VERSION 5.7 ;
  NOWIREEXTENSIONATPIN ON ;
  DIVIDERCHAR "/" ;
  BUSBITCHARS "[]" ;
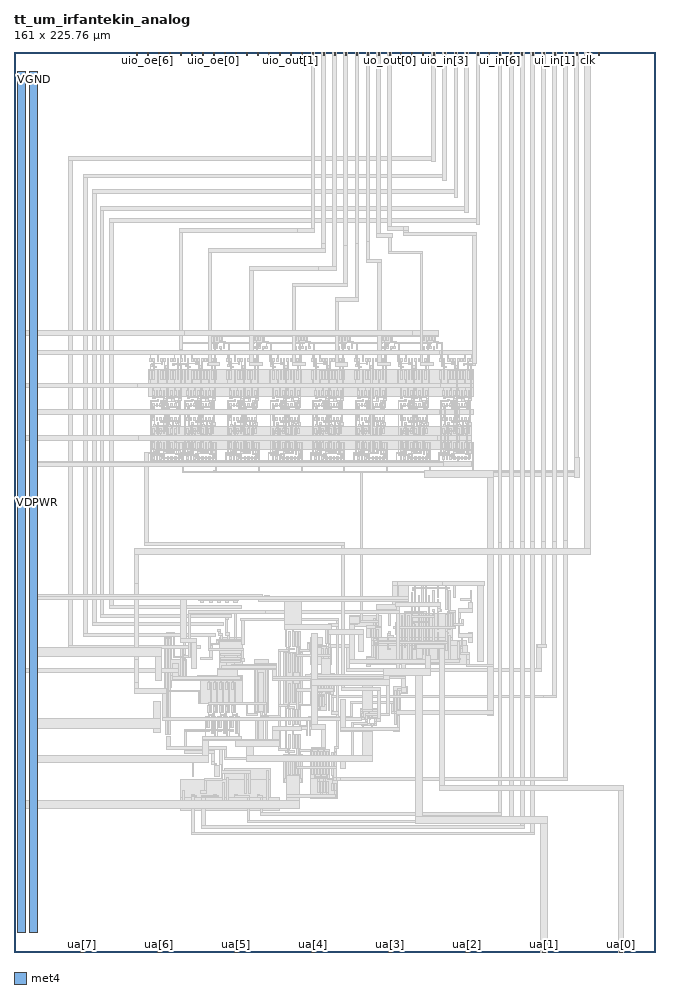
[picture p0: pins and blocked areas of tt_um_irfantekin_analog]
MACRO tt_um_irfantekin_analog
  CLASS BLOCK ;
  FOREIGN tt_um_irfantekin_analog ;
  ORIGIN 0.000 0.000 ;
  SIZE 161.000 BY 225.760 ;
  PIN clk
    DIRECTION INPUT ;
    USE SIGNAL ;
    ANTENNAGATEAREA 0.300000 ;
    ANTENNADIFFAREA 13.200000 ;
    PORT
      LAYER met4 ;
        RECT 143.830 224.760 144.130 225.760 ;
    END
  END clk
  PIN ena
    DIRECTION INPUT ;
    USE SIGNAL ;
    PORT
      LAYER met4 ;
        RECT 146.590 224.760 146.890 225.760 ;
    END
  END ena
  PIN rst_n
    DIRECTION INPUT ;
    USE SIGNAL ;
    ANTENNAGATEAREA 19.900000 ;
    PORT
      LAYER met4 ;
        RECT 141.070 224.760 141.370 225.760 ;
    END
  END rst_n
  PIN ua[0]
    DIRECTION INOUT ;
    USE SIGNAL ;
    ANTENNAGATEAREA 1.500000 ;
    PORT
      LAYER met4 ;
        RECT 151.810 0.000 152.710 1.000 ;
    END
  END ua[0]
  PIN ua[1]
    DIRECTION INOUT ;
    USE SIGNAL ;
    ANTENNAGATEAREA 1.500000 ;
    ANTENNADIFFAREA 16.500000 ;
    PORT
      LAYER met4 ;
        RECT 132.490 0.000 133.390 1.000 ;
    END
  END ua[1]
  PIN ua[2]
    DIRECTION INOUT ;
    USE SIGNAL ;
    PORT
      LAYER met4 ;
        RECT 113.170 0.000 114.070 1.000 ;
    END
  END ua[2]
  PIN ua[3]
    DIRECTION INOUT ;
    USE SIGNAL ;
    PORT
      LAYER met4 ;
        RECT 93.850 0.000 94.750 1.000 ;
    END
  END ua[3]
  PIN ua[4]
    DIRECTION INOUT ;
    USE SIGNAL ;
    PORT
      LAYER met4 ;
        RECT 74.530 0.000 75.430 1.000 ;
    END
  END ua[4]
  PIN ua[5]
    DIRECTION INOUT ;
    USE SIGNAL ;
    PORT
      LAYER met4 ;
        RECT 55.210 0.000 56.110 1.000 ;
    END
  END ua[5]
  PIN ua[6]
    DIRECTION INOUT ;
    USE SIGNAL ;
    PORT
      LAYER met4 ;
        RECT 35.890 0.000 36.790 1.000 ;
    END
  END ua[6]
  PIN ua[7]
    DIRECTION INOUT ;
    USE SIGNAL ;
    PORT
      LAYER met4 ;
        RECT 16.570 0.000 17.470 1.000 ;
    END
  END ua[7]
  PIN ui_in[0]
    DIRECTION INPUT ;
    USE SIGNAL ;
    ANTENNAGATEAREA 2.980000 ;
    PORT
      LAYER met4 ;
        RECT 138.310 224.760 138.610 225.760 ;
    END
  END ui_in[0]
  PIN ui_in[1]
    DIRECTION INPUT ;
    USE SIGNAL ;
    ANTENNAGATEAREA 2.980000 ;
    PORT
      LAYER met4 ;
        RECT 135.550 224.760 135.850 225.760 ;
    END
  END ui_in[1]
  PIN ui_in[2]
    DIRECTION INPUT ;
    USE SIGNAL ;
    ANTENNAGATEAREA 2.980000 ;
    PORT
      LAYER met4 ;
        RECT 132.790 224.760 133.090 225.760 ;
    END
  END ui_in[2]
  PIN ui_in[3]
    DIRECTION INPUT ;
    USE SIGNAL ;
    ANTENNAGATEAREA 4.000000 ;
    PORT
      LAYER met4 ;
        RECT 130.030 224.760 130.330 225.760 ;
    END
  END ui_in[3]
  PIN ui_in[4]
    DIRECTION INPUT ;
    USE SIGNAL ;
    ANTENNAGATEAREA 12.000000 ;
    PORT
      LAYER met4 ;
        RECT 127.270 224.760 127.570 225.760 ;
    END
  END ui_in[4]
  PIN ui_in[5]
    DIRECTION INPUT ;
    USE SIGNAL ;
    ANTENNAGATEAREA 17.199999 ;
    PORT
      LAYER met4 ;
        RECT 124.510 224.760 124.810 225.760 ;
    END
  END ui_in[5]
  PIN ui_in[6]
    DIRECTION INPUT ;
    USE SIGNAL ;
    ANTENNAGATEAREA 24.000000 ;
    PORT
      LAYER met4 ;
        RECT 121.750 224.760 122.050 225.760 ;
    END
  END ui_in[6]
  PIN ui_in[7]
    DIRECTION INPUT ;
    USE SIGNAL ;
    PORT
      LAYER met4 ;
        RECT 118.990 224.760 119.290 225.760 ;
    END
  END ui_in[7]
  PIN uio_in[0]
    DIRECTION INPUT ;
    USE SIGNAL ;
    ANTENNAGATEAREA 2.000000 ;
    PORT
      LAYER met4 ;
        RECT 116.230 224.760 116.530 225.760 ;
    END
  END uio_in[0]
  PIN uio_in[1]
    DIRECTION INPUT ;
    USE SIGNAL ;
    ANTENNAGATEAREA 3.500000 ;
    PORT
      LAYER met4 ;
        RECT 113.470 224.760 113.770 225.760 ;
    END
  END uio_in[1]
  PIN uio_in[2]
    DIRECTION INPUT ;
    USE SIGNAL ;
    ANTENNAGATEAREA 6.500000 ;
    PORT
      LAYER met4 ;
        RECT 110.710 224.760 111.010 225.760 ;
    END
  END uio_in[2]
  PIN uio_in[3]
    DIRECTION INPUT ;
    USE SIGNAL ;
    ANTENNAGATEAREA 10.000000 ;
    PORT
      LAYER met4 ;
        RECT 107.950 224.760 108.250 225.760 ;
    END
  END uio_in[3]
  PIN uio_in[4]
    DIRECTION INPUT ;
    USE SIGNAL ;
    ANTENNAGATEAREA 13.500000 ;
    PORT
      LAYER met4 ;
        RECT 105.190 224.760 105.490 225.760 ;
    END
  END uio_in[4]
  PIN uio_in[5]
    DIRECTION INPUT ;
    USE SIGNAL ;
    PORT
      LAYER met4 ;
        RECT 102.430 224.760 102.730 225.760 ;
    END
  END uio_in[5]
  PIN uio_in[6]
    DIRECTION INPUT ;
    USE SIGNAL ;
    PORT
      LAYER met4 ;
        RECT 99.670 224.760 99.970 225.760 ;
    END
  END uio_in[6]
  PIN uio_in[7]
    DIRECTION INPUT ;
    USE SIGNAL ;
    PORT
      LAYER met4 ;
        RECT 96.910 224.760 97.210 225.760 ;
    END
  END uio_in[7]
  PIN uio_oe[0]
    DIRECTION OUTPUT ;
    USE SIGNAL ;
    PORT
      LAYER met4 ;
        RECT 49.990 224.760 50.290 225.760 ;
    END
  END uio_oe[0]
  PIN uio_oe[1]
    DIRECTION OUTPUT ;
    USE SIGNAL ;
    PORT
      LAYER met4 ;
        RECT 47.230 224.760 47.530 225.760 ;
    END
  END uio_oe[1]
  PIN uio_oe[2]
    DIRECTION OUTPUT ;
    USE SIGNAL ;
    PORT
      LAYER met4 ;
        RECT 44.470 224.760 44.770 225.760 ;
    END
  END uio_oe[2]
  PIN uio_oe[3]
    DIRECTION OUTPUT ;
    USE SIGNAL ;
    PORT
      LAYER met4 ;
        RECT 41.710 224.760 42.010 225.760 ;
    END
  END uio_oe[3]
  PIN uio_oe[4]
    DIRECTION OUTPUT ;
    USE SIGNAL ;
    PORT
      LAYER met4 ;
        RECT 38.950 224.760 39.250 225.760 ;
    END
  END uio_oe[4]
  PIN uio_oe[5]
    DIRECTION OUTPUT ;
    USE SIGNAL ;
    PORT
      LAYER met4 ;
        RECT 36.190 224.760 36.490 225.760 ;
    END
  END uio_oe[5]
  PIN uio_oe[6]
    DIRECTION OUTPUT ;
    USE SIGNAL ;
    PORT
      LAYER met4 ;
        RECT 33.430 224.760 33.730 225.760 ;
    END
  END uio_oe[6]
  PIN uio_oe[7]
    DIRECTION OUTPUT ;
    USE SIGNAL ;
    PORT
      LAYER met4 ;
        RECT 30.670 224.760 30.970 225.760 ;
    END
  END uio_oe[7]
  PIN uio_out[0]
    DIRECTION OUTPUT ;
    USE SIGNAL ;
    PORT
      LAYER met4 ;
        RECT 72.070 224.760 72.370 225.760 ;
    END
  END uio_out[0]
  PIN uio_out[1]
    DIRECTION OUTPUT ;
    USE SIGNAL ;
    PORT
      LAYER met4 ;
        RECT 69.310 224.760 69.610 225.760 ;
    END
  END uio_out[1]
  PIN uio_out[2]
    DIRECTION OUTPUT ;
    USE SIGNAL ;
    PORT
      LAYER met4 ;
        RECT 66.550 224.760 66.850 225.760 ;
    END
  END uio_out[2]
  PIN uio_out[3]
    DIRECTION OUTPUT ;
    USE SIGNAL ;
    PORT
      LAYER met4 ;
        RECT 63.790 224.760 64.090 225.760 ;
    END
  END uio_out[3]
  PIN uio_out[4]
    DIRECTION OUTPUT ;
    USE SIGNAL ;
    PORT
      LAYER met4 ;
        RECT 61.030 224.760 61.330 225.760 ;
    END
  END uio_out[4]
  PIN uio_out[5]
    DIRECTION OUTPUT ;
    USE SIGNAL ;
    PORT
      LAYER met4 ;
        RECT 58.270 224.760 58.570 225.760 ;
    END
  END uio_out[5]
  PIN uio_out[6]
    DIRECTION OUTPUT ;
    USE SIGNAL ;
    PORT
      LAYER met4 ;
        RECT 55.510 224.760 55.810 225.760 ;
    END
  END uio_out[6]
  PIN uio_out[7]
    DIRECTION OUTPUT ;
    USE SIGNAL ;
    PORT
      LAYER met4 ;
        RECT 52.750 224.760 53.050 225.760 ;
    END
  END uio_out[7]
  PIN uo_out[0]
    DIRECTION OUTPUT ;
    USE SIGNAL ;
    ANTENNAGATEAREA 2.150000 ;
    ANTENNADIFFAREA 2.400000 ;
    PORT
      LAYER met4 ;
        RECT 94.150 224.760 94.450 225.760 ;
    END
  END uo_out[0]
  PIN uo_out[1]
    DIRECTION OUTPUT ;
    USE SIGNAL ;
    ANTENNAGATEAREA 2.530000 ;
    ANTENNADIFFAREA 2.400000 ;
    PORT
      LAYER met4 ;
        RECT 91.390 224.760 91.690 225.760 ;
    END
  END uo_out[1]
  PIN uo_out[2]
    DIRECTION OUTPUT ;
    USE SIGNAL ;
    ANTENNAGATEAREA 2.530000 ;
    ANTENNADIFFAREA 2.400000 ;
    PORT
      LAYER met4 ;
        RECT 88.630 224.760 88.930 225.760 ;
    END
  END uo_out[2]
  PIN uo_out[3]
    DIRECTION OUTPUT ;
    USE SIGNAL ;
    ANTENNAGATEAREA 2.530000 ;
    ANTENNADIFFAREA 2.400000 ;
    PORT
      LAYER met4 ;
        RECT 85.870 224.760 86.170 225.760 ;
    END
  END uo_out[3]
  PIN uo_out[4]
    DIRECTION OUTPUT ;
    USE SIGNAL ;
    ANTENNAGATEAREA 2.530000 ;
    ANTENNADIFFAREA 2.400000 ;
    PORT
      LAYER met4 ;
        RECT 83.110 224.760 83.410 225.760 ;
    END
  END uo_out[4]
  PIN uo_out[5]
    DIRECTION OUTPUT ;
    USE SIGNAL ;
    ANTENNAGATEAREA 2.530000 ;
    ANTENNADIFFAREA 2.400000 ;
    PORT
      LAYER met4 ;
        RECT 80.350 224.760 80.650 225.760 ;
    END
  END uo_out[5]
  PIN uo_out[6]
    DIRECTION OUTPUT ;
    USE SIGNAL ;
    ANTENNAGATEAREA 2.530000 ;
    ANTENNADIFFAREA 2.400000 ;
    PORT
      LAYER met4 ;
        RECT 77.590 224.760 77.890 225.760 ;
    END
  END uo_out[6]
  PIN uo_out[7]
    DIRECTION OUTPUT ;
    USE SIGNAL ;
    ANTENNAGATEAREA 3.930000 ;
    ANTENNADIFFAREA 2.400000 ;
    PORT
      LAYER met4 ;
        RECT 74.830 224.760 75.130 225.760 ;
    END
  END uo_out[7]
  PIN VDPWR
    DIRECTION INOUT ;
    USE POWER ;
    PORT
      LAYER met4 ;
        RECT 1.000 5.000 3.000 220.760 ;
    END
  END VDPWR
  PIN VGND
    DIRECTION INOUT ;
    USE GROUND ;
    PORT
      LAYER met4 ;
        RECT 4.000 5.000 6.000 220.760 ;
    END
  END VGND
  OBS
      LAYER nwell ;
        RECT 48.850 154.500 106.450 155.800 ;
        RECT 48.850 153.000 52.250 154.500 ;
        RECT 59.550 153.000 62.950 154.500 ;
        RECT 70.250 153.000 73.650 154.500 ;
        RECT 80.950 153.000 84.350 154.500 ;
        RECT 91.650 153.000 95.050 154.500 ;
        RECT 102.350 153.000 105.750 154.500 ;
        RECT 33.750 139.300 115.250 146.200 ;
        RECT 34.250 126.100 114.750 131.700 ;
        RECT 84.200 81.650 92.100 84.500 ;
        RECT 89.750 81.450 92.100 81.650 ;
        RECT 37.700 73.450 39.600 78.950 ;
        RECT 89.750 78.900 92.150 81.450 ;
        RECT 96.800 78.900 109.900 85.000 ;
        RECT 37.700 69.350 43.300 73.450 ;
        RECT 51.500 70.900 57.200 78.900 ;
        RECT 74.400 76.550 77.500 78.850 ;
        RECT 89.750 78.150 109.900 78.900 ;
        RECT 89.750 76.850 113.400 78.150 ;
        RECT 37.700 68.000 43.350 69.350 ;
        RECT 46.000 68.000 57.350 69.350 ;
        RECT 37.700 66.350 39.600 68.000 ;
        RECT 46.900 62.400 57.350 68.000 ;
        RECT 60.300 60.150 63.800 73.300 ;
        RECT 67.550 62.200 72.350 75.100 ;
        RECT 74.400 72.200 79.700 76.550 ;
        RECT 89.750 72.100 113.850 76.850 ;
        RECT 89.750 72.050 96.950 72.100 ;
        RECT 74.450 65.350 80.350 69.750 ;
        RECT 74.450 62.050 78.350 65.350 ;
        RECT 95.100 64.950 98.700 66.550 ;
        RECT 74.900 60.650 78.300 62.050 ;
        RECT 86.950 58.800 91.250 61.100 ;
        RECT 95.100 60.600 96.950 64.950 ;
        RECT 52.900 43.200 64.300 46.000 ;
        RECT 41.800 43.150 64.300 43.200 ;
        RECT 41.750 38.650 64.300 43.150 ;
        RECT 67.550 42.400 72.350 49.500 ;
        RECT 74.350 43.550 79.150 50.700 ;
        RECT 41.750 35.550 66.500 38.650 ;
        RECT 74.350 38.550 81.250 43.550 ;
      LAYER li1 ;
        RECT 45.750 155.800 48.050 155.900 ;
        RECT 54.150 155.800 56.450 155.900 ;
        RECT 65.850 155.800 68.150 155.900 ;
        RECT 75.250 155.800 77.550 155.900 ;
        RECT 87.050 155.800 89.350 155.900 ;
        RECT 97.550 155.800 99.850 155.900 ;
        RECT 45.050 154.700 106.450 155.800 ;
        RECT 49.250 154.300 49.450 154.700 ;
        RECT 50.850 154.300 51.050 154.700 ;
        RECT 59.950 154.300 60.150 154.700 ;
        RECT 61.550 154.300 61.750 154.700 ;
        RECT 70.650 154.300 70.850 154.700 ;
        RECT 72.250 154.300 72.450 154.700 ;
        RECT 81.350 154.300 81.550 154.700 ;
        RECT 82.950 154.300 83.150 154.700 ;
        RECT 92.050 154.300 92.250 154.700 ;
        RECT 93.650 154.300 93.850 154.700 ;
        RECT 102.750 154.300 102.950 154.700 ;
        RECT 104.350 154.300 104.550 154.700 ;
        RECT 49.150 153.300 49.550 154.300 ;
        RECT 49.950 153.300 50.350 154.300 ;
        RECT 50.750 153.300 51.150 154.300 ;
        RECT 51.550 153.300 51.950 154.300 ;
        RECT 59.850 153.300 60.250 154.300 ;
        RECT 60.650 153.300 61.050 154.300 ;
        RECT 61.450 153.300 61.850 154.300 ;
        RECT 62.250 153.300 62.650 154.300 ;
        RECT 70.550 153.300 70.950 154.300 ;
        RECT 71.350 153.300 71.750 154.300 ;
        RECT 72.150 153.300 72.550 154.300 ;
        RECT 72.950 153.300 73.350 154.300 ;
        RECT 81.250 153.300 81.650 154.300 ;
        RECT 82.050 153.300 82.450 154.300 ;
        RECT 82.850 153.300 83.250 154.300 ;
        RECT 83.650 153.300 84.050 154.300 ;
        RECT 91.950 153.300 92.350 154.300 ;
        RECT 92.750 153.300 93.150 154.300 ;
        RECT 93.550 153.300 93.950 154.300 ;
        RECT 94.350 153.300 94.750 154.300 ;
        RECT 102.650 153.300 103.050 154.300 ;
        RECT 103.450 153.300 103.850 154.300 ;
        RECT 104.250 153.300 104.650 154.300 ;
        RECT 105.050 153.300 105.450 154.300 ;
        RECT 49.350 152.600 49.750 153.000 ;
        RECT 50.050 152.900 50.250 153.300 ;
        RECT 51.650 153.100 51.850 153.300 ;
        RECT 50.950 152.900 51.350 153.000 ;
        RECT 51.650 152.900 53.050 153.100 ;
        RECT 50.050 152.700 51.350 152.900 ;
        RECT 50.850 152.600 51.350 152.700 ;
        RECT 52.550 152.600 53.050 152.900 ;
        RECT 60.050 152.600 60.450 153.000 ;
        RECT 60.750 152.900 60.950 153.300 ;
        RECT 62.350 153.100 62.550 153.300 ;
        RECT 61.650 152.900 62.050 153.000 ;
        RECT 62.350 152.900 63.750 153.100 ;
        RECT 60.750 152.700 62.050 152.900 ;
        RECT 61.550 152.600 62.050 152.700 ;
        RECT 63.250 152.600 63.750 152.900 ;
        RECT 70.750 152.600 71.150 153.000 ;
        RECT 71.450 152.900 71.650 153.300 ;
        RECT 73.050 153.100 73.250 153.300 ;
        RECT 72.350 152.900 72.750 153.000 ;
        RECT 73.050 152.900 74.450 153.100 ;
        RECT 71.450 152.700 72.750 152.900 ;
        RECT 72.250 152.600 72.750 152.700 ;
        RECT 73.950 152.600 74.450 152.900 ;
        RECT 81.450 152.600 81.850 153.000 ;
        RECT 82.150 152.900 82.350 153.300 ;
        RECT 83.750 153.100 83.950 153.300 ;
        RECT 83.050 152.900 83.450 153.000 ;
        RECT 83.750 152.900 85.150 153.100 ;
        RECT 82.150 152.700 83.450 152.900 ;
        RECT 82.950 152.600 83.450 152.700 ;
        RECT 84.650 152.600 85.150 152.900 ;
        RECT 92.150 152.600 92.550 153.000 ;
        RECT 92.850 152.900 93.050 153.300 ;
        RECT 94.450 153.100 94.650 153.300 ;
        RECT 93.750 152.900 94.150 153.000 ;
        RECT 94.450 152.900 95.850 153.100 ;
        RECT 92.850 152.700 94.150 152.900 ;
        RECT 93.650 152.600 94.150 152.700 ;
        RECT 95.350 152.600 95.850 152.900 ;
        RECT 102.850 152.600 103.250 153.000 ;
        RECT 103.550 152.900 103.750 153.300 ;
        RECT 105.150 153.100 105.350 153.300 ;
        RECT 104.450 152.900 104.850 153.000 ;
        RECT 105.150 152.900 106.550 153.100 ;
        RECT 103.550 152.700 104.850 152.900 ;
        RECT 104.350 152.600 104.850 152.700 ;
        RECT 106.050 152.600 106.550 152.900 ;
        RECT 50.150 152.100 50.550 152.500 ;
        RECT 50.850 151.900 51.050 152.600 ;
        RECT 52.550 151.900 52.750 152.600 ;
        RECT 60.850 152.100 61.250 152.500 ;
        RECT 61.550 151.900 61.750 152.600 ;
        RECT 63.250 151.900 63.450 152.600 ;
        RECT 71.550 152.100 71.950 152.500 ;
        RECT 72.250 151.900 72.450 152.600 ;
        RECT 73.950 151.900 74.150 152.600 ;
        RECT 82.250 152.100 82.650 152.500 ;
        RECT 82.950 151.900 83.150 152.600 ;
        RECT 84.650 151.900 84.850 152.600 ;
        RECT 92.950 152.100 93.350 152.500 ;
        RECT 93.650 151.900 93.850 152.600 ;
        RECT 95.350 151.900 95.550 152.600 ;
        RECT 103.650 152.100 104.050 152.500 ;
        RECT 104.350 151.900 104.550 152.600 ;
        RECT 106.050 151.900 106.250 152.600 ;
        RECT 49.150 151.400 49.550 151.900 ;
        RECT 49.950 151.400 50.350 151.900 ;
        RECT 50.750 151.400 51.150 151.900 ;
        RECT 51.650 151.400 52.050 151.900 ;
        RECT 52.450 151.400 52.850 151.900 ;
        RECT 59.850 151.400 60.250 151.900 ;
        RECT 60.650 151.400 61.050 151.900 ;
        RECT 61.450 151.400 61.850 151.900 ;
        RECT 62.350 151.400 62.750 151.900 ;
        RECT 63.150 151.400 63.550 151.900 ;
        RECT 70.550 151.400 70.950 151.900 ;
        RECT 71.350 151.400 71.750 151.900 ;
        RECT 72.150 151.400 72.550 151.900 ;
        RECT 73.050 151.400 73.450 151.900 ;
        RECT 73.850 151.400 74.250 151.900 ;
        RECT 81.250 151.400 81.650 151.900 ;
        RECT 82.050 151.400 82.450 151.900 ;
        RECT 82.850 151.400 83.250 151.900 ;
        RECT 83.750 151.400 84.150 151.900 ;
        RECT 84.550 151.400 84.950 151.900 ;
        RECT 91.950 151.400 92.350 151.900 ;
        RECT 92.750 151.400 93.150 151.900 ;
        RECT 93.550 151.400 93.950 151.900 ;
        RECT 94.450 151.400 94.850 151.900 ;
        RECT 95.250 151.400 95.650 151.900 ;
        RECT 102.650 151.400 103.050 151.900 ;
        RECT 103.450 151.400 103.850 151.900 ;
        RECT 104.250 151.400 104.650 151.900 ;
        RECT 105.150 151.400 105.550 151.900 ;
        RECT 105.950 151.400 106.350 151.900 ;
        RECT 49.250 151.000 49.450 151.400 ;
        RECT 51.750 151.000 51.950 151.400 ;
        RECT 59.950 151.000 60.150 151.400 ;
        RECT 62.450 151.000 62.650 151.400 ;
        RECT 70.650 151.000 70.850 151.400 ;
        RECT 73.150 151.000 73.350 151.400 ;
        RECT 81.350 151.000 81.550 151.400 ;
        RECT 83.850 151.000 84.050 151.400 ;
        RECT 92.050 151.000 92.250 151.400 ;
        RECT 94.550 151.000 94.750 151.400 ;
        RECT 102.750 151.000 102.950 151.400 ;
        RECT 105.250 151.000 105.450 151.400 ;
        RECT 33.750 149.900 115.250 151.000 ;
        RECT 34.150 148.900 34.350 149.900 ;
        RECT 36.050 148.900 36.250 149.900 ;
        RECT 40.150 148.900 40.350 149.900 ;
        RECT 41.850 148.900 42.050 149.900 ;
        RECT 42.750 148.900 42.950 149.900 ;
        RECT 44.650 148.900 44.850 149.900 ;
        RECT 48.750 148.900 48.950 149.900 ;
        RECT 50.450 148.900 50.650 149.900 ;
        RECT 53.450 148.900 53.650 149.900 ;
        RECT 55.350 148.900 55.550 149.900 ;
        RECT 59.450 148.900 59.650 149.900 ;
        RECT 61.150 148.900 61.350 149.900 ;
        RECT 64.150 148.900 64.350 149.900 ;
        RECT 66.050 148.900 66.250 149.900 ;
        RECT 70.150 148.900 70.350 149.900 ;
        RECT 71.850 148.900 72.050 149.900 ;
        RECT 74.850 148.900 75.050 149.900 ;
        RECT 76.750 148.900 76.950 149.900 ;
        RECT 80.850 148.900 81.050 149.900 ;
        RECT 82.550 148.900 82.750 149.900 ;
        RECT 85.550 148.900 85.750 149.900 ;
        RECT 87.450 148.900 87.650 149.900 ;
        RECT 91.550 148.900 91.750 149.900 ;
        RECT 93.250 148.900 93.450 149.900 ;
        RECT 96.250 148.900 96.450 149.900 ;
        RECT 98.150 148.900 98.350 149.900 ;
        RECT 102.250 148.900 102.450 149.900 ;
        RECT 103.950 148.900 104.150 149.900 ;
        RECT 106.950 148.900 107.150 149.900 ;
        RECT 108.850 148.900 109.050 149.900 ;
        RECT 112.950 148.900 113.150 149.900 ;
        RECT 114.650 148.900 114.850 149.900 ;
        RECT 34.050 148.100 34.450 148.900 ;
        RECT 34.850 148.100 35.250 148.900 ;
        RECT 35.950 148.100 36.350 148.900 ;
        RECT 36.750 148.100 37.150 148.900 ;
        RECT 37.550 148.100 37.950 148.900 ;
        RECT 38.450 148.100 38.850 148.900 ;
        RECT 39.250 148.100 39.650 148.900 ;
        RECT 40.050 148.100 40.450 148.900 ;
        RECT 40.950 148.100 41.350 148.900 ;
        RECT 41.750 148.100 42.150 148.900 ;
        RECT 42.650 148.100 43.050 148.900 ;
        RECT 43.450 148.100 43.850 148.900 ;
        RECT 44.550 148.100 44.950 148.900 ;
        RECT 45.350 148.100 45.750 148.900 ;
        RECT 46.150 148.100 46.550 148.900 ;
        RECT 47.050 148.100 47.450 148.900 ;
        RECT 47.850 148.100 48.250 148.900 ;
        RECT 48.650 148.100 49.050 148.900 ;
        RECT 49.550 148.100 49.950 148.900 ;
        RECT 50.350 148.100 50.750 148.900 ;
        RECT 53.350 148.100 53.750 148.900 ;
        RECT 54.150 148.100 54.550 148.900 ;
        RECT 55.250 148.100 55.650 148.900 ;
        RECT 56.050 148.100 56.450 148.900 ;
        RECT 56.850 148.100 57.250 148.900 ;
        RECT 57.750 148.100 58.150 148.900 ;
        RECT 58.550 148.100 58.950 148.900 ;
        RECT 59.350 148.100 59.750 148.900 ;
        RECT 60.250 148.100 60.650 148.900 ;
        RECT 61.050 148.100 61.450 148.900 ;
        RECT 64.050 148.100 64.450 148.900 ;
        RECT 64.850 148.100 65.250 148.900 ;
        RECT 65.950 148.100 66.350 148.900 ;
        RECT 66.750 148.100 67.150 148.900 ;
        RECT 67.550 148.100 67.950 148.900 ;
        RECT 68.450 148.100 68.850 148.900 ;
        RECT 69.250 148.100 69.650 148.900 ;
        RECT 70.050 148.100 70.450 148.900 ;
        RECT 70.950 148.100 71.350 148.900 ;
        RECT 71.750 148.100 72.150 148.900 ;
        RECT 74.750 148.100 75.150 148.900 ;
        RECT 75.550 148.100 75.950 148.900 ;
        RECT 76.650 148.100 77.050 148.900 ;
        RECT 77.450 148.100 77.850 148.900 ;
        RECT 78.250 148.100 78.650 148.900 ;
        RECT 79.150 148.100 79.550 148.900 ;
        RECT 79.950 148.100 80.350 148.900 ;
        RECT 80.750 148.100 81.150 148.900 ;
        RECT 81.650 148.100 82.050 148.900 ;
        RECT 82.450 148.100 82.850 148.900 ;
        RECT 85.450 148.100 85.850 148.900 ;
        RECT 86.250 148.100 86.650 148.900 ;
        RECT 87.350 148.100 87.750 148.900 ;
        RECT 88.150 148.100 88.550 148.900 ;
        RECT 88.950 148.100 89.350 148.900 ;
        RECT 89.850 148.100 90.250 148.900 ;
        RECT 90.650 148.100 91.050 148.900 ;
        RECT 91.450 148.100 91.850 148.900 ;
        RECT 92.350 148.100 92.750 148.900 ;
        RECT 93.150 148.100 93.550 148.900 ;
        RECT 96.150 148.100 96.550 148.900 ;
        RECT 96.950 148.100 97.350 148.900 ;
        RECT 98.050 148.100 98.450 148.900 ;
        RECT 98.850 148.100 99.250 148.900 ;
        RECT 99.650 148.100 100.050 148.900 ;
        RECT 100.550 148.100 100.950 148.900 ;
        RECT 101.350 148.100 101.750 148.900 ;
        RECT 102.150 148.100 102.550 148.900 ;
        RECT 103.050 148.100 103.450 148.900 ;
        RECT 103.850 148.100 104.250 148.900 ;
        RECT 106.850 148.100 107.250 148.900 ;
        RECT 107.650 148.100 108.050 148.900 ;
        RECT 108.750 148.100 109.150 148.900 ;
        RECT 109.550 148.100 109.950 148.900 ;
        RECT 110.350 148.100 110.750 148.900 ;
        RECT 111.250 148.100 111.650 148.900 ;
        RECT 112.050 148.100 112.450 148.900 ;
        RECT 112.850 148.100 113.250 148.900 ;
        RECT 113.750 148.100 114.150 148.900 ;
        RECT 114.550 148.100 114.950 148.900 ;
        RECT 34.350 147.200 34.750 147.300 ;
        RECT 34.150 146.900 34.750 147.200 ;
        RECT 34.950 146.900 35.150 148.100 ;
        RECT 36.950 147.400 37.350 147.800 ;
        RECT 37.650 147.000 37.850 148.100 ;
        RECT 38.550 147.000 38.750 148.100 ;
        RECT 39.850 147.500 40.250 147.600 ;
        RECT 41.050 147.500 41.250 148.100 ;
        RECT 39.850 147.300 41.250 147.500 ;
        RECT 39.850 147.200 40.250 147.300 ;
        RECT 34.150 145.900 34.350 146.900 ;
        RECT 34.950 146.500 35.650 146.900 ;
        RECT 34.950 145.900 35.150 146.500 ;
        RECT 37.650 146.400 38.750 147.000 ;
        RECT 37.650 145.900 37.850 146.400 ;
        RECT 38.550 145.900 38.750 146.400 ;
        RECT 41.050 145.900 41.250 147.300 ;
        RECT 41.550 147.200 41.950 147.600 ;
        RECT 42.950 146.900 43.350 147.300 ;
        RECT 43.550 146.900 43.750 148.100 ;
        RECT 45.550 147.400 45.950 147.800 ;
        RECT 46.250 147.000 46.450 148.100 ;
        RECT 47.150 147.000 47.350 148.100 ;
        RECT 48.450 147.500 48.850 147.600 ;
        RECT 49.650 147.500 49.850 148.100 ;
        RECT 48.450 147.300 49.850 147.500 ;
        RECT 48.450 147.200 48.850 147.300 ;
        RECT 43.550 146.500 44.250 146.900 ;
        RECT 43.550 145.900 43.750 146.500 ;
        RECT 46.250 146.400 47.350 147.000 ;
        RECT 46.250 145.900 46.450 146.400 ;
        RECT 47.150 145.900 47.350 146.400 ;
        RECT 49.650 145.900 49.850 147.300 ;
        RECT 50.150 147.200 50.550 147.600 ;
        RECT 53.650 146.900 54.050 147.300 ;
        RECT 54.250 146.900 54.450 148.100 ;
        RECT 56.250 147.400 56.650 147.800 ;
        RECT 56.950 147.000 57.150 148.100 ;
        RECT 57.850 147.000 58.050 148.100 ;
        RECT 59.150 147.500 59.550 147.600 ;
        RECT 60.350 147.500 60.550 148.100 ;
        RECT 59.150 147.300 60.550 147.500 ;
        RECT 59.150 147.200 59.550 147.300 ;
        RECT 54.250 146.500 54.950 146.900 ;
        RECT 54.250 145.900 54.450 146.500 ;
        RECT 56.950 146.400 58.050 147.000 ;
        RECT 56.950 145.900 57.150 146.400 ;
        RECT 57.850 145.900 58.050 146.400 ;
        RECT 60.350 145.900 60.550 147.300 ;
        RECT 60.850 147.200 61.250 147.600 ;
        RECT 64.350 146.900 64.750 147.300 ;
        RECT 64.950 146.900 65.150 148.100 ;
        RECT 66.950 147.400 67.350 147.800 ;
        RECT 67.650 147.000 67.850 148.100 ;
        RECT 68.550 147.000 68.750 148.100 ;
        RECT 69.850 147.500 70.250 147.600 ;
        RECT 71.050 147.500 71.250 148.100 ;
        RECT 69.850 147.300 71.250 147.500 ;
        RECT 69.850 147.200 70.250 147.300 ;
        RECT 64.950 146.500 65.650 146.900 ;
        RECT 64.950 145.900 65.150 146.500 ;
        RECT 67.650 146.400 68.750 147.000 ;
        RECT 67.650 145.900 67.850 146.400 ;
        RECT 68.550 145.900 68.750 146.400 ;
        RECT 71.050 145.900 71.250 147.300 ;
        RECT 71.550 147.200 71.950 147.600 ;
        RECT 75.050 146.900 75.450 147.300 ;
        RECT 75.650 146.900 75.850 148.100 ;
        RECT 77.650 147.400 78.050 147.800 ;
        RECT 78.350 147.000 78.550 148.100 ;
        RECT 79.250 147.000 79.450 148.100 ;
        RECT 80.550 147.500 80.950 147.600 ;
        RECT 81.750 147.500 81.950 148.100 ;
        RECT 80.550 147.300 81.950 147.500 ;
        RECT 80.550 147.200 80.950 147.300 ;
        RECT 75.650 146.500 76.350 146.900 ;
        RECT 75.650 145.900 75.850 146.500 ;
        RECT 78.350 146.400 79.450 147.000 ;
        RECT 78.350 145.900 78.550 146.400 ;
        RECT 79.250 145.900 79.450 146.400 ;
        RECT 81.750 145.900 81.950 147.300 ;
        RECT 82.250 147.200 82.650 147.600 ;
        RECT 85.750 146.900 86.150 147.300 ;
        RECT 86.350 146.900 86.550 148.100 ;
        RECT 88.350 147.400 88.750 147.800 ;
        RECT 89.050 147.000 89.250 148.100 ;
        RECT 89.950 147.000 90.150 148.100 ;
        RECT 91.250 147.500 91.650 147.600 ;
        RECT 92.450 147.500 92.650 148.100 ;
        RECT 91.250 147.300 92.650 147.500 ;
        RECT 91.250 147.200 91.650 147.300 ;
        RECT 86.350 146.500 87.050 146.900 ;
        RECT 86.350 145.900 86.550 146.500 ;
        RECT 89.050 146.400 90.150 147.000 ;
        RECT 89.050 145.900 89.250 146.400 ;
        RECT 89.950 145.900 90.150 146.400 ;
        RECT 92.450 145.900 92.650 147.300 ;
        RECT 92.950 147.200 93.350 147.600 ;
        RECT 96.450 146.900 96.850 147.300 ;
        RECT 97.050 146.900 97.250 148.100 ;
        RECT 99.050 147.400 99.450 147.800 ;
        RECT 99.750 147.000 99.950 148.100 ;
        RECT 100.650 147.000 100.850 148.100 ;
        RECT 101.950 147.500 102.350 147.600 ;
        RECT 103.150 147.500 103.350 148.100 ;
        RECT 101.950 147.300 103.350 147.500 ;
        RECT 101.950 147.200 102.350 147.300 ;
        RECT 97.050 146.500 97.750 146.900 ;
        RECT 97.050 145.900 97.250 146.500 ;
        RECT 99.750 146.400 100.850 147.000 ;
        RECT 99.750 145.900 99.950 146.400 ;
        RECT 100.650 145.900 100.850 146.400 ;
        RECT 103.150 145.900 103.350 147.300 ;
        RECT 103.650 147.200 104.050 147.600 ;
        RECT 107.150 146.900 107.550 147.300 ;
        RECT 107.750 146.900 107.950 148.100 ;
        RECT 109.750 147.400 110.150 147.800 ;
        RECT 110.450 147.000 110.650 148.100 ;
        RECT 111.350 147.000 111.550 148.100 ;
        RECT 112.650 147.500 113.050 147.600 ;
        RECT 113.850 147.500 114.050 148.100 ;
        RECT 112.650 147.300 114.050 147.500 ;
        RECT 112.650 147.200 113.050 147.300 ;
        RECT 107.750 146.500 108.450 146.900 ;
        RECT 107.750 145.900 107.950 146.500 ;
        RECT 110.450 146.400 111.550 147.000 ;
        RECT 110.450 145.900 110.650 146.400 ;
        RECT 111.350 145.900 111.550 146.400 ;
        RECT 113.850 145.900 114.050 147.300 ;
        RECT 114.350 147.200 114.750 147.600 ;
        RECT 34.050 143.600 34.450 145.900 ;
        RECT 34.850 143.600 35.250 145.900 ;
        RECT 35.950 143.600 36.350 145.900 ;
        RECT 36.750 143.600 37.150 145.900 ;
        RECT 37.550 143.600 37.950 145.900 ;
        RECT 38.450 143.600 38.850 145.900 ;
        RECT 39.250 143.600 39.650 145.900 ;
        RECT 40.050 143.600 40.450 145.900 ;
        RECT 40.950 143.600 41.350 145.900 ;
        RECT 41.750 143.600 42.150 145.900 ;
        RECT 42.650 143.600 43.050 145.900 ;
        RECT 43.450 143.600 43.850 145.900 ;
        RECT 44.550 143.600 44.950 145.900 ;
        RECT 45.350 143.600 45.750 145.900 ;
        RECT 46.150 143.600 46.550 145.900 ;
        RECT 47.050 143.600 47.450 145.900 ;
        RECT 47.850 143.600 48.250 145.900 ;
        RECT 48.650 143.600 49.050 145.900 ;
        RECT 49.550 143.600 49.950 145.900 ;
        RECT 50.350 143.600 50.750 145.900 ;
        RECT 53.350 143.600 53.750 145.900 ;
        RECT 54.150 143.600 54.550 145.900 ;
        RECT 55.250 143.600 55.650 145.900 ;
        RECT 56.050 143.600 56.450 145.900 ;
        RECT 56.850 143.600 57.250 145.900 ;
        RECT 57.750 143.600 58.150 145.900 ;
        RECT 58.550 143.600 58.950 145.900 ;
        RECT 59.350 143.600 59.750 145.900 ;
        RECT 60.250 143.600 60.650 145.900 ;
        RECT 61.050 143.600 61.450 145.900 ;
        RECT 64.050 143.600 64.450 145.900 ;
        RECT 64.850 143.600 65.250 145.900 ;
        RECT 65.950 143.600 66.350 145.900 ;
        RECT 66.750 143.600 67.150 145.900 ;
        RECT 67.550 143.600 67.950 145.900 ;
        RECT 68.450 143.600 68.850 145.900 ;
        RECT 69.250 143.600 69.650 145.900 ;
        RECT 70.050 143.600 70.450 145.900 ;
        RECT 70.950 143.600 71.350 145.900 ;
        RECT 71.750 143.600 72.150 145.900 ;
        RECT 74.750 143.600 75.150 145.900 ;
        RECT 75.550 143.600 75.950 145.900 ;
        RECT 76.650 143.600 77.050 145.900 ;
        RECT 77.450 143.600 77.850 145.900 ;
        RECT 78.250 143.600 78.650 145.900 ;
        RECT 79.150 143.600 79.550 145.900 ;
        RECT 79.950 143.600 80.350 145.900 ;
        RECT 80.750 143.600 81.150 145.900 ;
        RECT 81.650 143.600 82.050 145.900 ;
        RECT 82.450 143.600 82.850 145.900 ;
        RECT 85.450 143.600 85.850 145.900 ;
        RECT 86.250 143.600 86.650 145.900 ;
        RECT 87.350 143.600 87.750 145.900 ;
        RECT 88.150 143.600 88.550 145.900 ;
        RECT 88.950 143.600 89.350 145.900 ;
        RECT 89.850 143.600 90.250 145.900 ;
        RECT 90.650 143.600 91.050 145.900 ;
        RECT 91.450 143.600 91.850 145.900 ;
        RECT 92.350 143.600 92.750 145.900 ;
        RECT 93.150 143.600 93.550 145.900 ;
        RECT 96.150 143.600 96.550 145.900 ;
        RECT 96.950 143.600 97.350 145.900 ;
        RECT 98.050 143.600 98.450 145.900 ;
        RECT 98.850 143.600 99.250 145.900 ;
        RECT 99.650 143.600 100.050 145.900 ;
        RECT 100.550 143.600 100.950 145.900 ;
        RECT 101.350 143.600 101.750 145.900 ;
        RECT 102.150 143.600 102.550 145.900 ;
        RECT 103.050 143.600 103.450 145.900 ;
        RECT 103.850 143.600 104.250 145.900 ;
        RECT 106.850 143.600 107.250 145.900 ;
        RECT 107.650 143.600 108.050 145.900 ;
        RECT 108.750 143.600 109.150 145.900 ;
        RECT 109.550 143.600 109.950 145.900 ;
        RECT 110.350 143.600 110.750 145.900 ;
        RECT 111.250 143.600 111.650 145.900 ;
        RECT 112.050 143.600 112.450 145.900 ;
        RECT 112.850 143.600 113.250 145.900 ;
        RECT 113.750 143.600 114.150 145.900 ;
        RECT 114.550 143.600 114.950 145.900 ;
        RECT 34.150 142.700 34.350 143.600 ;
        RECT 36.050 142.700 36.250 143.600 ;
        RECT 40.150 142.700 40.350 143.600 ;
        RECT 41.850 142.700 42.050 143.600 ;
        RECT 42.750 142.700 42.950 143.600 ;
        RECT 44.650 142.700 44.850 143.600 ;
        RECT 48.750 142.700 48.950 143.600 ;
        RECT 50.450 142.700 50.650 143.600 ;
        RECT 53.450 142.700 53.650 143.600 ;
        RECT 55.350 142.700 55.550 143.600 ;
        RECT 59.450 142.700 59.650 143.600 ;
        RECT 61.150 142.700 61.350 143.600 ;
        RECT 64.150 142.700 64.350 143.600 ;
        RECT 66.050 142.700 66.250 143.600 ;
        RECT 70.150 142.700 70.350 143.600 ;
        RECT 71.850 142.700 72.050 143.600 ;
        RECT 74.850 142.700 75.050 143.600 ;
        RECT 76.750 142.700 76.950 143.600 ;
        RECT 80.850 142.700 81.050 143.600 ;
        RECT 82.550 142.700 82.750 143.600 ;
        RECT 85.550 142.700 85.750 143.600 ;
        RECT 87.450 142.700 87.650 143.600 ;
        RECT 91.550 142.700 91.750 143.600 ;
        RECT 93.250 142.700 93.450 143.600 ;
        RECT 96.250 142.700 96.450 143.600 ;
        RECT 98.150 142.700 98.350 143.600 ;
        RECT 102.250 142.700 102.450 143.600 ;
        RECT 103.950 142.700 104.150 143.600 ;
        RECT 106.950 142.700 107.150 143.600 ;
        RECT 108.850 142.700 109.050 143.600 ;
        RECT 112.950 142.700 113.150 143.600 ;
        RECT 114.650 142.700 114.850 143.600 ;
        RECT 33.750 141.500 115.250 142.700 ;
        RECT 34.850 140.900 35.050 141.500 ;
        RECT 36.650 140.900 36.850 141.500 ;
        RECT 38.550 140.900 38.750 141.500 ;
        RECT 40.350 140.900 40.550 141.500 ;
        RECT 43.450 140.900 43.650 141.500 ;
        RECT 45.250 140.900 45.450 141.500 ;
        RECT 47.150 140.900 47.350 141.500 ;
        RECT 48.950 140.900 49.150 141.500 ;
        RECT 54.150 140.900 54.350 141.500 ;
        RECT 55.950 140.900 56.150 141.500 ;
        RECT 57.850 140.900 58.050 141.500 ;
        RECT 59.650 140.900 59.850 141.500 ;
        RECT 64.850 140.900 65.050 141.500 ;
        RECT 66.650 140.900 66.850 141.500 ;
        RECT 68.550 140.900 68.750 141.500 ;
        RECT 70.350 140.900 70.550 141.500 ;
        RECT 75.550 140.900 75.750 141.500 ;
        RECT 77.350 140.900 77.550 141.500 ;
        RECT 79.250 140.900 79.450 141.500 ;
        RECT 81.050 140.900 81.250 141.500 ;
        RECT 86.250 140.900 86.450 141.500 ;
        RECT 88.050 140.900 88.250 141.500 ;
        RECT 89.950 140.900 90.150 141.500 ;
        RECT 91.750 140.900 91.950 141.500 ;
        RECT 96.950 140.900 97.150 141.500 ;
        RECT 98.750 140.900 98.950 141.500 ;
        RECT 100.650 140.900 100.850 141.500 ;
        RECT 102.450 140.900 102.650 141.500 ;
        RECT 107.650 140.900 107.850 141.500 ;
        RECT 109.450 140.900 109.650 141.500 ;
        RECT 111.350 140.900 111.550 141.500 ;
        RECT 113.150 140.900 113.350 141.500 ;
        RECT 34.750 139.600 35.150 140.900 ;
        RECT 35.650 139.600 36.050 140.900 ;
        RECT 36.550 139.600 36.950 140.900 ;
        RECT 37.450 139.600 37.850 140.900 ;
        RECT 38.450 139.600 38.850 140.900 ;
        RECT 39.350 139.600 39.750 140.900 ;
        RECT 40.250 139.600 40.650 140.900 ;
        RECT 41.150 139.600 41.550 140.900 ;
        RECT 43.350 139.600 43.750 140.900 ;
        RECT 44.250 139.600 44.650 140.900 ;
        RECT 45.150 139.600 45.550 140.900 ;
        RECT 46.050 139.600 46.450 140.900 ;
        RECT 47.050 139.600 47.450 140.900 ;
        RECT 47.950 139.600 48.350 140.900 ;
        RECT 48.850 139.600 49.250 140.900 ;
        RECT 49.750 139.600 50.150 140.900 ;
        RECT 54.050 139.600 54.450 140.900 ;
        RECT 54.950 139.600 55.350 140.900 ;
        RECT 55.850 139.600 56.250 140.900 ;
        RECT 56.750 139.600 57.150 140.900 ;
        RECT 57.750 139.600 58.150 140.900 ;
        RECT 58.650 139.600 59.050 140.900 ;
        RECT 59.550 139.600 59.950 140.900 ;
        RECT 60.450 139.600 60.850 140.900 ;
        RECT 64.750 139.600 65.150 140.900 ;
        RECT 65.650 139.600 66.050 140.900 ;
        RECT 66.550 139.600 66.950 140.900 ;
        RECT 67.450 139.600 67.850 140.900 ;
        RECT 68.450 139.600 68.850 140.900 ;
        RECT 69.350 139.600 69.750 140.900 ;
        RECT 70.250 139.600 70.650 140.900 ;
        RECT 71.150 139.600 71.550 140.900 ;
        RECT 75.450 139.600 75.850 140.900 ;
        RECT 76.350 139.600 76.750 140.900 ;
        RECT 77.250 139.600 77.650 140.900 ;
        RECT 78.150 139.600 78.550 140.900 ;
        RECT 79.150 139.600 79.550 140.900 ;
        RECT 80.050 139.600 80.450 140.900 ;
        RECT 80.950 139.600 81.350 140.900 ;
        RECT 81.850 139.600 82.250 140.900 ;
        RECT 86.150 139.600 86.550 140.900 ;
        RECT 87.050 139.600 87.450 140.900 ;
        RECT 87.950 139.600 88.350 140.900 ;
        RECT 88.850 139.600 89.250 140.900 ;
        RECT 89.850 139.600 90.250 140.900 ;
        RECT 90.750 139.600 91.150 140.900 ;
        RECT 91.650 139.600 92.050 140.900 ;
        RECT 92.550 139.600 92.950 140.900 ;
        RECT 96.850 139.600 97.250 140.900 ;
        RECT 97.750 139.600 98.150 140.900 ;
        RECT 98.650 139.600 99.050 140.900 ;
        RECT 99.550 139.600 99.950 140.900 ;
        RECT 100.550 139.600 100.950 140.900 ;
        RECT 101.450 139.600 101.850 140.900 ;
        RECT 102.350 139.600 102.750 140.900 ;
        RECT 103.250 139.600 103.650 140.900 ;
        RECT 107.550 139.600 107.950 140.900 ;
        RECT 108.450 139.600 108.850 140.900 ;
        RECT 109.350 139.600 109.750 140.900 ;
        RECT 110.250 139.600 110.650 140.900 ;
        RECT 111.250 139.600 111.650 140.900 ;
        RECT 112.150 139.600 112.550 140.900 ;
        RECT 113.050 139.600 113.450 140.900 ;
        RECT 113.950 139.600 114.350 140.900 ;
        RECT 34.850 139.200 35.050 139.600 ;
        RECT 35.750 139.200 35.950 139.600 ;
        RECT 37.550 139.200 37.750 139.600 ;
        RECT 34.850 138.900 35.450 139.200 ;
        RECT 35.750 139.000 37.750 139.200 ;
        RECT 35.050 138.800 35.450 138.900 ;
        RECT 37.550 138.900 37.750 139.000 ;
        RECT 38.550 139.200 38.750 139.600 ;
        RECT 39.450 139.200 39.650 139.600 ;
        RECT 41.250 139.200 41.450 139.600 ;
        RECT 38.550 138.900 39.150 139.200 ;
        RECT 39.450 139.000 41.450 139.200 ;
        RECT 35.950 138.300 36.350 138.700 ;
        RECT 36.750 137.800 37.350 138.400 ;
        RECT 37.550 138.300 38.150 138.900 ;
        RECT 38.750 138.800 39.150 138.900 ;
        RECT 41.250 138.900 41.450 139.000 ;
        RECT 43.450 139.200 43.650 139.600 ;
        RECT 44.350 139.200 44.550 139.600 ;
        RECT 46.150 139.200 46.350 139.600 ;
        RECT 43.450 138.900 44.050 139.200 ;
        RECT 44.350 139.000 46.350 139.200 ;
        RECT 37.550 137.600 37.750 138.300 ;
        RECT 39.550 138.200 40.150 138.800 ;
        RECT 40.450 137.800 41.050 138.400 ;
        RECT 41.250 138.300 41.850 138.900 ;
        RECT 43.650 138.800 44.050 138.900 ;
        RECT 46.150 138.900 46.350 139.000 ;
        RECT 47.150 139.200 47.350 139.600 ;
        RECT 48.050 139.200 48.250 139.600 ;
        RECT 49.850 139.200 50.050 139.600 ;
        RECT 47.150 138.900 47.750 139.200 ;
        RECT 48.050 139.000 50.050 139.200 ;
        RECT 44.550 138.300 44.950 138.700 ;
        RECT 41.250 137.600 41.450 138.300 ;
        RECT 45.350 137.800 45.950 138.400 ;
        RECT 46.150 138.300 46.750 138.900 ;
        RECT 47.350 138.800 47.750 138.900 ;
        RECT 49.850 138.900 50.050 139.000 ;
        RECT 54.150 139.200 54.350 139.600 ;
        RECT 55.050 139.200 55.250 139.600 ;
        RECT 56.850 139.200 57.050 139.600 ;
        RECT 54.150 138.900 54.750 139.200 ;
        RECT 55.050 139.000 57.050 139.200 ;
        RECT 46.150 137.600 46.350 138.300 ;
        RECT 48.150 138.200 48.750 138.800 ;
        RECT 49.050 137.800 49.650 138.400 ;
        RECT 49.850 138.300 50.450 138.900 ;
        RECT 54.350 138.800 54.750 138.900 ;
        RECT 56.850 138.900 57.050 139.000 ;
        RECT 57.850 139.200 58.050 139.600 ;
        RECT 58.750 139.200 58.950 139.600 ;
        RECT 60.550 139.200 60.750 139.600 ;
        RECT 57.850 138.900 58.450 139.200 ;
        RECT 58.750 139.000 60.750 139.200 ;
        RECT 55.250 138.300 55.650 138.700 ;
        RECT 49.850 137.600 50.050 138.300 ;
        RECT 56.050 137.800 56.650 138.400 ;
        RECT 56.850 138.300 57.450 138.900 ;
        RECT 58.050 138.800 58.450 138.900 ;
        RECT 60.550 138.900 60.750 139.000 ;
        RECT 64.850 139.200 65.050 139.600 ;
        RECT 65.750 139.200 65.950 139.600 ;
        RECT 67.550 139.200 67.750 139.600 ;
        RECT 64.850 138.900 65.450 139.200 ;
        RECT 65.750 139.000 67.750 139.200 ;
        RECT 56.850 137.600 57.050 138.300 ;
        RECT 58.850 138.200 59.450 138.800 ;
        RECT 59.750 137.800 60.350 138.400 ;
        RECT 60.550 138.300 61.150 138.900 ;
        RECT 65.050 138.800 65.450 138.900 ;
        RECT 67.550 138.900 67.750 139.000 ;
        RECT 68.550 139.200 68.750 139.600 ;
        RECT 69.450 139.200 69.650 139.600 ;
        RECT 71.250 139.200 71.450 139.600 ;
        RECT 68.550 138.900 69.150 139.200 ;
        RECT 69.450 139.000 71.450 139.200 ;
        RECT 65.950 138.300 66.350 138.700 ;
        RECT 60.550 137.600 60.750 138.300 ;
        RECT 66.750 137.800 67.350 138.400 ;
        RECT 67.550 138.300 68.150 138.900 ;
        RECT 68.750 138.800 69.150 138.900 ;
        RECT 71.250 138.900 71.450 139.000 ;
        RECT 75.550 139.200 75.750 139.600 ;
        RECT 76.450 139.200 76.650 139.600 ;
        RECT 78.250 139.200 78.450 139.600 ;
        RECT 75.550 138.900 76.150 139.200 ;
        RECT 76.450 139.000 78.450 139.200 ;
        RECT 67.550 137.600 67.750 138.300 ;
        RECT 69.550 138.200 70.150 138.800 ;
        RECT 70.450 137.800 71.050 138.400 ;
        RECT 71.250 138.300 71.850 138.900 ;
        RECT 75.750 138.800 76.150 138.900 ;
        RECT 78.250 138.900 78.450 139.000 ;
        RECT 79.250 139.200 79.450 139.600 ;
        RECT 80.150 139.200 80.350 139.600 ;
        RECT 81.950 139.200 82.150 139.600 ;
        RECT 79.250 138.900 79.850 139.200 ;
        RECT 80.150 139.000 82.150 139.200 ;
        RECT 76.650 138.300 77.050 138.700 ;
        RECT 71.250 137.600 71.450 138.300 ;
        RECT 77.450 137.800 78.050 138.400 ;
        RECT 78.250 138.300 78.850 138.900 ;
        RECT 79.450 138.800 79.850 138.900 ;
        RECT 81.950 138.900 82.150 139.000 ;
        RECT 86.250 139.200 86.450 139.600 ;
        RECT 87.150 139.200 87.350 139.600 ;
        RECT 88.950 139.200 89.150 139.600 ;
        RECT 86.250 138.900 86.850 139.200 ;
        RECT 87.150 139.000 89.150 139.200 ;
        RECT 78.250 137.600 78.450 138.300 ;
        RECT 80.250 138.200 80.850 138.800 ;
        RECT 81.150 137.800 81.750 138.400 ;
        RECT 81.950 138.300 82.550 138.900 ;
        RECT 86.450 138.800 86.850 138.900 ;
        RECT 88.950 138.900 89.150 139.000 ;
        RECT 89.950 139.200 90.150 139.600 ;
        RECT 90.850 139.200 91.050 139.600 ;
        RECT 92.650 139.200 92.850 139.600 ;
        RECT 89.950 138.900 90.550 139.200 ;
        RECT 90.850 139.000 92.850 139.200 ;
        RECT 87.350 138.300 87.750 138.700 ;
        RECT 81.950 137.600 82.150 138.300 ;
        RECT 88.150 137.800 88.750 138.400 ;
        RECT 88.950 138.300 89.550 138.900 ;
        RECT 90.150 138.800 90.550 138.900 ;
        RECT 92.650 138.900 92.850 139.000 ;
        RECT 96.950 139.200 97.150 139.600 ;
        RECT 97.850 139.200 98.050 139.600 ;
        RECT 99.650 139.200 99.850 139.600 ;
        RECT 96.950 138.900 97.550 139.200 ;
        RECT 97.850 139.000 99.850 139.200 ;
        RECT 88.950 137.600 89.150 138.300 ;
        RECT 90.950 138.200 91.550 138.800 ;
        RECT 91.850 137.800 92.450 138.400 ;
        RECT 92.650 138.300 93.250 138.900 ;
        RECT 97.150 138.800 97.550 138.900 ;
        RECT 99.650 138.900 99.850 139.000 ;
        RECT 100.650 139.200 100.850 139.600 ;
        RECT 101.550 139.200 101.750 139.600 ;
        RECT 103.350 139.200 103.550 139.600 ;
        RECT 100.650 138.900 101.250 139.200 ;
        RECT 101.550 139.000 103.550 139.200 ;
        RECT 98.050 138.300 98.450 138.700 ;
        RECT 92.650 137.600 92.850 138.300 ;
        RECT 98.850 137.800 99.450 138.400 ;
        RECT 99.650 138.300 100.250 138.900 ;
        RECT 100.850 138.800 101.250 138.900 ;
        RECT 103.350 138.900 103.550 139.000 ;
        RECT 107.650 139.200 107.850 139.600 ;
        RECT 108.550 139.200 108.750 139.600 ;
        RECT 110.350 139.200 110.550 139.600 ;
        RECT 107.650 138.900 108.250 139.200 ;
        RECT 108.550 139.000 110.550 139.200 ;
        RECT 99.650 137.600 99.850 138.300 ;
        RECT 101.650 138.200 102.250 138.800 ;
        RECT 102.550 137.800 103.150 138.400 ;
        RECT 103.350 138.300 103.950 138.900 ;
        RECT 107.850 138.800 108.250 138.900 ;
        RECT 110.350 138.900 110.550 139.000 ;
        RECT 111.350 139.200 111.550 139.600 ;
        RECT 112.250 139.200 112.450 139.600 ;
        RECT 114.050 139.200 114.250 139.600 ;
        RECT 111.350 138.900 111.950 139.200 ;
        RECT 112.250 139.000 114.250 139.200 ;
        RECT 108.750 138.300 109.150 138.700 ;
        RECT 103.350 137.600 103.550 138.300 ;
        RECT 109.550 137.800 110.150 138.400 ;
        RECT 110.350 138.300 110.950 138.900 ;
        RECT 111.550 138.800 111.950 138.900 ;
        RECT 114.050 138.900 114.250 139.000 ;
        RECT 110.350 137.600 110.550 138.300 ;
        RECT 112.350 138.200 112.950 138.800 ;
        RECT 113.250 137.800 113.850 138.400 ;
        RECT 114.050 138.300 114.650 138.900 ;
        RECT 114.050 137.600 114.250 138.300 ;
        RECT 34.750 136.800 35.150 137.600 ;
        RECT 35.650 136.800 36.050 137.600 ;
        RECT 36.550 136.800 36.950 137.600 ;
        RECT 37.450 136.800 37.850 137.600 ;
        RECT 38.450 136.800 38.850 137.600 ;
        RECT 39.350 136.800 39.750 137.600 ;
        RECT 40.250 136.800 40.650 137.600 ;
        RECT 41.150 136.800 41.550 137.600 ;
        RECT 43.350 136.800 43.750 137.600 ;
        RECT 44.250 136.800 44.650 137.600 ;
        RECT 45.150 136.800 45.550 137.600 ;
        RECT 46.050 136.800 46.450 137.600 ;
        RECT 47.050 136.800 47.450 137.600 ;
        RECT 47.950 136.800 48.350 137.600 ;
        RECT 48.850 136.800 49.250 137.600 ;
        RECT 49.750 136.800 50.150 137.600 ;
        RECT 54.050 136.800 54.450 137.600 ;
        RECT 54.950 136.800 55.350 137.600 ;
        RECT 55.850 136.800 56.250 137.600 ;
        RECT 56.750 136.800 57.150 137.600 ;
        RECT 57.750 136.800 58.150 137.600 ;
        RECT 58.650 136.800 59.050 137.600 ;
        RECT 59.550 136.800 59.950 137.600 ;
        RECT 60.450 136.800 60.850 137.600 ;
        RECT 64.750 136.800 65.150 137.600 ;
        RECT 65.650 136.800 66.050 137.600 ;
        RECT 66.550 136.800 66.950 137.600 ;
        RECT 67.450 136.800 67.850 137.600 ;
        RECT 68.450 136.800 68.850 137.600 ;
        RECT 69.350 136.800 69.750 137.600 ;
        RECT 70.250 136.800 70.650 137.600 ;
        RECT 71.150 136.800 71.550 137.600 ;
        RECT 75.450 136.800 75.850 137.600 ;
        RECT 76.350 136.800 76.750 137.600 ;
        RECT 77.250 136.800 77.650 137.600 ;
        RECT 78.150 136.800 78.550 137.600 ;
        RECT 79.150 136.800 79.550 137.600 ;
        RECT 80.050 136.800 80.450 137.600 ;
        RECT 80.950 136.800 81.350 137.600 ;
        RECT 81.850 136.800 82.250 137.600 ;
        RECT 86.150 136.800 86.550 137.600 ;
        RECT 87.050 136.800 87.450 137.600 ;
        RECT 87.950 136.800 88.350 137.600 ;
        RECT 88.850 136.800 89.250 137.600 ;
        RECT 89.850 136.800 90.250 137.600 ;
        RECT 90.750 136.800 91.150 137.600 ;
        RECT 91.650 136.800 92.050 137.600 ;
        RECT 92.550 136.800 92.950 137.600 ;
        RECT 96.850 136.800 97.250 137.600 ;
        RECT 97.750 136.800 98.150 137.600 ;
        RECT 98.650 136.800 99.050 137.600 ;
        RECT 99.550 136.800 99.950 137.600 ;
        RECT 100.550 136.800 100.950 137.600 ;
        RECT 101.450 136.800 101.850 137.600 ;
        RECT 102.350 136.800 102.750 137.600 ;
        RECT 103.250 136.800 103.650 137.600 ;
        RECT 107.550 136.800 107.950 137.600 ;
        RECT 108.450 136.800 108.850 137.600 ;
        RECT 109.350 136.800 109.750 137.600 ;
        RECT 110.250 136.800 110.650 137.600 ;
        RECT 111.250 136.800 111.650 137.600 ;
        RECT 112.150 136.800 112.550 137.600 ;
        RECT 113.050 136.800 113.450 137.600 ;
        RECT 113.950 136.800 114.350 137.600 ;
        RECT 34.850 136.200 35.050 136.800 ;
        RECT 38.550 136.200 38.750 136.800 ;
        RECT 43.450 136.200 43.650 136.800 ;
        RECT 47.150 136.200 47.350 136.800 ;
        RECT 54.150 136.200 54.350 136.800 ;
        RECT 57.850 136.200 58.050 136.800 ;
        RECT 64.850 136.200 65.050 136.800 ;
        RECT 68.550 136.200 68.750 136.800 ;
        RECT 75.550 136.200 75.750 136.800 ;
        RECT 79.250 136.200 79.450 136.800 ;
        RECT 86.250 136.200 86.450 136.800 ;
        RECT 89.950 136.200 90.150 136.800 ;
        RECT 96.950 136.200 97.150 136.800 ;
        RECT 100.650 136.200 100.850 136.800 ;
        RECT 107.650 136.200 107.850 136.800 ;
        RECT 111.350 136.200 111.550 136.800 ;
        RECT 33.750 134.800 115.250 136.200 ;
        RECT 34.850 134.200 35.050 134.800 ;
        RECT 38.550 134.200 38.750 134.800 ;
        RECT 43.450 134.200 43.650 134.800 ;
        RECT 47.150 134.200 47.350 134.800 ;
        RECT 54.150 134.200 54.350 134.800 ;
        RECT 57.850 134.200 58.050 134.800 ;
        RECT 64.850 134.200 65.050 134.800 ;
        RECT 68.550 134.200 68.750 134.800 ;
        RECT 75.550 134.200 75.750 134.800 ;
        RECT 79.250 134.200 79.450 134.800 ;
        RECT 86.250 134.200 86.450 134.800 ;
        RECT 89.950 134.200 90.150 134.800 ;
        RECT 96.950 134.200 97.150 134.800 ;
        RECT 100.650 134.200 100.850 134.800 ;
        RECT 107.650 134.200 107.850 134.800 ;
        RECT 111.350 134.200 111.550 134.800 ;
        RECT 34.750 133.400 35.150 134.200 ;
        RECT 35.650 133.400 36.050 134.200 ;
        RECT 36.550 133.400 36.950 134.200 ;
        RECT 37.450 133.400 37.850 134.200 ;
        RECT 38.450 133.400 38.850 134.200 ;
        RECT 39.350 133.400 39.750 134.200 ;
        RECT 40.250 133.400 40.650 134.200 ;
        RECT 41.150 133.400 41.550 134.200 ;
        RECT 43.350 133.400 43.750 134.200 ;
        RECT 44.250 133.400 44.650 134.200 ;
        RECT 45.150 133.400 45.550 134.200 ;
        RECT 46.050 133.400 46.450 134.200 ;
        RECT 47.050 133.400 47.450 134.200 ;
        RECT 47.950 133.400 48.350 134.200 ;
        RECT 48.850 133.400 49.250 134.200 ;
        RECT 49.750 133.400 50.150 134.200 ;
        RECT 54.050 133.400 54.450 134.200 ;
        RECT 54.950 133.400 55.350 134.200 ;
        RECT 55.850 133.400 56.250 134.200 ;
        RECT 56.750 133.400 57.150 134.200 ;
        RECT 57.750 133.400 58.150 134.200 ;
        RECT 58.650 133.400 59.050 134.200 ;
        RECT 59.550 133.400 59.950 134.200 ;
        RECT 60.450 133.400 60.850 134.200 ;
        RECT 64.750 133.400 65.150 134.200 ;
        RECT 65.650 133.400 66.050 134.200 ;
        RECT 66.550 133.400 66.950 134.200 ;
        RECT 67.450 133.400 67.850 134.200 ;
        RECT 68.450 133.400 68.850 134.200 ;
        RECT 69.350 133.400 69.750 134.200 ;
        RECT 70.250 133.400 70.650 134.200 ;
        RECT 71.150 133.400 71.550 134.200 ;
        RECT 75.450 133.400 75.850 134.200 ;
        RECT 76.350 133.400 76.750 134.200 ;
        RECT 77.250 133.400 77.650 134.200 ;
        RECT 78.150 133.400 78.550 134.200 ;
        RECT 79.150 133.400 79.550 134.200 ;
        RECT 80.050 133.400 80.450 134.200 ;
        RECT 80.950 133.400 81.350 134.200 ;
        RECT 81.850 133.400 82.250 134.200 ;
        RECT 86.150 133.400 86.550 134.200 ;
        RECT 87.050 133.400 87.450 134.200 ;
        RECT 87.950 133.400 88.350 134.200 ;
        RECT 88.850 133.400 89.250 134.200 ;
        RECT 89.850 133.400 90.250 134.200 ;
        RECT 90.750 133.400 91.150 134.200 ;
        RECT 91.650 133.400 92.050 134.200 ;
        RECT 92.550 133.400 92.950 134.200 ;
        RECT 96.850 133.400 97.250 134.200 ;
        RECT 97.750 133.400 98.150 134.200 ;
        RECT 98.650 133.400 99.050 134.200 ;
        RECT 99.550 133.400 99.950 134.200 ;
        RECT 100.550 133.400 100.950 134.200 ;
        RECT 101.450 133.400 101.850 134.200 ;
        RECT 102.350 133.400 102.750 134.200 ;
        RECT 103.250 133.400 103.650 134.200 ;
        RECT 107.550 133.400 107.950 134.200 ;
        RECT 108.450 133.400 108.850 134.200 ;
        RECT 109.350 133.400 109.750 134.200 ;
        RECT 110.250 133.400 110.650 134.200 ;
        RECT 111.250 133.400 111.650 134.200 ;
        RECT 112.150 133.400 112.550 134.200 ;
        RECT 113.050 133.400 113.450 134.200 ;
        RECT 113.950 133.400 114.350 134.200 ;
        RECT 36.850 132.700 37.250 133.100 ;
        RECT 37.550 132.700 37.750 133.400 ;
        RECT 35.950 132.300 36.350 132.700 ;
        RECT 35.050 131.800 35.450 132.200 ;
        RECT 37.550 132.100 38.150 132.700 ;
        RECT 39.650 132.300 40.050 132.700 ;
        RECT 40.450 132.600 41.050 133.200 ;
        RECT 41.250 132.700 41.450 133.400 ;
        RECT 45.450 132.700 45.850 133.100 ;
        RECT 46.150 132.700 46.350 133.400 ;
        RECT 37.550 132.000 37.750 132.100 ;
        RECT 35.750 131.800 37.750 132.000 ;
        RECT 38.750 131.800 39.150 132.200 ;
        RECT 41.250 132.100 41.850 132.700 ;
        RECT 44.550 132.300 44.950 132.700 ;
        RECT 41.250 132.000 41.450 132.100 ;
        RECT 39.450 131.800 41.450 132.000 ;
        RECT 43.650 131.800 44.050 132.200 ;
        RECT 46.150 132.100 46.750 132.700 ;
        RECT 48.250 132.300 48.650 132.700 ;
        RECT 49.050 132.600 49.650 133.200 ;
        RECT 49.850 132.700 50.050 133.400 ;
        RECT 56.150 132.700 56.550 133.100 ;
        RECT 56.850 132.700 57.050 133.400 ;
        RECT 46.150 132.000 46.350 132.100 ;
        RECT 44.350 131.800 46.350 132.000 ;
        RECT 47.350 131.800 47.750 132.200 ;
        RECT 49.850 132.100 50.450 132.700 ;
        RECT 55.250 132.300 55.650 132.700 ;
        RECT 49.850 132.000 50.050 132.100 ;
        RECT 48.050 131.800 50.050 132.000 ;
        RECT 54.350 131.800 54.750 132.200 ;
        RECT 56.850 132.100 57.450 132.700 ;
        RECT 58.950 132.300 59.350 132.700 ;
        RECT 59.750 132.600 60.350 133.200 ;
        RECT 60.550 132.700 60.750 133.400 ;
        RECT 66.850 132.700 67.250 133.100 ;
        RECT 67.550 132.700 67.750 133.400 ;
        RECT 56.850 132.000 57.050 132.100 ;
        RECT 55.050 131.800 57.050 132.000 ;
        RECT 58.050 131.800 58.450 132.200 ;
        RECT 60.550 132.100 61.150 132.700 ;
        RECT 65.950 132.300 66.350 132.700 ;
        RECT 60.550 132.000 60.750 132.100 ;
        RECT 58.750 131.800 60.750 132.000 ;
        RECT 65.050 131.800 65.450 132.200 ;
        RECT 67.550 132.100 68.150 132.700 ;
        RECT 69.650 132.300 70.050 132.700 ;
        RECT 70.450 132.600 71.050 133.200 ;
        RECT 71.250 132.700 71.450 133.400 ;
        RECT 77.550 132.700 77.950 133.100 ;
        RECT 78.250 132.700 78.450 133.400 ;
        RECT 67.550 132.000 67.750 132.100 ;
        RECT 65.750 131.800 67.750 132.000 ;
        RECT 68.750 131.800 69.150 132.200 ;
        RECT 71.250 132.100 71.850 132.700 ;
        RECT 76.650 132.300 77.050 132.700 ;
        RECT 71.250 132.000 71.450 132.100 ;
        RECT 69.450 131.800 71.450 132.000 ;
        RECT 75.750 131.800 76.150 132.200 ;
        RECT 78.250 132.100 78.850 132.700 ;
        RECT 80.350 132.300 80.750 132.700 ;
        RECT 81.150 132.600 81.750 133.200 ;
        RECT 81.950 132.700 82.150 133.400 ;
        RECT 88.250 132.700 88.650 133.100 ;
        RECT 88.950 132.700 89.150 133.400 ;
        RECT 78.250 132.000 78.450 132.100 ;
        RECT 76.450 131.800 78.450 132.000 ;
        RECT 79.450 131.800 79.850 132.200 ;
        RECT 81.950 132.100 82.550 132.700 ;
        RECT 87.350 132.300 87.750 132.700 ;
        RECT 81.950 132.000 82.150 132.100 ;
        RECT 80.150 131.800 82.150 132.000 ;
        RECT 86.450 131.800 86.850 132.200 ;
        RECT 88.950 132.100 89.550 132.700 ;
        RECT 91.050 132.300 91.450 132.700 ;
        RECT 91.850 132.600 92.450 133.200 ;
        RECT 92.650 132.700 92.850 133.400 ;
        RECT 98.950 132.700 99.350 133.100 ;
        RECT 99.650 132.700 99.850 133.400 ;
        RECT 88.950 132.000 89.150 132.100 ;
        RECT 87.150 131.800 89.150 132.000 ;
        RECT 90.150 131.800 90.550 132.200 ;
        RECT 92.650 132.100 93.250 132.700 ;
        RECT 98.050 132.300 98.450 132.700 ;
        RECT 92.650 132.000 92.850 132.100 ;
        RECT 90.850 131.800 92.850 132.000 ;
        RECT 97.150 131.800 97.550 132.200 ;
        RECT 99.650 132.100 100.250 132.700 ;
        RECT 101.750 132.300 102.150 132.700 ;
        RECT 102.550 132.600 103.150 133.200 ;
        RECT 103.350 132.700 103.550 133.400 ;
        RECT 109.650 132.700 110.050 133.100 ;
        RECT 110.350 132.700 110.550 133.400 ;
        RECT 99.650 132.000 99.850 132.100 ;
        RECT 97.850 131.800 99.850 132.000 ;
        RECT 100.850 131.800 101.250 132.200 ;
        RECT 103.350 132.100 103.950 132.700 ;
        RECT 108.750 132.300 109.150 132.700 ;
        RECT 103.350 132.000 103.550 132.100 ;
        RECT 101.550 131.800 103.550 132.000 ;
        RECT 107.850 131.800 108.250 132.200 ;
        RECT 110.350 132.100 110.950 132.700 ;
        RECT 112.450 132.300 112.850 132.700 ;
        RECT 113.250 132.600 113.850 133.200 ;
        RECT 114.050 132.700 114.250 133.400 ;
        RECT 110.350 132.000 110.550 132.100 ;
        RECT 108.550 131.800 110.550 132.000 ;
        RECT 111.550 131.800 111.950 132.200 ;
        RECT 114.050 132.100 114.650 132.700 ;
        RECT 114.050 132.000 114.250 132.100 ;
        RECT 112.250 131.800 114.250 132.000 ;
        RECT 35.750 131.400 35.950 131.800 ;
        RECT 37.550 131.400 37.750 131.800 ;
        RECT 39.450 131.400 39.650 131.800 ;
        RECT 41.250 131.400 41.450 131.800 ;
        RECT 44.350 131.400 44.550 131.800 ;
        RECT 46.150 131.400 46.350 131.800 ;
        RECT 48.050 131.400 48.250 131.800 ;
        RECT 49.850 131.400 50.050 131.800 ;
        RECT 55.050 131.400 55.250 131.800 ;
        RECT 56.850 131.400 57.050 131.800 ;
        RECT 58.750 131.400 58.950 131.800 ;
        RECT 60.550 131.400 60.750 131.800 ;
        RECT 65.750 131.400 65.950 131.800 ;
        RECT 67.550 131.400 67.750 131.800 ;
        RECT 69.450 131.400 69.650 131.800 ;
        RECT 71.250 131.400 71.450 131.800 ;
        RECT 76.450 131.400 76.650 131.800 ;
        RECT 78.250 131.400 78.450 131.800 ;
        RECT 80.150 131.400 80.350 131.800 ;
        RECT 81.950 131.400 82.150 131.800 ;
        RECT 87.150 131.400 87.350 131.800 ;
        RECT 88.950 131.400 89.150 131.800 ;
        RECT 90.850 131.400 91.050 131.800 ;
        RECT 92.650 131.400 92.850 131.800 ;
        RECT 97.850 131.400 98.050 131.800 ;
        RECT 99.650 131.400 99.850 131.800 ;
        RECT 101.550 131.400 101.750 131.800 ;
        RECT 103.350 131.400 103.550 131.800 ;
        RECT 108.550 131.400 108.750 131.800 ;
        RECT 110.350 131.400 110.550 131.800 ;
        RECT 112.250 131.400 112.450 131.800 ;
        RECT 114.050 131.400 114.250 131.800 ;
        RECT 34.750 130.100 35.150 131.400 ;
        RECT 35.650 130.100 36.050 131.400 ;
        RECT 36.550 130.100 36.950 131.400 ;
        RECT 37.450 130.100 37.850 131.400 ;
        RECT 38.450 130.100 38.850 131.400 ;
        RECT 39.350 130.100 39.750 131.400 ;
        RECT 40.250 130.100 40.650 131.400 ;
        RECT 41.150 130.100 41.550 131.400 ;
        RECT 43.350 130.100 43.750 131.400 ;
        RECT 44.250 130.100 44.650 131.400 ;
        RECT 45.150 130.100 45.550 131.400 ;
        RECT 46.050 130.100 46.450 131.400 ;
        RECT 47.050 130.100 47.450 131.400 ;
        RECT 47.950 130.100 48.350 131.400 ;
        RECT 48.850 130.100 49.250 131.400 ;
        RECT 49.750 130.100 50.150 131.400 ;
        RECT 54.050 130.100 54.450 131.400 ;
        RECT 54.950 130.100 55.350 131.400 ;
        RECT 55.850 130.100 56.250 131.400 ;
        RECT 56.750 130.100 57.150 131.400 ;
        RECT 57.750 130.100 58.150 131.400 ;
        RECT 58.650 130.100 59.050 131.400 ;
        RECT 59.550 130.100 59.950 131.400 ;
        RECT 60.450 130.100 60.850 131.400 ;
        RECT 64.750 130.100 65.150 131.400 ;
        RECT 65.650 130.100 66.050 131.400 ;
        RECT 66.550 130.100 66.950 131.400 ;
        RECT 67.450 130.100 67.850 131.400 ;
        RECT 68.450 130.100 68.850 131.400 ;
        RECT 69.350 130.100 69.750 131.400 ;
        RECT 70.250 130.100 70.650 131.400 ;
        RECT 71.150 130.100 71.550 131.400 ;
        RECT 75.450 130.100 75.850 131.400 ;
        RECT 76.350 130.100 76.750 131.400 ;
        RECT 77.250 130.100 77.650 131.400 ;
        RECT 78.150 130.100 78.550 131.400 ;
        RECT 79.150 130.100 79.550 131.400 ;
        RECT 80.050 130.100 80.450 131.400 ;
        RECT 80.950 130.100 81.350 131.400 ;
        RECT 81.850 130.100 82.250 131.400 ;
        RECT 86.150 130.100 86.550 131.400 ;
        RECT 87.050 130.100 87.450 131.400 ;
        RECT 87.950 130.100 88.350 131.400 ;
        RECT 88.850 130.100 89.250 131.400 ;
        RECT 89.850 130.100 90.250 131.400 ;
        RECT 90.750 130.100 91.150 131.400 ;
        RECT 91.650 130.100 92.050 131.400 ;
        RECT 92.550 130.100 92.950 131.400 ;
        RECT 96.850 130.100 97.250 131.400 ;
        RECT 97.750 130.100 98.150 131.400 ;
        RECT 98.650 130.100 99.050 131.400 ;
        RECT 99.550 130.100 99.950 131.400 ;
        RECT 100.550 130.100 100.950 131.400 ;
        RECT 101.450 130.100 101.850 131.400 ;
        RECT 102.350 130.100 102.750 131.400 ;
        RECT 103.250 130.100 103.650 131.400 ;
        RECT 107.550 130.100 107.950 131.400 ;
        RECT 108.450 130.100 108.850 131.400 ;
        RECT 109.350 130.100 109.750 131.400 ;
        RECT 110.250 130.100 110.650 131.400 ;
        RECT 111.250 130.100 111.650 131.400 ;
        RECT 112.150 130.100 112.550 131.400 ;
        RECT 113.050 130.100 113.450 131.400 ;
        RECT 113.950 130.100 114.350 131.400 ;
        RECT 34.850 129.500 35.050 130.100 ;
        RECT 36.650 129.500 36.850 130.100 ;
        RECT 38.550 129.500 38.750 130.100 ;
        RECT 40.350 129.500 40.550 130.100 ;
        RECT 43.450 129.500 43.650 130.100 ;
        RECT 45.250 129.500 45.450 130.100 ;
        RECT 47.150 129.500 47.350 130.100 ;
        RECT 48.950 129.500 49.150 130.100 ;
        RECT 54.150 129.500 54.350 130.100 ;
        RECT 55.950 129.500 56.150 130.100 ;
        RECT 57.850 129.500 58.050 130.100 ;
        RECT 59.650 129.500 59.850 130.100 ;
        RECT 64.850 129.500 65.050 130.100 ;
        RECT 66.650 129.500 66.850 130.100 ;
        RECT 68.550 129.500 68.750 130.100 ;
        RECT 70.350 129.500 70.550 130.100 ;
        RECT 75.550 129.500 75.750 130.100 ;
        RECT 77.350 129.500 77.550 130.100 ;
        RECT 79.250 129.500 79.450 130.100 ;
        RECT 81.050 129.500 81.250 130.100 ;
        RECT 86.250 129.500 86.450 130.100 ;
        RECT 88.050 129.500 88.250 130.100 ;
        RECT 89.950 129.500 90.150 130.100 ;
        RECT 91.750 129.500 91.950 130.100 ;
        RECT 96.950 129.500 97.150 130.100 ;
        RECT 98.750 129.500 98.950 130.100 ;
        RECT 100.650 129.500 100.850 130.100 ;
        RECT 102.450 129.500 102.650 130.100 ;
        RECT 107.650 129.500 107.850 130.100 ;
        RECT 109.450 129.500 109.650 130.100 ;
        RECT 111.350 129.500 111.550 130.100 ;
        RECT 113.150 129.500 113.350 130.100 ;
        RECT 34.250 128.300 114.650 129.500 ;
        RECT 34.850 127.700 35.050 128.300 ;
        RECT 36.650 127.700 36.850 128.300 ;
        RECT 38.550 127.700 38.750 128.300 ;
        RECT 40.350 127.700 40.550 128.300 ;
        RECT 43.450 127.700 43.650 128.300 ;
        RECT 45.250 127.700 45.450 128.300 ;
        RECT 47.150 127.700 47.350 128.300 ;
        RECT 48.950 127.700 49.150 128.300 ;
        RECT 54.150 127.700 54.350 128.300 ;
        RECT 55.950 127.700 56.150 128.300 ;
        RECT 57.850 127.700 58.050 128.300 ;
        RECT 59.650 127.700 59.850 128.300 ;
        RECT 64.850 127.700 65.050 128.300 ;
        RECT 66.650 127.700 66.850 128.300 ;
        RECT 68.550 127.700 68.750 128.300 ;
        RECT 70.350 127.700 70.550 128.300 ;
        RECT 75.550 127.700 75.750 128.300 ;
        RECT 77.350 127.700 77.550 128.300 ;
        RECT 79.250 127.700 79.450 128.300 ;
        RECT 81.050 127.700 81.250 128.300 ;
        RECT 86.250 127.700 86.450 128.300 ;
        RECT 88.050 127.700 88.250 128.300 ;
        RECT 89.950 127.700 90.150 128.300 ;
        RECT 91.750 127.700 91.950 128.300 ;
        RECT 96.950 127.700 97.150 128.300 ;
        RECT 98.750 127.700 98.950 128.300 ;
        RECT 100.650 127.700 100.850 128.300 ;
        RECT 102.450 127.700 102.650 128.300 ;
        RECT 107.650 127.700 107.850 128.300 ;
        RECT 109.450 127.700 109.650 128.300 ;
        RECT 111.350 127.700 111.550 128.300 ;
        RECT 113.150 127.700 113.350 128.300 ;
        RECT 34.750 126.400 35.150 127.700 ;
        RECT 35.650 126.400 36.050 127.700 ;
        RECT 36.550 126.400 36.950 127.700 ;
        RECT 37.450 126.400 37.850 127.700 ;
        RECT 38.450 126.400 38.850 127.700 ;
        RECT 39.350 126.400 39.750 127.700 ;
        RECT 40.250 126.400 40.650 127.700 ;
        RECT 41.150 126.400 41.550 127.700 ;
        RECT 43.350 126.400 43.750 127.700 ;
        RECT 44.250 126.400 44.650 127.700 ;
        RECT 45.150 126.400 45.550 127.700 ;
        RECT 46.050 126.400 46.450 127.700 ;
        RECT 47.050 126.400 47.450 127.700 ;
        RECT 47.950 126.400 48.350 127.700 ;
        RECT 48.850 126.400 49.250 127.700 ;
        RECT 49.750 126.400 50.150 127.700 ;
        RECT 54.050 126.400 54.450 127.700 ;
        RECT 54.950 126.400 55.350 127.700 ;
        RECT 55.850 126.400 56.250 127.700 ;
        RECT 56.750 126.400 57.150 127.700 ;
        RECT 57.750 126.400 58.150 127.700 ;
        RECT 58.650 126.400 59.050 127.700 ;
        RECT 59.550 126.400 59.950 127.700 ;
        RECT 60.450 126.400 60.850 127.700 ;
        RECT 64.750 126.400 65.150 127.700 ;
        RECT 65.650 126.400 66.050 127.700 ;
        RECT 66.550 126.400 66.950 127.700 ;
        RECT 67.450 126.400 67.850 127.700 ;
        RECT 68.450 126.400 68.850 127.700 ;
        RECT 69.350 126.400 69.750 127.700 ;
        RECT 70.250 126.400 70.650 127.700 ;
        RECT 71.150 126.400 71.550 127.700 ;
        RECT 75.450 126.400 75.850 127.700 ;
        RECT 76.350 126.400 76.750 127.700 ;
        RECT 77.250 126.400 77.650 127.700 ;
        RECT 78.150 126.400 78.550 127.700 ;
        RECT 79.150 126.400 79.550 127.700 ;
        RECT 80.050 126.400 80.450 127.700 ;
        RECT 80.950 126.400 81.350 127.700 ;
        RECT 81.850 126.400 82.250 127.700 ;
        RECT 86.150 126.400 86.550 127.700 ;
        RECT 87.050 126.400 87.450 127.700 ;
        RECT 87.950 126.400 88.350 127.700 ;
        RECT 88.850 126.400 89.250 127.700 ;
        RECT 89.850 126.400 90.250 127.700 ;
        RECT 90.750 126.400 91.150 127.700 ;
        RECT 91.650 126.400 92.050 127.700 ;
        RECT 92.550 126.400 92.950 127.700 ;
        RECT 96.850 126.400 97.250 127.700 ;
        RECT 97.750 126.400 98.150 127.700 ;
        RECT 98.650 126.400 99.050 127.700 ;
        RECT 99.550 126.400 99.950 127.700 ;
        RECT 100.550 126.400 100.950 127.700 ;
        RECT 101.450 126.400 101.850 127.700 ;
        RECT 102.350 126.400 102.750 127.700 ;
        RECT 103.250 126.400 103.650 127.700 ;
        RECT 107.550 126.400 107.950 127.700 ;
        RECT 108.450 126.400 108.850 127.700 ;
        RECT 109.350 126.400 109.750 127.700 ;
        RECT 110.250 126.400 110.650 127.700 ;
        RECT 111.250 126.400 111.650 127.700 ;
        RECT 112.150 126.400 112.550 127.700 ;
        RECT 113.050 126.400 113.450 127.700 ;
        RECT 113.950 126.400 114.350 127.700 ;
        RECT 34.950 125.500 35.550 126.100 ;
        RECT 35.750 126.000 35.950 126.400 ;
        RECT 37.550 126.000 37.750 126.400 ;
        RECT 39.450 126.000 39.650 126.400 ;
        RECT 41.250 126.000 41.450 126.400 ;
        RECT 35.750 125.800 37.750 126.000 ;
        RECT 37.550 125.700 37.750 125.800 ;
        RECT 35.850 125.000 36.450 125.600 ;
        RECT 37.550 125.100 38.150 125.700 ;
        RECT 38.750 125.600 39.150 126.000 ;
        RECT 39.450 125.800 41.450 126.000 ;
        RECT 41.250 125.700 41.450 125.800 ;
        RECT 36.850 124.700 37.250 125.100 ;
        RECT 37.550 124.400 37.750 125.100 ;
        RECT 39.550 125.000 40.150 125.600 ;
        RECT 41.250 125.100 41.850 125.700 ;
        RECT 43.550 125.500 44.150 126.100 ;
        RECT 44.350 126.000 44.550 126.400 ;
        RECT 46.150 126.000 46.350 126.400 ;
        RECT 48.050 126.000 48.250 126.400 ;
        RECT 49.850 126.000 50.050 126.400 ;
        RECT 44.350 125.800 46.350 126.000 ;
        RECT 46.150 125.700 46.350 125.800 ;
        RECT 40.550 124.700 40.950 125.100 ;
        RECT 41.250 124.400 41.450 125.100 ;
        RECT 44.450 125.000 45.050 125.600 ;
        RECT 46.150 125.100 46.750 125.700 ;
        RECT 47.350 125.600 47.750 126.000 ;
        RECT 48.050 125.800 50.050 126.000 ;
        RECT 49.850 125.700 50.050 125.800 ;
        RECT 45.450 124.700 45.850 125.100 ;
        RECT 46.150 124.400 46.350 125.100 ;
        RECT 48.150 125.000 48.750 125.600 ;
        RECT 49.850 125.100 50.450 125.700 ;
        RECT 54.250 125.500 54.850 126.100 ;
        RECT 55.050 126.000 55.250 126.400 ;
        RECT 56.850 126.000 57.050 126.400 ;
        RECT 58.750 126.000 58.950 126.400 ;
        RECT 60.550 126.000 60.750 126.400 ;
        RECT 55.050 125.800 57.050 126.000 ;
        RECT 56.850 125.700 57.050 125.800 ;
        RECT 49.150 124.700 49.550 125.100 ;
        RECT 49.850 124.400 50.050 125.100 ;
        RECT 55.150 125.000 55.750 125.600 ;
        RECT 56.850 125.100 57.450 125.700 ;
        RECT 58.050 125.600 58.450 126.000 ;
        RECT 58.750 125.800 60.750 126.000 ;
        RECT 60.550 125.700 60.750 125.800 ;
        RECT 56.150 124.700 56.550 125.100 ;
        RECT 56.850 124.400 57.050 125.100 ;
        RECT 58.850 125.000 59.450 125.600 ;
        RECT 60.550 125.100 61.150 125.700 ;
        RECT 64.950 125.500 65.550 126.100 ;
        RECT 65.750 126.000 65.950 126.400 ;
        RECT 67.550 126.000 67.750 126.400 ;
        RECT 69.450 126.000 69.650 126.400 ;
        RECT 71.250 126.000 71.450 126.400 ;
        RECT 65.750 125.800 67.750 126.000 ;
        RECT 67.550 125.700 67.750 125.800 ;
        RECT 59.850 124.700 60.250 125.100 ;
        RECT 60.550 124.400 60.750 125.100 ;
        RECT 65.850 125.000 66.450 125.600 ;
        RECT 67.550 125.100 68.150 125.700 ;
        RECT 68.750 125.600 69.150 126.000 ;
        RECT 69.450 125.800 71.450 126.000 ;
        RECT 71.250 125.700 71.450 125.800 ;
        RECT 66.850 124.700 67.250 125.100 ;
        RECT 67.550 124.400 67.750 125.100 ;
        RECT 69.550 125.000 70.150 125.600 ;
        RECT 71.250 125.100 71.850 125.700 ;
        RECT 75.650 125.500 76.250 126.100 ;
        RECT 76.450 126.000 76.650 126.400 ;
        RECT 78.250 126.000 78.450 126.400 ;
        RECT 80.150 126.000 80.350 126.400 ;
        RECT 81.950 126.000 82.150 126.400 ;
        RECT 76.450 125.800 78.450 126.000 ;
        RECT 78.250 125.700 78.450 125.800 ;
        RECT 70.550 124.700 70.950 125.100 ;
        RECT 71.250 124.400 71.450 125.100 ;
        RECT 76.550 125.000 77.150 125.600 ;
        RECT 78.250 125.100 78.850 125.700 ;
        RECT 79.450 125.600 79.850 126.000 ;
        RECT 80.150 125.800 82.150 126.000 ;
        RECT 81.950 125.700 82.150 125.800 ;
        RECT 77.550 124.700 77.950 125.100 ;
        RECT 78.250 124.400 78.450 125.100 ;
        RECT 80.250 125.000 80.850 125.600 ;
        RECT 81.950 125.100 82.550 125.700 ;
        RECT 86.350 125.500 86.950 126.100 ;
        RECT 87.150 126.000 87.350 126.400 ;
        RECT 88.950 126.000 89.150 126.400 ;
        RECT 90.850 126.000 91.050 126.400 ;
        RECT 92.650 126.000 92.850 126.400 ;
        RECT 87.150 125.800 89.150 126.000 ;
        RECT 88.950 125.700 89.150 125.800 ;
        RECT 81.250 124.700 81.650 125.100 ;
        RECT 81.950 124.400 82.150 125.100 ;
        RECT 87.250 125.000 87.850 125.600 ;
        RECT 88.950 125.100 89.550 125.700 ;
        RECT 90.150 125.600 90.550 126.000 ;
        RECT 90.850 125.800 92.850 126.000 ;
        RECT 92.650 125.700 92.850 125.800 ;
        RECT 88.250 124.700 88.650 125.100 ;
        RECT 88.950 124.400 89.150 125.100 ;
        RECT 90.950 125.000 91.550 125.600 ;
        RECT 92.650 125.100 93.250 125.700 ;
        RECT 97.050 125.500 97.650 126.100 ;
        RECT 97.850 126.000 98.050 126.400 ;
        RECT 99.650 126.000 99.850 126.400 ;
        RECT 101.550 126.000 101.750 126.400 ;
        RECT 103.350 126.000 103.550 126.400 ;
        RECT 97.850 125.800 99.850 126.000 ;
        RECT 99.650 125.700 99.850 125.800 ;
        RECT 91.950 124.700 92.350 125.100 ;
        RECT 92.650 124.400 92.850 125.100 ;
        RECT 97.950 125.000 98.550 125.600 ;
        RECT 99.650 125.100 100.250 125.700 ;
        RECT 100.850 125.600 101.250 126.000 ;
        RECT 101.550 125.800 103.550 126.000 ;
        RECT 103.350 125.700 103.550 125.800 ;
        RECT 98.950 124.700 99.350 125.100 ;
        RECT 99.650 124.400 99.850 125.100 ;
        RECT 101.650 125.000 102.250 125.600 ;
        RECT 103.350 125.100 103.950 125.700 ;
        RECT 107.750 125.500 108.350 126.100 ;
        RECT 108.550 126.000 108.750 126.400 ;
        RECT 110.350 126.000 110.550 126.400 ;
        RECT 112.250 126.000 112.450 126.400 ;
        RECT 114.050 126.000 114.250 126.400 ;
        RECT 108.550 125.800 110.550 126.000 ;
        RECT 110.350 125.700 110.550 125.800 ;
        RECT 102.650 124.700 103.050 125.100 ;
        RECT 103.350 124.400 103.550 125.100 ;
        RECT 108.650 125.000 109.250 125.600 ;
        RECT 110.350 125.100 110.950 125.700 ;
        RECT 111.550 125.600 111.950 126.000 ;
        RECT 112.250 125.800 114.250 126.000 ;
        RECT 114.050 125.700 114.250 125.800 ;
        RECT 109.650 124.700 110.050 125.100 ;
        RECT 110.350 124.400 110.550 125.100 ;
        RECT 112.350 125.000 112.950 125.600 ;
        RECT 114.050 125.100 114.650 125.700 ;
        RECT 113.350 124.700 113.750 125.100 ;
        RECT 114.050 124.400 114.250 125.100 ;
        RECT 34.750 123.600 35.150 124.400 ;
        RECT 35.650 123.600 36.050 124.400 ;
        RECT 36.550 123.600 36.950 124.400 ;
        RECT 37.450 123.600 37.850 124.400 ;
        RECT 38.450 123.600 38.850 124.400 ;
        RECT 39.350 123.600 39.750 124.400 ;
        RECT 40.250 123.600 40.650 124.400 ;
        RECT 41.150 123.600 41.550 124.400 ;
        RECT 43.350 123.600 43.750 124.400 ;
        RECT 44.250 123.600 44.650 124.400 ;
        RECT 45.150 123.600 45.550 124.400 ;
        RECT 46.050 123.600 46.450 124.400 ;
        RECT 47.050 123.600 47.450 124.400 ;
        RECT 47.950 123.600 48.350 124.400 ;
        RECT 48.850 123.600 49.250 124.400 ;
        RECT 49.750 123.600 50.150 124.400 ;
        RECT 54.050 123.600 54.450 124.400 ;
        RECT 54.950 123.600 55.350 124.400 ;
        RECT 55.850 123.600 56.250 124.400 ;
        RECT 56.750 123.600 57.150 124.400 ;
        RECT 57.750 123.600 58.150 124.400 ;
        RECT 58.650 123.600 59.050 124.400 ;
        RECT 59.550 123.600 59.950 124.400 ;
        RECT 60.450 123.600 60.850 124.400 ;
        RECT 64.750 123.600 65.150 124.400 ;
        RECT 65.650 123.600 66.050 124.400 ;
        RECT 66.550 123.600 66.950 124.400 ;
        RECT 67.450 123.600 67.850 124.400 ;
        RECT 68.450 123.600 68.850 124.400 ;
        RECT 69.350 123.600 69.750 124.400 ;
        RECT 70.250 123.600 70.650 124.400 ;
        RECT 71.150 123.600 71.550 124.400 ;
        RECT 75.450 123.600 75.850 124.400 ;
        RECT 76.350 123.600 76.750 124.400 ;
        RECT 77.250 123.600 77.650 124.400 ;
        RECT 78.150 123.600 78.550 124.400 ;
        RECT 79.150 123.600 79.550 124.400 ;
        RECT 80.050 123.600 80.450 124.400 ;
        RECT 80.950 123.600 81.350 124.400 ;
        RECT 81.850 123.600 82.250 124.400 ;
        RECT 86.150 123.600 86.550 124.400 ;
        RECT 87.050 123.600 87.450 124.400 ;
        RECT 87.950 123.600 88.350 124.400 ;
        RECT 88.850 123.600 89.250 124.400 ;
        RECT 89.850 123.600 90.250 124.400 ;
        RECT 90.750 123.600 91.150 124.400 ;
        RECT 91.650 123.600 92.050 124.400 ;
        RECT 92.550 123.600 92.950 124.400 ;
        RECT 96.850 123.600 97.250 124.400 ;
        RECT 97.750 123.600 98.150 124.400 ;
        RECT 98.650 123.600 99.050 124.400 ;
        RECT 99.550 123.600 99.950 124.400 ;
        RECT 100.550 123.600 100.950 124.400 ;
        RECT 101.450 123.600 101.850 124.400 ;
        RECT 102.350 123.600 102.750 124.400 ;
        RECT 103.250 123.600 103.650 124.400 ;
        RECT 107.550 123.600 107.950 124.400 ;
        RECT 108.450 123.600 108.850 124.400 ;
        RECT 109.350 123.600 109.750 124.400 ;
        RECT 110.250 123.600 110.650 124.400 ;
        RECT 111.250 123.600 111.650 124.400 ;
        RECT 112.150 123.600 112.550 124.400 ;
        RECT 113.050 123.600 113.450 124.400 ;
        RECT 113.950 123.600 114.350 124.400 ;
        RECT 34.850 123.000 35.050 123.600 ;
        RECT 38.550 123.000 38.750 123.600 ;
        RECT 43.450 123.000 43.650 123.600 ;
        RECT 47.150 123.000 47.350 123.600 ;
        RECT 54.150 123.000 54.350 123.600 ;
        RECT 57.850 123.000 58.050 123.600 ;
        RECT 64.850 123.000 65.050 123.600 ;
        RECT 68.550 123.000 68.750 123.600 ;
        RECT 75.550 123.000 75.750 123.600 ;
        RECT 79.250 123.000 79.450 123.600 ;
        RECT 86.250 123.000 86.450 123.600 ;
        RECT 89.950 123.000 90.150 123.600 ;
        RECT 96.950 123.000 97.150 123.600 ;
        RECT 100.650 123.000 100.850 123.600 ;
        RECT 107.650 123.000 107.850 123.600 ;
        RECT 111.350 123.000 111.550 123.600 ;
        RECT 34.250 121.800 114.650 123.000 ;
        RECT 94.900 91.900 110.700 93.000 ;
        RECT 46.200 88.250 56.400 89.700 ;
        RECT 46.850 87.550 47.650 88.250 ;
        RECT 48.950 87.550 49.750 88.250 ;
        RECT 50.950 87.550 51.750 88.250 ;
        RECT 52.950 87.550 53.750 88.250 ;
        RECT 55.150 87.550 55.950 88.250 ;
        RECT 62.950 88.050 64.150 89.350 ;
        RECT 68.800 87.750 70.000 89.050 ;
        RECT 74.600 87.950 75.800 89.250 ;
        RECT 94.900 87.250 96.300 91.900 ;
        RECT 99.900 90.600 100.300 91.000 ;
        RECT 100.500 90.300 100.800 91.900 ;
        RECT 56.250 86.250 56.950 86.950 ;
        RECT 91.050 85.900 96.300 87.250 ;
        RECT 91.050 85.850 94.450 85.900 ;
        RECT 55.150 84.950 55.950 85.350 ;
        RECT 53.950 83.950 54.650 84.650 ;
        RECT 52.950 83.450 53.750 83.850 ;
        RECT 51.950 81.950 52.650 82.650 ;
        RECT 50.950 80.450 51.750 80.850 ;
        RECT 38.300 79.400 40.350 80.100 ;
        RECT 35.750 72.000 36.950 73.300 ;
        RECT 35.800 68.100 37.000 69.400 ;
        RECT 38.050 66.050 38.450 78.600 ;
        RECT 37.050 64.800 38.450 66.050 ;
        RECT 35.100 61.450 36.300 62.750 ;
        RECT 35.250 58.350 36.450 59.650 ;
        RECT 35.500 55.000 36.700 56.300 ;
        RECT 38.050 54.500 38.450 64.800 ;
        RECT 38.850 65.600 39.250 78.600 ;
        RECT 39.900 74.200 40.350 79.400 ;
        RECT 49.850 79.250 50.550 79.950 ;
        RECT 51.250 79.850 51.750 80.450 ;
        RECT 53.050 80.150 53.650 83.450 ;
        RECT 51.250 79.450 52.400 79.850 ;
        RECT 53.050 79.450 54.100 80.150 ;
        RECT 41.700 77.700 43.250 78.700 ;
        RECT 41.800 74.200 42.200 76.950 ;
        RECT 42.600 74.650 43.000 77.700 ;
        RECT 44.550 77.400 45.750 78.700 ;
        RECT 51.900 78.400 52.400 79.450 ;
        RECT 53.500 78.400 54.100 79.450 ;
        RECT 55.250 78.900 55.850 84.950 ;
        RECT 67.750 81.050 72.150 82.050 ;
        RECT 68.150 80.350 68.350 81.050 ;
        RECT 69.950 80.350 70.150 81.050 ;
        RECT 76.100 80.900 77.300 82.200 ;
        RECT 79.000 81.650 79.700 82.350 ;
        RECT 84.600 82.050 86.200 84.100 ;
        RECT 90.250 81.800 90.650 83.600 ;
        RECT 91.050 82.700 91.450 85.850 ;
        RECT 91.150 82.600 91.450 82.700 ;
        RECT 90.950 81.950 91.400 82.400 ;
        RECT 94.050 81.850 94.450 85.850 ;
        RECT 99.600 85.500 100.000 90.300 ;
        RECT 100.400 85.500 100.800 90.300 ;
        RECT 101.400 87.300 101.800 89.400 ;
        RECT 102.200 87.600 102.600 91.900 ;
        RECT 103.100 87.500 103.500 91.900 ;
        RECT 101.400 86.900 102.100 87.300 ;
        RECT 55.250 78.400 55.900 78.900 ;
        RECT 50.900 78.100 57.500 78.400 ;
        RECT 50.900 77.350 51.250 78.100 ;
        RECT 51.900 78.000 57.500 78.100 ;
        RECT 48.950 77.050 51.250 77.350 ;
        RECT 57.000 77.900 57.500 78.000 ;
        RECT 57.000 77.200 57.700 77.900 ;
        RECT 48.950 76.950 49.750 77.050 ;
        RECT 46.000 76.150 46.700 76.850 ;
        RECT 39.900 73.750 42.200 74.200 ;
        RECT 39.850 69.150 41.150 72.300 ;
        RECT 41.800 68.350 42.200 73.750 ;
        RECT 42.400 73.650 43.050 74.350 ;
        RECT 49.150 73.850 49.750 76.950 ;
        RECT 68.050 76.650 68.450 80.350 ;
        RECT 68.850 76.650 69.250 80.350 ;
        RECT 69.850 76.650 70.250 80.350 ;
        RECT 70.650 76.650 71.050 80.350 ;
        RECT 71.450 76.650 71.850 80.350 ;
        RECT 75.250 78.850 76.200 79.950 ;
        RECT 75.600 78.350 75.900 78.850 ;
        RECT 74.700 77.750 75.300 77.950 ;
        RECT 75.500 77.750 76.000 78.350 ;
        RECT 73.700 77.300 75.300 77.750 ;
        RECT 68.250 75.850 68.750 76.350 ;
        RECT 68.950 76.250 69.150 76.650 ;
        RECT 68.950 75.850 70.450 76.250 ;
        RECT 70.850 75.950 71.350 76.450 ;
        RECT 71.550 75.850 71.750 76.650 ;
        RECT 73.700 75.850 74.150 77.300 ;
        RECT 74.700 77.250 75.300 77.300 ;
        RECT 75.500 76.950 76.000 77.550 ;
        RECT 78.200 77.450 78.600 81.250 ;
        RECT 79.000 77.450 79.400 81.650 ;
        RECT 88.500 81.100 90.650 81.800 ;
        RECT 95.650 81.600 96.050 82.650 ;
        RECT 95.150 81.200 96.100 81.600 ;
        RECT 95.600 81.100 96.100 81.200 ;
        RECT 86.350 77.800 87.550 79.100 ;
        RECT 88.500 79.000 89.500 81.100 ;
        RECT 90.250 78.950 90.650 81.100 ;
        RECT 91.050 78.950 91.450 80.850 ;
        RECT 94.050 79.800 94.450 80.450 ;
        RECT 90.250 78.250 90.950 78.650 ;
        RECT 68.950 74.800 69.150 75.850 ;
        RECT 71.550 75.450 74.150 75.850 ;
        RECT 71.550 75.400 71.750 75.450 ;
        RECT 70.750 75.200 71.750 75.400 ;
        RECT 75.600 75.350 76.000 76.950 ;
        RECT 76.500 76.950 77.100 77.050 ;
        RECT 78.300 76.950 78.500 77.450 ;
        RECT 76.500 76.750 78.500 76.950 ;
        RECT 76.500 76.450 77.100 76.750 ;
        RECT 78.300 76.150 78.500 76.750 ;
        RECT 78.900 76.450 79.500 77.150 ;
        RECT 90.250 77.000 90.550 78.250 ;
        RECT 91.150 77.800 91.450 78.950 ;
        RECT 93.650 79.400 94.450 79.800 ;
        RECT 95.650 79.650 96.050 81.100 ;
        RECT 93.650 79.000 95.100 79.400 ;
        RECT 91.150 77.750 91.950 77.800 ;
        RECT 93.650 77.750 94.000 79.000 ;
        RECT 90.750 77.300 94.000 77.750 ;
        RECT 90.750 77.250 91.450 77.300 ;
        RECT 70.750 74.800 70.950 75.200 ;
        RECT 51.900 74.400 56.700 74.800 ;
        RECT 46.850 73.450 49.750 73.850 ;
        RECT 52.700 73.800 56.100 74.400 ;
        RECT 51.900 73.400 56.700 73.800 ;
        RECT 42.600 69.150 43.000 73.150 ;
        RECT 51.900 72.600 56.700 73.000 ;
        RECT 57.000 72.800 57.700 73.500 ;
        RECT 44.500 71.100 45.700 72.400 ;
        RECT 53.400 71.900 55.200 72.600 ;
        RECT 52.060 71.150 56.760 71.900 ;
        RECT 60.350 70.950 63.750 72.450 ;
        RECT 42.600 68.150 56.950 69.150 ;
        RECT 42.600 68.000 43.000 68.150 ;
        RECT 48.700 67.700 48.950 68.150 ;
        RECT 50.200 67.700 50.450 68.150 ;
        RECT 51.700 67.700 51.950 68.150 ;
        RECT 53.200 67.700 53.450 68.150 ;
        RECT 54.700 67.700 54.950 68.150 ;
        RECT 48.600 65.800 49.000 67.700 ;
        RECT 49.250 65.800 49.650 67.700 ;
        RECT 50.100 65.800 50.500 67.700 ;
        RECT 50.750 65.800 51.150 67.700 ;
        RECT 51.600 65.800 52.000 67.700 ;
        RECT 52.250 65.800 52.650 67.700 ;
        RECT 53.100 65.800 53.500 67.700 ;
        RECT 53.750 65.800 54.150 67.700 ;
        RECT 54.600 65.800 55.000 67.700 ;
        RECT 55.250 65.800 55.650 67.700 ;
        RECT 38.850 65.250 46.650 65.600 ;
        RECT 38.850 54.500 39.250 65.250 ;
        RECT 46.300 62.450 46.650 65.250 ;
        RECT 48.700 62.450 49.100 62.550 ;
        RECT 46.300 62.250 49.100 62.450 ;
        RECT 48.700 62.150 49.100 62.250 ;
        RECT 49.350 62.450 49.550 65.800 ;
        RECT 50.200 62.450 50.600 62.550 ;
        RECT 49.350 62.250 50.600 62.450 ;
        RECT 49.350 61.900 49.550 62.250 ;
        RECT 50.200 62.150 50.600 62.250 ;
        RECT 50.850 62.450 51.050 65.800 ;
        RECT 51.700 62.450 52.100 62.550 ;
        RECT 50.850 62.250 52.100 62.450 ;
        RECT 50.850 61.900 51.050 62.250 ;
        RECT 51.700 62.150 52.100 62.250 ;
        RECT 52.350 62.450 52.550 65.800 ;
        RECT 53.200 62.450 53.600 62.550 ;
        RECT 52.350 62.250 53.600 62.450 ;
        RECT 52.350 61.900 52.550 62.250 ;
        RECT 53.200 62.150 53.600 62.250 ;
        RECT 53.850 62.450 54.050 65.800 ;
        RECT 54.700 62.450 55.100 62.550 ;
        RECT 53.850 62.250 55.100 62.450 ;
        RECT 53.850 61.900 54.050 62.250 ;
        RECT 54.700 62.150 55.100 62.250 ;
        RECT 55.350 62.450 55.550 65.800 ;
        RECT 55.350 62.250 58.500 62.450 ;
        RECT 55.350 61.900 55.550 62.250 ;
        RECT 48.600 60.000 49.000 61.900 ;
        RECT 49.250 60.000 49.650 61.900 ;
        RECT 50.100 60.000 50.500 61.900 ;
        RECT 50.750 60.000 51.150 61.900 ;
        RECT 51.600 60.000 52.000 61.900 ;
        RECT 52.250 60.000 52.650 61.900 ;
        RECT 53.100 60.000 53.500 61.900 ;
        RECT 53.750 60.000 54.150 61.900 ;
        RECT 54.600 60.000 55.000 61.900 ;
        RECT 55.250 60.000 55.650 61.900 ;
        RECT 48.700 59.550 48.900 60.000 ;
        RECT 49.700 59.550 50.150 59.750 ;
        RECT 48.700 59.350 50.150 59.550 ;
        RECT 51.700 59.550 51.900 60.000 ;
        RECT 52.700 59.550 53.150 59.750 ;
        RECT 51.700 59.350 53.150 59.550 ;
        RECT 54.700 59.550 54.900 60.000 ;
        RECT 58.200 59.850 58.500 62.250 ;
        RECT 60.600 60.450 61.000 70.950 ;
        RECT 61.400 60.450 62.700 70.050 ;
        RECT 63.100 60.450 63.500 70.950 ;
        RECT 68.050 70.000 68.450 74.800 ;
        RECT 68.850 70.000 69.250 74.800 ;
        RECT 69.850 70.000 70.250 74.800 ;
        RECT 70.650 70.000 71.050 74.800 ;
        RECT 71.450 70.000 71.850 74.800 ;
        RECT 77.200 73.600 77.600 76.150 ;
        RECT 78.200 74.350 78.600 76.150 ;
        RECT 79.000 73.600 79.400 76.150 ;
        RECT 86.350 75.350 87.550 76.650 ;
        RECT 77.200 72.350 79.400 73.600 ;
        RECT 88.500 73.800 89.500 74.000 ;
        RECT 90.250 73.800 90.650 77.000 ;
        RECT 88.500 72.200 90.650 73.800 ;
        RECT 91.050 73.300 91.450 77.000 ;
        RECT 93.600 76.200 94.000 77.300 ;
        RECT 96.200 76.500 96.600 77.300 ;
        RECT 93.600 75.850 94.500 76.200 ;
        RECT 94.050 75.800 94.500 75.850 ;
        RECT 96.300 73.300 96.600 76.500 ;
        RECT 97.100 73.400 97.500 84.300 ;
        RECT 97.900 76.500 98.300 85.100 ;
        RECT 99.600 84.400 99.900 85.500 ;
        RECT 98.700 73.400 99.100 84.300 ;
        RECT 99.600 83.900 100.100 84.400 ;
        RECT 99.600 82.100 99.900 83.900 ;
        RECT 100.100 82.500 100.500 82.900 ;
        RECT 99.600 78.300 100.000 82.100 ;
        RECT 99.600 76.500 100.000 77.300 ;
        RECT 99.600 73.400 99.900 76.500 ;
        RECT 100.400 76.200 100.800 82.100 ;
        RECT 100.100 75.800 100.800 76.200 ;
        RECT 101.400 74.700 101.800 86.900 ;
        RECT 102.200 85.000 103.500 85.400 ;
        RECT 102.200 74.700 102.600 85.000 ;
        RECT 103.100 74.700 103.500 85.000 ;
        RECT 103.900 74.700 104.300 89.400 ;
        RECT 105.100 86.600 105.500 90.800 ;
        RECT 106.200 89.000 106.600 91.900 ;
        RECT 108.300 90.900 108.600 91.900 ;
        RECT 108.800 91.100 109.200 91.500 ;
        RECT 106.200 86.100 106.600 88.400 ;
        RECT 105.100 85.500 105.600 86.000 ;
        RECT 106.200 85.400 107.000 86.100 ;
        RECT 108.300 86.000 108.700 90.900 ;
        RECT 109.100 85.600 109.500 90.800 ;
        RECT 110.300 89.000 110.700 91.900 ;
        RECT 114.400 88.650 114.800 90.800 ;
        RECT 112.100 88.150 114.800 88.650 ;
        RECT 114.400 87.700 114.800 88.150 ;
        RECT 113.900 86.050 114.900 87.700 ;
        RECT 116.150 86.300 117.850 87.900 ;
        RECT 109.100 85.400 109.700 85.600 ;
        RECT 105.100 76.300 105.500 84.700 ;
        RECT 106.200 80.900 106.600 85.400 ;
        RECT 108.800 85.100 109.700 85.400 ;
        RECT 111.600 85.250 114.900 86.050 ;
        RECT 108.800 85.000 109.500 85.100 ;
        RECT 108.300 80.300 108.700 84.700 ;
        RECT 109.100 80.900 109.500 85.000 ;
        RECT 111.600 83.650 112.100 85.250 ;
        RECT 113.900 85.200 114.900 85.250 ;
        RECT 116.150 83.500 117.850 85.100 ;
        RECT 108.300 80.200 108.800 80.300 ;
        RECT 101.250 73.700 102.250 74.400 ;
        RECT 103.400 73.700 104.400 74.400 ;
        RECT 106.200 73.400 106.600 80.100 ;
        RECT 108.300 79.800 109.000 80.200 ;
        RECT 111.400 79.900 111.800 83.300 ;
        RECT 112.200 81.900 112.700 83.300 ;
        RECT 116.150 80.950 117.850 82.550 ;
        RECT 113.900 79.900 114.900 80.200 ;
        RECT 108.300 75.600 108.700 79.800 ;
        RECT 109.100 73.400 109.500 79.500 ;
        RECT 111.400 78.850 114.900 79.900 ;
        RECT 111.300 73.700 111.800 77.800 ;
        RECT 112.200 76.800 112.600 78.850 ;
        RECT 113.900 77.700 114.900 78.850 ;
        RECT 116.150 77.900 117.850 79.500 ;
        RECT 112.100 75.700 112.600 76.600 ;
        RECT 111.300 73.400 112.000 73.700 ;
        RECT 97.100 73.300 112.000 73.400 ;
        RECT 91.050 72.650 111.800 73.300 ;
        RECT 116.150 72.900 117.850 74.500 ;
        RECT 91.050 72.600 107.450 72.650 ;
        RECT 97.270 72.480 107.450 72.600 ;
        RECT 88.500 71.500 89.500 72.200 ;
        RECT 68.150 69.200 68.350 70.000 ;
        RECT 69.950 69.200 70.150 70.000 ;
        RECT 71.550 69.200 71.750 70.000 ;
        RECT 67.750 68.100 72.150 69.200 ;
        RECT 68.150 67.300 68.350 68.100 ;
        RECT 69.950 67.300 70.150 68.100 ;
        RECT 71.550 67.300 71.750 68.100 ;
        RECT 76.550 67.900 79.950 68.850 ;
        RECT 76.550 67.450 76.750 67.900 ;
        RECT 78.050 67.450 78.250 67.900 ;
        RECT 79.750 67.500 79.950 67.900 ;
        RECT 68.050 62.500 68.450 67.300 ;
        RECT 68.850 62.500 69.250 67.300 ;
        RECT 69.850 62.500 70.250 67.300 ;
        RECT 70.650 62.500 71.050 67.300 ;
        RECT 71.450 62.500 71.850 67.300 ;
        RECT 75.700 65.650 76.100 67.450 ;
        RECT 76.450 65.650 76.850 67.450 ;
        RECT 77.200 65.650 77.600 67.450 ;
        RECT 77.950 65.650 78.350 67.450 ;
        RECT 78.850 65.700 79.250 67.500 ;
        RECT 79.650 65.700 80.050 67.500 ;
        RECT 97.100 66.000 98.500 66.300 ;
        RECT 75.800 65.200 76.000 65.650 ;
        RECT 77.300 65.200 77.500 65.650 ;
        RECT 75.800 65.000 77.500 65.200 ;
        RECT 78.150 65.250 78.550 65.350 ;
        RECT 78.950 65.250 79.150 65.700 ;
        RECT 78.150 65.050 79.150 65.250 ;
        RECT 76.600 64.700 77.050 65.000 ;
        RECT 78.150 64.950 78.550 65.050 ;
        RECT 76.000 64.400 77.800 64.700 ;
        RECT 78.950 64.400 79.150 65.050 ;
        RECT 79.450 64.700 80.150 65.400 ;
        RECT 76.000 64.000 76.300 64.400 ;
        RECT 77.500 64.000 77.800 64.400 ;
        RECT 68.150 61.150 68.650 61.650 ;
        RECT 68.950 61.550 69.150 62.500 ;
        RECT 70.750 62.100 70.950 62.500 ;
        RECT 71.600 62.100 74.900 62.200 ;
        RECT 70.750 61.900 74.900 62.100 ;
        RECT 71.550 61.800 74.900 61.900 ;
        RECT 68.950 61.150 70.450 61.550 ;
        RECT 68.950 60.750 69.150 61.150 ;
        RECT 70.850 60.950 71.350 61.450 ;
        RECT 71.550 60.750 71.750 61.800 ;
        RECT 74.550 61.100 74.900 61.800 ;
        RECT 75.250 61.700 75.650 64.000 ;
        RECT 75.950 61.700 76.350 64.000 ;
        RECT 76.650 61.700 77.050 64.000 ;
        RECT 77.450 61.700 77.850 64.000 ;
        RECT 75.300 61.100 75.600 61.700 ;
        RECT 76.700 61.100 77.000 61.700 ;
        RECT 75.300 60.850 77.000 61.100 ;
        RECT 60.400 59.850 61.150 60.000 ;
        RECT 55.700 59.550 56.150 59.750 ;
        RECT 54.700 59.350 56.150 59.550 ;
        RECT 58.200 59.400 61.150 59.850 ;
        RECT 48.700 59.100 48.900 59.350 ;
        RECT 49.700 59.100 49.900 59.350 ;
        RECT 51.700 59.100 51.900 59.350 ;
        RECT 52.700 59.100 52.900 59.350 ;
        RECT 54.700 59.100 54.900 59.350 ;
        RECT 55.700 59.100 55.900 59.350 ;
        RECT 60.400 59.250 61.150 59.400 ;
        RECT 61.800 59.450 62.300 60.450 ;
        RECT 62.850 59.650 63.450 60.200 ;
        RECT 47.950 56.200 48.350 59.100 ;
        RECT 48.600 56.200 49.000 59.100 ;
        RECT 47.950 54.150 48.150 56.200 ;
        RECT 48.400 55.500 48.800 55.900 ;
        RECT 49.500 54.700 49.900 59.100 ;
        RECT 50.150 54.700 50.550 59.100 ;
        RECT 50.950 56.200 51.350 59.100 ;
        RECT 51.600 56.200 52.000 59.100 ;
        RECT 50.250 54.150 50.450 54.700 ;
        RECT 50.950 54.150 51.150 56.200 ;
        RECT 51.400 55.500 51.800 55.900 ;
        RECT 52.500 54.700 52.900 59.100 ;
        RECT 53.150 54.700 53.550 59.100 ;
        RECT 53.950 56.200 54.350 59.100 ;
        RECT 54.600 56.200 55.000 59.100 ;
        RECT 53.250 54.150 53.450 54.700 ;
        RECT 53.950 54.150 54.150 56.200 ;
        RECT 54.400 55.500 54.800 55.900 ;
        RECT 55.500 54.700 55.900 59.100 ;
        RECT 56.150 54.700 56.550 59.100 ;
        RECT 61.800 59.050 64.700 59.450 ;
        RECT 56.250 54.150 56.450 54.700 ;
        RECT 38.150 53.050 39.150 54.000 ;
        RECT 47.400 53.150 56.950 54.150 ;
        RECT 58.250 52.650 60.200 52.950 ;
        RECT 60.600 52.650 61.000 58.850 ;
        RECT 58.250 51.650 61.000 52.650 ;
        RECT 61.400 52.050 62.700 58.850 ;
        RECT 63.100 52.050 63.500 59.050 ;
        RECT 63.900 58.700 64.700 59.050 ;
        RECT 68.050 57.050 68.450 60.750 ;
        RECT 68.850 57.050 69.250 60.750 ;
        RECT 69.850 57.050 70.250 60.750 ;
        RECT 70.650 57.050 71.050 60.750 ;
        RECT 71.450 57.050 71.850 60.750 ;
        RECT 75.300 60.650 75.600 60.850 ;
        RECT 75.050 59.800 75.900 60.650 ;
        RECT 78.850 60.600 79.250 64.400 ;
        RECT 79.650 60.600 80.050 64.400 ;
        RECT 81.850 62.050 83.050 63.350 ;
        RECT 87.300 60.800 90.000 60.950 ;
        RECT 79.750 60.350 79.950 60.600 ;
        RECT 86.950 60.400 91.250 60.800 ;
        RECT 79.750 59.650 80.450 60.350 ;
        RECT 87.350 59.900 87.550 60.400 ;
        RECT 88.950 59.900 89.150 60.400 ;
        RECT 95.450 60.300 95.850 65.700 ;
        RECT 96.250 65.550 98.500 66.000 ;
        RECT 96.250 60.900 96.650 65.550 ;
        RECT 97.100 65.200 98.500 65.550 ;
        RECT 87.250 59.100 87.650 59.900 ;
        RECT 88.050 59.100 88.450 59.900 ;
        RECT 88.850 59.100 89.250 59.900 ;
        RECT 89.650 59.100 90.050 59.900 ;
        RECT 95.000 59.750 95.850 60.300 ;
        RECT 73.750 58.550 74.200 59.000 ;
        RECT 87.550 58.700 87.950 58.800 ;
        RECT 86.000 58.400 87.950 58.700 ;
        RECT 88.150 58.700 88.350 59.100 ;
        RECT 89.750 58.800 90.050 59.100 ;
        RECT 89.050 58.700 89.550 58.800 ;
        RECT 88.150 58.500 89.550 58.700 ;
        RECT 89.750 58.500 90.850 58.800 ;
        RECT 89.050 58.400 89.550 58.500 ;
        RECT 90.550 58.450 90.850 58.500 ;
        RECT 86.000 58.150 87.200 58.400 ;
        RECT 68.150 56.450 68.350 57.050 ;
        RECT 69.950 56.450 70.150 57.050 ;
        RECT 73.250 56.800 73.650 58.050 ;
        RECT 71.700 56.450 73.650 56.800 ;
        RECT 67.750 55.800 73.650 56.450 ;
        RECT 67.750 55.450 72.150 55.800 ;
        RECT 68.150 54.650 68.350 55.450 ;
        RECT 69.950 54.650 70.150 55.450 ;
        RECT 68.050 50.950 68.450 54.650 ;
        RECT 68.850 50.950 69.250 54.650 ;
        RECT 69.850 50.950 70.250 54.650 ;
        RECT 70.650 50.950 71.050 54.650 ;
        RECT 71.450 50.950 71.850 54.650 ;
        RECT 73.250 54.250 73.650 55.800 ;
        RECT 74.050 56.600 74.450 58.050 ;
        RECT 88.200 57.800 88.750 58.250 ;
        RECT 89.050 57.200 89.250 58.400 ;
        RECT 90.550 57.900 91.400 58.450 ;
        RECT 90.550 57.200 90.850 57.900 ;
        RECT 87.150 56.700 87.750 57.200 ;
        RECT 87.950 56.700 88.550 57.200 ;
        RECT 88.750 56.700 89.350 57.200 ;
        RECT 89.650 56.700 90.250 57.200 ;
        RECT 90.450 56.700 91.050 57.200 ;
        RECT 95.450 57.100 95.850 59.750 ;
        RECT 96.050 59.700 96.850 60.400 ;
        RECT 74.050 55.900 75.300 56.600 ;
        RECT 87.350 56.300 87.550 56.700 ;
        RECT 89.750 56.300 89.950 56.700 ;
        RECT 96.250 56.350 96.650 59.400 ;
        RECT 86.950 55.900 91.250 56.300 ;
        RECT 74.050 54.250 74.450 55.900 ;
        RECT 87.300 55.600 90.000 55.900 ;
        RECT 95.100 55.350 96.650 56.350 ;
        RECT 77.200 51.250 78.100 52.000 ;
        RECT 74.700 50.950 78.100 51.250 ;
        RECT 68.150 50.150 68.650 50.650 ;
        RECT 68.950 50.550 69.150 50.950 ;
        RECT 71.550 50.750 71.750 50.950 ;
        RECT 74.700 50.900 78.000 50.950 ;
        RECT 68.950 50.150 70.450 50.550 ;
        RECT 70.850 50.250 71.350 50.750 ;
        RECT 71.550 50.300 74.400 50.750 ;
        RECT 74.700 50.350 75.000 50.900 ;
        RECT 76.200 50.350 76.500 50.900 ;
        RECT 77.700 50.350 78.000 50.900 ;
        RECT 80.500 50.350 81.000 50.850 ;
        RECT 68.950 49.200 69.150 50.150 ;
        RECT 71.550 49.800 71.750 50.300 ;
        RECT 70.750 49.600 71.750 49.800 ;
        RECT 70.750 49.200 70.950 49.600 ;
        RECT 42.650 47.500 46.900 48.460 ;
        RECT 44.700 43.900 45.100 47.500 ;
        RECT 49.500 47.400 50.200 47.700 ;
        RECT 49.500 47.000 50.700 47.400 ;
        RECT 51.500 47.000 52.200 47.700 ;
        RECT 50.300 46.700 50.700 47.000 ;
        RECT 50.300 43.900 51.600 46.700 ;
        RECT 52.000 45.500 52.400 46.700 ;
        RECT 52.000 44.700 59.200 45.500 ;
        RECT 52.000 43.400 52.400 44.700 ;
        RECT 47.800 43.000 52.400 43.400 ;
        RECT 47.800 40.500 48.200 43.000 ;
        RECT 42.300 38.000 42.700 40.500 ;
        RECT 46.900 39.700 48.200 40.500 ;
        RECT 44.500 38.700 45.200 39.400 ;
        RECT 50.000 38.700 50.700 39.400 ;
        RECT 52.400 38.000 52.800 42.500 ;
        RECT 53.300 38.000 53.700 43.800 ;
        RECT 57.900 39.700 58.300 44.700 ;
        RECT 58.800 39.700 59.200 44.700 ;
        RECT 55.400 38.700 56.100 39.400 ;
        RECT 61.000 38.700 61.700 39.400 ;
        RECT 63.400 38.000 63.800 45.500 ;
        RECT 68.050 44.400 68.450 49.200 ;
        RECT 68.850 44.400 69.250 49.200 ;
        RECT 69.850 44.400 70.250 49.200 ;
        RECT 70.650 44.400 71.050 49.200 ;
        RECT 71.450 44.400 71.850 49.200 ;
        RECT 74.650 44.550 75.050 50.350 ;
        RECT 75.400 44.550 75.800 50.350 ;
        RECT 76.150 44.550 76.550 50.350 ;
        RECT 76.900 44.550 77.300 50.350 ;
        RECT 77.650 44.550 78.050 50.350 ;
        RECT 78.400 44.550 78.800 50.350 ;
        RECT 80.500 50.050 80.800 50.350 ;
        RECT 68.150 43.600 68.350 44.400 ;
        RECT 69.950 43.600 70.150 44.400 ;
        RECT 71.550 43.600 71.750 44.400 ;
        RECT 75.450 43.950 75.750 44.550 ;
        RECT 76.950 43.950 77.250 44.550 ;
        RECT 78.450 43.950 78.750 44.550 ;
        RECT 79.700 44.250 80.100 50.050 ;
        RECT 80.450 44.250 80.850 50.050 ;
        RECT 81.900 46.150 83.100 47.450 ;
        RECT 75.450 43.750 78.750 43.950 ;
        RECT 67.750 42.600 72.150 43.600 ;
        RECT 76.250 43.500 78.050 43.750 ;
        RECT 79.800 43.550 80.000 44.250 ;
        RECT 76.250 42.850 76.550 43.500 ;
        RECT 77.750 42.850 78.050 43.500 ;
        RECT 78.600 43.150 80.000 43.550 ;
        RECT 76.200 40.050 76.600 42.850 ;
        RECT 76.950 40.050 77.350 42.850 ;
        RECT 77.700 40.050 78.100 42.850 ;
        RECT 78.450 40.050 78.850 42.850 ;
        RECT 79.800 42.250 80.000 43.150 ;
        RECT 80.250 43.050 80.950 43.750 ;
        RECT 79.700 40.450 80.100 42.250 ;
        RECT 80.450 40.450 80.850 42.250 ;
        RECT 77.000 39.450 77.300 40.050 ;
        RECT 78.500 39.450 78.800 40.050 ;
        RECT 80.500 39.450 80.800 40.450 ;
        RECT 77.000 38.750 80.800 39.450 ;
        RECT 41.700 36.450 65.800 38.000 ;
      LAYER met1 ;
        RECT 45.750 154.700 48.050 155.900 ;
        RECT 54.150 154.700 56.450 155.900 ;
        RECT 65.850 154.700 68.150 155.900 ;
        RECT 75.250 154.700 77.550 155.900 ;
        RECT 87.050 154.700 89.350 155.900 ;
        RECT 97.550 154.700 99.850 155.900 ;
        RECT 49.350 152.900 49.750 153.000 ;
        RECT 41.650 152.700 49.750 152.900 ;
        RECT 41.650 151.900 41.850 152.700 ;
        RECT 49.350 152.600 49.750 152.700 ;
        RECT 52.550 152.900 53.050 153.100 ;
        RECT 60.050 152.900 60.450 153.000 ;
        RECT 52.550 152.700 60.450 152.900 ;
        RECT 52.550 152.600 53.050 152.700 ;
        RECT 50.150 152.100 50.550 152.500 ;
        RECT 41.550 151.100 42.350 151.900 ;
        RECT 36.950 147.700 37.350 147.800 ;
        RECT 34.450 147.500 37.350 147.700 ;
        RECT 41.650 147.600 41.850 151.100 ;
        RECT 45.550 147.700 45.950 147.800 ;
        RECT 34.450 147.300 34.650 147.500 ;
        RECT 36.950 147.400 37.350 147.500 ;
        RECT 41.550 147.500 41.950 147.600 ;
        RECT 43.050 147.500 45.950 147.700 ;
        RECT 50.250 147.600 50.450 152.100 ;
        RECT 50.850 149.900 53.250 151.000 ;
        RECT 41.550 147.300 43.250 147.500 ;
        RECT 45.550 147.400 45.950 147.500 ;
        RECT 50.150 147.500 50.550 147.600 ;
        RECT 50.850 147.500 51.650 147.800 ;
        RECT 50.150 147.300 51.650 147.500 ;
        RECT 53.750 147.700 53.950 152.700 ;
        RECT 60.050 152.600 60.450 152.700 ;
        RECT 63.250 152.900 63.750 153.100 ;
        RECT 70.750 152.900 71.150 153.000 ;
        RECT 63.250 152.700 71.150 152.900 ;
        RECT 63.250 152.600 63.750 152.700 ;
        RECT 60.850 152.100 61.250 152.500 ;
        RECT 56.250 147.700 56.650 147.800 ;
        RECT 53.750 147.500 56.650 147.700 ;
        RECT 60.950 147.600 61.150 152.100 ;
        RECT 61.550 149.900 63.950 151.000 ;
        RECT 53.750 147.300 53.950 147.500 ;
        RECT 56.250 147.400 56.650 147.500 ;
        RECT 60.850 147.500 61.250 147.600 ;
        RECT 61.550 147.500 62.350 147.800 ;
        RECT 60.850 147.300 62.350 147.500 ;
        RECT 64.450 147.700 64.650 152.700 ;
        RECT 70.750 152.600 71.150 152.700 ;
        RECT 73.950 152.900 74.450 153.100 ;
        RECT 81.450 152.900 81.850 153.000 ;
        RECT 73.950 152.700 81.850 152.900 ;
        RECT 73.950 152.600 74.450 152.700 ;
        RECT 71.550 152.100 71.950 152.500 ;
        RECT 66.950 147.700 67.350 147.800 ;
        RECT 64.450 147.500 67.350 147.700 ;
        RECT 71.650 147.600 71.850 152.100 ;
        RECT 72.250 149.900 74.650 151.000 ;
        RECT 64.450 147.300 64.650 147.500 ;
        RECT 66.950 147.400 67.350 147.500 ;
        RECT 71.550 147.500 71.950 147.600 ;
        RECT 72.250 147.500 73.050 147.800 ;
        RECT 71.550 147.300 73.050 147.500 ;
        RECT 75.150 147.700 75.350 152.700 ;
        RECT 81.450 152.600 81.850 152.700 ;
        RECT 84.650 152.900 85.150 153.100 ;
        RECT 92.150 152.900 92.550 153.000 ;
        RECT 84.650 152.700 92.550 152.900 ;
        RECT 84.650 152.600 85.150 152.700 ;
        RECT 82.250 152.100 82.650 152.500 ;
        RECT 77.650 147.700 78.050 147.800 ;
        RECT 75.150 147.500 78.050 147.700 ;
        RECT 82.350 147.600 82.550 152.100 ;
        RECT 82.950 149.900 85.350 151.000 ;
        RECT 75.150 147.300 75.350 147.500 ;
        RECT 77.650 147.400 78.050 147.500 ;
        RECT 82.250 147.500 82.650 147.600 ;
        RECT 82.950 147.500 83.750 147.800 ;
        RECT 82.250 147.300 83.750 147.500 ;
        RECT 85.850 147.700 86.050 152.700 ;
        RECT 92.150 152.600 92.550 152.700 ;
        RECT 95.350 152.900 95.850 153.100 ;
        RECT 102.850 152.900 103.250 153.000 ;
        RECT 95.350 152.700 103.250 152.900 ;
        RECT 95.350 152.600 95.850 152.700 ;
        RECT 92.950 152.100 93.350 152.500 ;
        RECT 88.350 147.700 88.750 147.800 ;
        RECT 85.850 147.500 88.750 147.700 ;
        RECT 93.050 147.600 93.250 152.100 ;
        RECT 93.650 149.900 96.050 151.000 ;
        RECT 85.850 147.300 86.050 147.500 ;
        RECT 88.350 147.400 88.750 147.500 ;
        RECT 92.950 147.500 93.350 147.600 ;
        RECT 93.650 147.500 94.450 147.800 ;
        RECT 92.950 147.300 94.450 147.500 ;
        RECT 96.550 147.700 96.750 152.700 ;
        RECT 102.850 152.600 103.250 152.700 ;
        RECT 106.050 152.900 106.550 153.100 ;
        RECT 106.050 152.700 107.450 152.900 ;
        RECT 106.050 152.600 106.550 152.700 ;
        RECT 103.650 152.100 104.050 152.500 ;
        RECT 99.050 147.700 99.450 147.800 ;
        RECT 96.550 147.500 99.450 147.700 ;
        RECT 103.750 147.600 103.950 152.100 ;
        RECT 104.350 149.900 106.750 151.000 ;
        RECT 96.550 147.300 96.750 147.500 ;
        RECT 99.050 147.400 99.450 147.500 ;
        RECT 103.650 147.500 104.050 147.600 ;
        RECT 104.350 147.500 105.150 147.800 ;
        RECT 103.650 147.300 105.150 147.500 ;
        RECT 107.250 147.700 107.450 152.700 ;
        RECT 109.750 147.700 110.150 147.800 ;
        RECT 107.250 147.500 110.150 147.700 ;
        RECT 107.250 147.300 107.450 147.500 ;
        RECT 109.750 147.400 110.150 147.500 ;
        RECT 114.350 147.500 114.750 147.600 ;
        RECT 115.050 147.500 115.850 147.800 ;
        RECT 114.350 147.300 115.850 147.500 ;
        RECT 34.350 146.900 34.750 147.300 ;
        RECT 41.550 147.200 41.950 147.300 ;
        RECT 37.950 146.400 38.550 147.000 ;
        RECT 41.750 138.900 41.950 147.200 ;
        RECT 42.950 146.900 43.350 147.300 ;
        RECT 50.150 147.200 50.550 147.300 ;
        RECT 46.550 146.400 47.150 147.000 ;
        RECT 50.350 138.900 50.550 147.200 ;
        RECT 50.850 147.000 51.650 147.300 ;
        RECT 53.650 146.900 54.050 147.300 ;
        RECT 60.850 147.200 61.250 147.300 ;
        RECT 57.250 146.400 57.850 147.000 ;
        RECT 51.150 141.500 53.450 142.700 ;
        RECT 61.050 138.900 61.250 147.200 ;
        RECT 61.550 147.000 62.350 147.300 ;
        RECT 64.350 146.900 64.750 147.300 ;
        RECT 71.550 147.200 71.950 147.300 ;
        RECT 67.950 146.400 68.550 147.000 ;
        RECT 61.850 141.500 64.150 142.700 ;
        RECT 71.750 138.900 71.950 147.200 ;
        RECT 72.250 147.000 73.050 147.300 ;
        RECT 75.050 146.900 75.450 147.300 ;
        RECT 82.250 147.200 82.650 147.300 ;
        RECT 78.650 146.400 79.250 147.000 ;
        RECT 72.550 141.500 74.850 142.700 ;
        RECT 82.450 138.900 82.650 147.200 ;
        RECT 82.950 147.000 83.750 147.300 ;
        RECT 85.750 146.900 86.150 147.300 ;
        RECT 92.950 147.200 93.350 147.300 ;
        RECT 89.350 146.400 89.950 147.000 ;
        RECT 83.250 141.500 85.550 142.700 ;
        RECT 93.150 138.900 93.350 147.200 ;
        RECT 93.650 147.000 94.450 147.300 ;
        RECT 96.450 146.900 96.850 147.300 ;
        RECT 103.650 147.200 104.050 147.300 ;
        RECT 100.050 146.400 100.650 147.000 ;
        RECT 93.950 141.500 96.250 142.700 ;
        RECT 103.850 138.900 104.050 147.200 ;
        RECT 104.350 147.000 105.150 147.300 ;
        RECT 107.150 146.900 107.550 147.300 ;
        RECT 114.350 147.200 114.750 147.300 ;
        RECT 110.750 146.400 111.350 147.000 ;
        RECT 104.650 141.500 106.950 142.700 ;
        RECT 114.550 138.900 114.750 147.200 ;
        RECT 115.050 147.000 115.850 147.300 ;
        RECT 35.950 138.400 36.350 138.700 ;
        RECT 34.250 138.300 36.350 138.400 ;
        RECT 34.250 138.200 36.250 138.300 ;
        RECT 34.250 124.700 34.450 138.200 ;
        RECT 36.750 137.800 37.350 138.400 ;
        RECT 37.550 138.300 38.150 138.900 ;
        RECT 37.750 137.200 37.950 138.300 ;
        RECT 39.550 138.200 40.150 138.800 ;
        RECT 40.450 137.800 41.050 138.400 ;
        RECT 41.250 138.300 41.950 138.900 ;
        RECT 44.550 138.400 44.950 138.700 ;
        RECT 42.850 138.300 44.950 138.400 ;
        RECT 35.150 137.000 37.950 137.200 ;
        RECT 35.150 132.200 35.350 137.000 ;
        RECT 41.550 136.800 41.750 138.300 ;
        RECT 38.850 136.600 41.750 136.800 ;
        RECT 42.850 138.200 44.850 138.300 ;
        RECT 38.150 133.200 38.650 133.400 ;
        RECT 36.950 133.100 38.650 133.200 ;
        RECT 36.850 133.000 38.650 133.100 ;
        RECT 36.850 132.700 37.250 133.000 ;
        RECT 38.150 132.900 38.650 133.000 ;
        RECT 35.950 132.300 36.350 132.700 ;
        RECT 35.050 131.800 35.450 132.200 ;
        RECT 34.950 125.500 35.550 126.100 ;
        RECT 36.050 125.600 36.250 132.300 ;
        RECT 37.550 132.100 38.150 132.700 ;
        RECT 38.850 132.200 39.050 136.600 ;
        RECT 39.650 132.300 40.050 132.700 ;
        RECT 40.450 132.600 41.050 133.200 ;
        RECT 38.750 131.800 39.150 132.200 ;
        RECT 39.650 129.800 39.850 132.300 ;
        RECT 38.850 129.600 39.850 129.800 ;
        RECT 38.850 126.000 39.050 129.600 ;
        RECT 40.650 127.900 40.850 132.600 ;
        RECT 41.250 132.100 41.850 132.700 ;
        RECT 40.650 127.700 42.450 127.900 ;
        RECT 38.750 125.700 39.150 126.000 ;
        RECT 37.550 125.600 39.150 125.700 ;
        RECT 35.850 125.000 36.450 125.600 ;
        RECT 37.550 125.500 38.950 125.600 ;
        RECT 37.550 125.100 38.150 125.500 ;
        RECT 36.850 124.700 37.250 125.100 ;
        RECT 39.550 125.000 40.150 125.600 ;
        RECT 40.650 125.100 40.850 127.700 ;
        RECT 41.250 125.100 41.850 125.700 ;
        RECT 40.550 124.700 40.950 125.100 ;
        RECT 34.250 124.500 37.150 124.700 ;
        RECT 36.950 124.000 37.150 124.500 ;
        RECT 41.550 124.000 41.750 125.100 ;
        RECT 36.950 123.800 41.750 124.000 ;
        RECT 42.250 120.600 42.450 127.700 ;
        RECT 42.850 124.700 43.050 138.200 ;
        RECT 45.350 137.800 45.950 138.400 ;
        RECT 46.150 138.300 46.750 138.900 ;
        RECT 46.350 137.200 46.550 138.300 ;
        RECT 48.150 138.200 48.750 138.800 ;
        RECT 49.050 137.800 49.650 138.400 ;
        RECT 49.850 138.300 50.550 138.900 ;
        RECT 55.250 138.400 55.650 138.700 ;
        RECT 53.550 138.300 55.650 138.400 ;
        RECT 43.750 137.000 46.550 137.200 ;
        RECT 43.750 132.200 43.950 137.000 ;
        RECT 50.150 136.800 50.350 138.300 ;
        RECT 47.450 136.600 50.350 136.800 ;
        RECT 53.550 138.200 55.550 138.300 ;
        RECT 46.750 133.200 47.250 133.400 ;
        RECT 45.550 133.100 47.250 133.200 ;
        RECT 45.450 133.000 47.250 133.100 ;
        RECT 45.450 132.700 45.850 133.000 ;
        RECT 46.750 132.900 47.250 133.000 ;
        RECT 44.550 132.300 44.950 132.700 ;
        RECT 43.650 131.800 44.050 132.200 ;
        RECT 43.550 125.500 44.150 126.100 ;
        RECT 44.650 125.600 44.850 132.300 ;
        RECT 46.150 132.100 46.750 132.700 ;
        RECT 47.450 132.200 47.650 136.600 ;
        RECT 50.750 135.000 53.150 136.100 ;
        RECT 48.250 132.300 48.650 132.700 ;
        RECT 49.050 132.600 49.650 133.200 ;
        RECT 47.350 131.800 47.750 132.200 ;
        RECT 48.250 129.800 48.450 132.300 ;
        RECT 47.450 129.600 48.450 129.800 ;
        RECT 47.450 126.000 47.650 129.600 ;
        RECT 49.250 127.900 49.450 132.600 ;
        RECT 49.850 132.100 50.450 132.700 ;
        RECT 50.550 128.300 52.850 129.500 ;
        RECT 49.250 127.700 50.850 127.900 ;
        RECT 47.350 125.700 47.750 126.000 ;
        RECT 46.150 125.600 47.750 125.700 ;
        RECT 44.450 125.000 45.050 125.600 ;
        RECT 46.150 125.500 47.550 125.600 ;
        RECT 46.150 125.100 46.750 125.500 ;
        RECT 45.450 124.700 45.850 125.100 ;
        RECT 48.150 125.000 48.750 125.600 ;
        RECT 49.250 125.100 49.450 127.700 ;
        RECT 49.850 125.100 50.450 125.700 ;
        RECT 49.150 124.700 49.550 125.100 ;
        RECT 42.850 124.500 45.750 124.700 ;
        RECT 45.550 124.000 45.750 124.500 ;
        RECT 50.150 124.000 50.350 125.100 ;
        RECT 45.550 123.800 50.350 124.000 ;
        RECT 42.850 121.800 45.250 122.900 ;
        RECT 50.650 120.800 50.850 127.700 ;
        RECT 53.550 124.700 53.750 138.200 ;
        RECT 56.050 137.800 56.650 138.400 ;
        RECT 56.850 138.300 57.450 138.900 ;
        RECT 57.050 137.200 57.250 138.300 ;
        RECT 58.850 138.200 59.450 138.800 ;
        RECT 59.750 137.800 60.350 138.400 ;
        RECT 60.550 138.300 61.250 138.900 ;
        RECT 65.950 138.400 66.350 138.700 ;
        RECT 64.250 138.300 66.350 138.400 ;
        RECT 54.450 137.000 57.250 137.200 ;
        RECT 54.450 132.200 54.650 137.000 ;
        RECT 60.850 136.800 61.050 138.300 ;
        RECT 58.150 136.600 61.050 136.800 ;
        RECT 64.250 138.200 66.250 138.300 ;
        RECT 57.450 133.200 57.950 133.400 ;
        RECT 56.250 133.100 57.950 133.200 ;
        RECT 56.150 133.000 57.950 133.100 ;
        RECT 56.150 132.700 56.550 133.000 ;
        RECT 57.450 132.900 57.950 133.000 ;
        RECT 55.250 132.300 55.650 132.700 ;
        RECT 54.350 131.800 54.750 132.200 ;
        RECT 54.250 125.500 54.850 126.100 ;
        RECT 55.350 125.600 55.550 132.300 ;
        RECT 56.850 132.100 57.450 132.700 ;
        RECT 58.150 132.200 58.350 136.600 ;
        RECT 61.450 135.000 63.850 136.100 ;
        RECT 58.950 132.300 59.350 132.700 ;
        RECT 59.750 132.600 60.350 133.200 ;
        RECT 58.050 131.800 58.450 132.200 ;
        RECT 58.950 129.800 59.150 132.300 ;
        RECT 58.150 129.600 59.150 129.800 ;
        RECT 58.150 126.000 58.350 129.600 ;
        RECT 59.950 127.900 60.150 132.600 ;
        RECT 60.550 132.100 61.150 132.700 ;
        RECT 61.150 128.300 63.450 129.500 ;
        RECT 59.950 127.700 61.550 127.900 ;
        RECT 58.050 125.700 58.450 126.000 ;
        RECT 56.850 125.600 58.450 125.700 ;
        RECT 55.150 125.000 55.750 125.600 ;
        RECT 56.850 125.500 58.250 125.600 ;
        RECT 56.850 125.100 57.450 125.500 ;
        RECT 56.150 124.700 56.550 125.100 ;
        RECT 58.850 125.000 59.450 125.600 ;
        RECT 59.950 125.100 60.150 127.700 ;
        RECT 60.550 125.100 61.150 125.700 ;
        RECT 59.850 124.700 60.250 125.100 ;
        RECT 53.550 124.500 56.450 124.700 ;
        RECT 56.250 124.000 56.450 124.500 ;
        RECT 60.850 124.000 61.050 125.100 ;
        RECT 56.250 123.800 61.050 124.000 ;
        RECT 51.650 121.800 54.050 122.900 ;
        RECT 50.050 120.600 50.850 120.800 ;
        RECT 61.350 120.600 61.550 127.700 ;
        RECT 64.250 124.700 64.450 138.200 ;
        RECT 66.750 137.800 67.350 138.400 ;
        RECT 67.550 138.300 68.150 138.900 ;
        RECT 67.750 137.200 67.950 138.300 ;
        RECT 69.550 138.200 70.150 138.800 ;
        RECT 70.450 137.800 71.050 138.400 ;
        RECT 71.250 138.300 71.950 138.900 ;
        RECT 76.650 138.400 77.050 138.700 ;
        RECT 74.950 138.300 77.050 138.400 ;
        RECT 65.150 137.000 67.950 137.200 ;
        RECT 65.150 132.200 65.350 137.000 ;
        RECT 71.550 136.800 71.750 138.300 ;
        RECT 68.850 136.600 71.750 136.800 ;
        RECT 74.950 138.200 76.950 138.300 ;
        RECT 68.150 133.200 68.650 133.400 ;
        RECT 66.950 133.100 68.650 133.200 ;
        RECT 66.850 133.000 68.650 133.100 ;
        RECT 66.850 132.700 67.250 133.000 ;
        RECT 68.150 132.900 68.650 133.000 ;
        RECT 65.950 132.300 66.350 132.700 ;
        RECT 65.050 131.800 65.450 132.200 ;
        RECT 64.950 125.500 65.550 126.100 ;
        RECT 66.050 125.600 66.250 132.300 ;
        RECT 67.550 132.100 68.150 132.700 ;
        RECT 68.850 132.200 69.050 136.600 ;
        RECT 72.150 135.000 74.550 136.100 ;
        RECT 69.650 132.300 70.050 132.700 ;
        RECT 70.450 132.600 71.050 133.200 ;
        RECT 68.750 131.800 69.150 132.200 ;
        RECT 69.650 129.800 69.850 132.300 ;
        RECT 68.850 129.600 69.850 129.800 ;
        RECT 68.850 126.000 69.050 129.600 ;
        RECT 70.650 127.900 70.850 132.600 ;
        RECT 71.250 132.100 71.850 132.700 ;
        RECT 72.050 128.300 74.350 129.500 ;
        RECT 70.650 127.700 72.250 127.900 ;
        RECT 68.750 125.700 69.150 126.000 ;
        RECT 67.550 125.600 69.150 125.700 ;
        RECT 65.850 125.000 66.450 125.600 ;
        RECT 67.550 125.500 68.950 125.600 ;
        RECT 67.550 125.100 68.150 125.500 ;
        RECT 66.850 124.700 67.250 125.100 ;
        RECT 69.550 125.000 70.150 125.600 ;
        RECT 70.650 125.100 70.850 127.700 ;
        RECT 71.250 125.100 71.850 125.700 ;
        RECT 70.550 124.700 70.950 125.100 ;
        RECT 64.250 124.500 67.150 124.700 ;
        RECT 66.950 124.000 67.150 124.500 ;
        RECT 71.550 124.000 71.750 125.100 ;
        RECT 66.950 123.800 71.750 124.000 ;
        RECT 62.250 121.800 64.650 122.900 ;
        RECT 72.050 120.600 72.250 127.700 ;
        RECT 74.950 124.700 75.150 138.200 ;
        RECT 77.450 137.800 78.050 138.400 ;
        RECT 78.250 138.300 78.850 138.900 ;
        RECT 78.450 137.200 78.650 138.300 ;
        RECT 80.250 138.200 80.850 138.800 ;
        RECT 81.150 137.800 81.750 138.400 ;
        RECT 81.950 138.300 82.650 138.900 ;
        RECT 87.350 138.400 87.750 138.700 ;
        RECT 85.650 138.300 87.750 138.400 ;
        RECT 75.850 137.000 78.650 137.200 ;
        RECT 75.850 132.200 76.050 137.000 ;
        RECT 82.250 136.800 82.450 138.300 ;
        RECT 79.550 136.600 82.450 136.800 ;
        RECT 85.650 138.200 87.650 138.300 ;
        RECT 78.850 133.200 79.350 133.400 ;
        RECT 77.650 133.100 79.350 133.200 ;
        RECT 77.550 133.000 79.350 133.100 ;
        RECT 77.550 132.700 77.950 133.000 ;
        RECT 78.850 132.900 79.350 133.000 ;
        RECT 76.650 132.300 77.050 132.700 ;
        RECT 75.750 131.800 76.150 132.200 ;
        RECT 75.650 125.500 76.250 126.100 ;
        RECT 76.750 125.600 76.950 132.300 ;
        RECT 78.250 132.100 78.850 132.700 ;
        RECT 79.550 132.200 79.750 136.600 ;
        RECT 82.850 135.000 85.250 136.100 ;
        RECT 80.350 132.300 80.750 132.700 ;
        RECT 81.150 132.600 81.750 133.200 ;
        RECT 79.450 131.800 79.850 132.200 ;
        RECT 80.350 129.800 80.550 132.300 ;
        RECT 79.550 129.600 80.550 129.800 ;
        RECT 79.550 126.000 79.750 129.600 ;
        RECT 81.350 127.900 81.550 132.600 ;
        RECT 81.950 132.100 82.550 132.700 ;
        RECT 82.450 128.300 84.750 129.500 ;
        RECT 81.350 127.700 82.950 127.900 ;
        RECT 79.450 125.700 79.850 126.000 ;
        RECT 78.250 125.600 79.850 125.700 ;
        RECT 76.550 125.000 77.150 125.600 ;
        RECT 78.250 125.500 79.650 125.600 ;
        RECT 78.250 125.100 78.850 125.500 ;
        RECT 77.550 124.700 77.950 125.100 ;
        RECT 80.250 125.000 80.850 125.600 ;
        RECT 81.350 125.100 81.550 127.700 ;
        RECT 81.950 125.100 82.550 125.700 ;
        RECT 81.250 124.700 81.650 125.100 ;
        RECT 74.950 124.500 77.850 124.700 ;
        RECT 77.650 124.000 77.850 124.500 ;
        RECT 82.250 124.000 82.450 125.100 ;
        RECT 77.650 123.800 82.450 124.000 ;
        RECT 72.950 121.800 75.350 122.900 ;
        RECT 82.750 120.600 82.950 127.700 ;
        RECT 85.650 124.700 85.850 138.200 ;
        RECT 88.150 137.800 88.750 138.400 ;
        RECT 88.950 138.300 89.550 138.900 ;
        RECT 89.150 137.200 89.350 138.300 ;
        RECT 90.950 138.200 91.550 138.800 ;
        RECT 91.850 137.800 92.450 138.400 ;
        RECT 92.650 138.300 93.350 138.900 ;
        RECT 98.050 138.400 98.450 138.700 ;
        RECT 96.350 138.300 98.450 138.400 ;
        RECT 86.550 137.000 89.350 137.200 ;
        RECT 86.550 132.200 86.750 137.000 ;
        RECT 92.950 136.800 93.150 138.300 ;
        RECT 90.250 136.600 93.150 136.800 ;
        RECT 96.350 138.200 98.350 138.300 ;
        RECT 89.550 133.200 90.050 133.400 ;
        RECT 88.350 133.100 90.050 133.200 ;
        RECT 88.250 133.000 90.050 133.100 ;
        RECT 88.250 132.700 88.650 133.000 ;
        RECT 89.550 132.900 90.050 133.000 ;
        RECT 87.350 132.300 87.750 132.700 ;
        RECT 86.450 131.800 86.850 132.200 ;
        RECT 86.350 125.500 86.950 126.100 ;
        RECT 87.450 125.600 87.650 132.300 ;
        RECT 88.950 132.100 89.550 132.700 ;
        RECT 90.250 132.200 90.450 136.600 ;
        RECT 93.550 135.000 95.950 136.100 ;
        RECT 91.050 132.300 91.450 132.700 ;
        RECT 91.850 132.600 92.450 133.200 ;
        RECT 90.150 131.800 90.550 132.200 ;
        RECT 91.050 129.800 91.250 132.300 ;
        RECT 90.250 129.600 91.250 129.800 ;
        RECT 90.250 126.000 90.450 129.600 ;
        RECT 92.050 127.900 92.250 132.600 ;
        RECT 92.650 132.100 93.250 132.700 ;
        RECT 93.050 128.300 95.350 129.500 ;
        RECT 92.050 127.700 93.650 127.900 ;
        RECT 90.150 125.700 90.550 126.000 ;
        RECT 88.950 125.600 90.550 125.700 ;
        RECT 87.250 125.000 87.850 125.600 ;
        RECT 88.950 125.500 90.350 125.600 ;
        RECT 88.950 125.100 89.550 125.500 ;
        RECT 88.250 124.700 88.650 125.100 ;
        RECT 90.950 125.000 91.550 125.600 ;
        RECT 92.050 125.100 92.250 127.700 ;
        RECT 92.650 125.100 93.250 125.700 ;
        RECT 91.950 124.700 92.350 125.100 ;
        RECT 85.650 124.500 88.550 124.700 ;
        RECT 88.350 124.000 88.550 124.500 ;
        RECT 92.950 124.000 93.150 125.100 ;
        RECT 88.350 123.800 93.150 124.000 ;
        RECT 84.150 121.800 86.550 122.900 ;
        RECT 86.900 120.600 87.400 120.650 ;
        RECT 93.450 120.600 93.650 127.700 ;
        RECT 96.350 124.700 96.550 138.200 ;
        RECT 98.850 137.800 99.450 138.400 ;
        RECT 99.650 138.300 100.250 138.900 ;
        RECT 99.850 137.200 100.050 138.300 ;
        RECT 101.650 138.200 102.250 138.800 ;
        RECT 102.550 137.800 103.150 138.400 ;
        RECT 103.350 138.300 104.050 138.900 ;
        RECT 108.750 138.400 109.150 138.700 ;
        RECT 107.050 138.300 109.150 138.400 ;
        RECT 97.250 137.000 100.050 137.200 ;
        RECT 97.250 132.200 97.450 137.000 ;
        RECT 103.650 136.800 103.850 138.300 ;
        RECT 100.950 136.600 103.850 136.800 ;
        RECT 107.050 138.200 109.050 138.300 ;
        RECT 100.250 133.200 100.750 133.400 ;
        RECT 99.050 133.100 100.750 133.200 ;
        RECT 98.950 133.000 100.750 133.100 ;
        RECT 98.950 132.700 99.350 133.000 ;
        RECT 100.250 132.900 100.750 133.000 ;
        RECT 98.050 132.300 98.450 132.700 ;
        RECT 97.150 131.800 97.550 132.200 ;
        RECT 97.050 125.500 97.650 126.100 ;
        RECT 98.150 125.600 98.350 132.300 ;
        RECT 99.650 132.100 100.250 132.700 ;
        RECT 100.950 132.200 101.150 136.600 ;
        RECT 104.250 135.000 106.650 136.100 ;
        RECT 101.750 132.300 102.150 132.700 ;
        RECT 102.550 132.600 103.150 133.200 ;
        RECT 100.850 131.800 101.250 132.200 ;
        RECT 101.750 129.800 101.950 132.300 ;
        RECT 100.950 129.600 101.950 129.800 ;
        RECT 100.950 126.000 101.150 129.600 ;
        RECT 102.750 127.900 102.950 132.600 ;
        RECT 103.350 132.100 103.950 132.700 ;
        RECT 103.850 128.300 106.150 129.500 ;
        RECT 102.750 127.700 104.550 127.900 ;
        RECT 100.850 125.700 101.250 126.000 ;
        RECT 99.650 125.600 101.250 125.700 ;
        RECT 97.950 125.000 98.550 125.600 ;
        RECT 99.650 125.500 101.050 125.600 ;
        RECT 99.650 125.100 100.250 125.500 ;
        RECT 98.950 124.700 99.350 125.100 ;
        RECT 101.650 125.000 102.250 125.600 ;
        RECT 102.750 125.100 102.950 127.700 ;
        RECT 103.350 125.100 103.950 125.700 ;
        RECT 102.650 124.700 103.050 125.100 ;
        RECT 96.350 124.500 99.250 124.700 ;
        RECT 99.050 124.000 99.250 124.500 ;
        RECT 103.650 124.000 103.850 125.100 ;
        RECT 99.050 123.800 103.850 124.000 ;
        RECT 94.650 121.800 97.050 122.900 ;
        RECT 104.350 120.850 104.550 127.700 ;
        RECT 107.050 124.700 107.250 138.200 ;
        RECT 109.550 137.800 110.150 138.400 ;
        RECT 110.350 138.300 110.950 138.900 ;
        RECT 110.550 137.200 110.750 138.300 ;
        RECT 112.350 138.200 112.950 138.800 ;
        RECT 113.250 137.800 113.850 138.400 ;
        RECT 114.050 138.300 114.750 138.900 ;
        RECT 107.950 137.000 110.750 137.200 ;
        RECT 107.950 132.200 108.150 137.000 ;
        RECT 114.350 136.800 114.550 138.300 ;
        RECT 111.650 136.600 114.550 136.800 ;
        RECT 110.950 133.200 111.450 133.400 ;
        RECT 109.750 133.100 111.450 133.200 ;
        RECT 109.650 133.000 111.450 133.100 ;
        RECT 109.650 132.700 110.050 133.000 ;
        RECT 110.950 132.900 111.450 133.000 ;
        RECT 108.750 132.300 109.150 132.700 ;
        RECT 107.850 131.800 108.250 132.200 ;
        RECT 107.750 125.500 108.350 126.100 ;
        RECT 108.850 125.600 109.050 132.300 ;
        RECT 110.350 132.100 110.950 132.700 ;
        RECT 111.650 132.200 111.850 136.600 ;
        RECT 112.450 132.300 112.850 132.700 ;
        RECT 113.250 132.600 113.850 133.200 ;
        RECT 111.550 131.800 111.950 132.200 ;
        RECT 112.450 129.800 112.650 132.300 ;
        RECT 111.650 129.600 112.650 129.800 ;
        RECT 111.650 126.000 111.850 129.600 ;
        RECT 113.450 127.900 113.650 132.600 ;
        RECT 114.050 132.100 114.650 132.700 ;
        RECT 113.450 127.700 115.150 127.900 ;
        RECT 111.550 125.700 111.950 126.000 ;
        RECT 110.350 125.600 111.950 125.700 ;
        RECT 108.650 125.000 109.250 125.600 ;
        RECT 110.350 125.500 111.750 125.600 ;
        RECT 110.350 125.100 110.950 125.500 ;
        RECT 109.650 124.700 110.050 125.100 ;
        RECT 112.350 125.000 112.950 125.600 ;
        RECT 113.450 125.100 113.650 127.700 ;
        RECT 114.050 125.100 114.650 125.700 ;
        RECT 113.350 124.700 113.750 125.100 ;
        RECT 107.050 124.500 109.950 124.700 ;
        RECT 109.750 124.000 109.950 124.500 ;
        RECT 114.350 124.000 114.550 125.100 ;
        RECT 109.750 123.800 114.550 124.000 ;
        RECT 105.450 121.800 107.850 122.900 ;
        RECT 114.950 120.850 115.150 127.700 ;
        RECT 140.500 120.850 141.800 124.000 ;
        RECT 104.250 120.650 141.800 120.850 ;
        RECT 103.000 120.600 141.800 120.650 ;
        RECT 42.250 120.400 141.800 120.600 ;
        RECT 50.050 120.200 50.650 120.400 ;
        RECT 47.510 88.650 54.910 89.600 ;
        RECT 62.950 88.050 64.150 89.350 ;
        RECT 68.800 87.750 70.000 89.050 ;
        RECT 74.600 87.950 75.800 89.250 ;
        RECT 56.250 86.250 56.950 86.950 ;
        RECT 53.950 83.950 54.650 84.650 ;
        RECT 51.950 81.950 52.650 82.650 ;
        RECT 68.000 81.100 71.900 82.000 ;
        RECT 76.100 80.900 77.300 82.200 ;
        RECT 79.000 81.650 79.700 82.350 ;
        RECT 84.600 82.050 86.200 84.100 ;
        RECT 86.900 83.250 87.400 120.400 ;
        RECT 103.000 119.300 141.800 120.400 ;
        RECT 140.500 118.950 141.800 119.300 ;
        RECT 96.160 91.900 107.510 93.000 ;
        RECT 108.800 91.400 109.200 91.500 ;
        RECT 100.000 91.200 109.200 91.400 ;
        RECT 100.000 91.000 100.200 91.200 ;
        RECT 108.800 91.100 109.200 91.200 ;
        RECT 99.900 90.600 100.300 91.000 ;
        RECT 116.150 86.300 117.850 87.900 ;
        RECT 105.100 85.500 105.600 86.000 ;
        RECT 106.300 85.400 107.000 86.100 ;
        RECT 102.200 85.300 102.600 85.400 ;
        RECT 98.000 85.100 102.600 85.300 ;
        RECT 97.900 84.700 98.300 85.100 ;
        RECT 102.200 85.000 102.600 85.100 ;
        RECT 103.900 85.000 104.300 85.400 ;
        RECT 109.200 85.100 110.750 85.600 ;
        RECT 99.600 83.900 100.100 84.400 ;
        RECT 86.900 82.750 91.400 83.250 ;
        RECT 90.950 81.950 91.400 82.750 ;
        RECT 100.100 82.800 100.500 82.900 ;
        RECT 104.000 82.800 104.200 85.000 ;
        RECT 100.100 82.600 104.200 82.800 ;
        RECT 100.100 82.500 100.500 82.600 ;
        RECT 110.300 82.400 110.750 85.100 ;
        RECT 116.150 83.500 117.850 85.100 ;
        RECT 110.300 81.900 112.700 82.400 ;
        RECT 110.300 81.600 110.800 81.900 ;
        RECT 95.600 81.100 110.800 81.600 ;
        RECT 116.150 80.950 117.850 82.550 ;
        RECT 38.300 80.000 39.000 80.100 ;
        RECT 38.300 79.500 49.400 80.000 ;
        RECT 38.300 79.400 39.000 79.500 ;
        RECT 41.700 77.700 43.250 78.700 ;
        RECT 44.550 77.400 45.750 78.700 ;
        RECT 46.000 76.150 46.700 76.850 ;
        RECT 48.850 76.250 49.400 79.500 ;
        RECT 49.850 79.250 50.550 79.950 ;
        RECT 75.250 78.850 76.200 79.950 ;
        RECT 57.000 77.200 57.700 77.900 ;
        RECT 74.700 77.250 75.300 77.950 ;
        RECT 86.350 77.800 87.550 79.100 ;
        RECT 108.300 77.800 108.800 80.300 ;
        RECT 116.150 77.900 117.850 79.500 ;
        RECT 91.450 77.300 108.800 77.800 ;
        RECT 78.900 76.450 84.200 77.150 ;
        RECT 48.850 75.750 57.600 76.250 ;
        RECT 68.250 75.900 68.750 76.350 ;
        RECT 42.400 73.650 43.050 74.350 ;
        RECT 57.000 73.500 57.600 75.750 ;
        RECT 66.350 75.400 68.750 75.900 ;
        RECT 35.750 72.000 36.950 73.300 ;
        RECT 57.000 72.800 57.700 73.500 ;
        RECT 35.800 68.100 37.000 69.400 ;
        RECT 39.850 69.150 41.150 72.300 ;
        RECT 44.500 71.100 45.700 72.400 ;
        RECT 52.060 71.150 56.760 71.900 ;
        RECT 60.350 70.950 63.750 72.450 ;
        RECT 47.810 69.050 56.810 69.200 ;
        RECT 47.800 68.250 56.810 69.050 ;
        RECT 47.810 68.200 56.810 68.250 ;
        RECT 37.050 64.800 38.200 66.050 ;
        RECT 35.100 61.450 36.300 62.750 ;
        RECT 48.700 62.150 49.100 62.550 ;
        RECT 66.350 62.000 66.900 75.400 ;
        RECT 70.850 74.550 71.350 76.450 ;
        RECT 78.900 74.550 79.500 76.450 ;
        RECT 70.850 74.000 79.500 74.550 ;
        RECT 77.200 72.350 79.400 73.600 ;
        RECT 83.350 71.000 84.200 76.450 ;
        RECT 86.350 75.350 87.550 76.650 ;
        RECT 131.150 76.450 133.700 77.250 ;
        RECT 112.100 75.100 112.600 76.200 ;
        RECT 112.100 74.550 114.150 75.100 ;
        RECT 101.250 73.700 102.250 74.400 ;
        RECT 103.400 73.700 104.400 74.400 ;
        RECT 97.950 72.450 102.310 73.400 ;
        RECT 113.600 71.550 114.150 74.550 ;
        RECT 116.150 72.900 117.850 74.500 ;
        RECT 131.150 71.000 132.350 76.450 ;
        RECT 83.350 70.350 132.350 71.000 ;
        RECT 83.350 70.300 84.200 70.350 ;
        RECT 68.450 68.200 71.450 69.100 ;
        RECT 76.550 68.000 79.950 68.850 ;
        RECT 70.850 65.400 80.150 66.100 ;
        RECT 50.150 60.300 50.450 61.700 ;
        RECT 53.150 60.300 53.450 61.700 ;
        RECT 66.350 61.500 68.650 62.000 ;
        RECT 35.250 58.350 36.450 59.650 ;
        RECT 35.500 55.000 36.700 56.300 ;
        RECT 48.400 55.350 48.950 55.900 ;
        RECT 50.200 54.150 50.400 60.300 ;
        RECT 51.400 55.350 51.950 55.900 ;
        RECT 53.200 54.150 53.400 60.300 ;
        RECT 62.850 59.650 63.450 60.200 ;
        RECT 63.900 59.350 64.700 59.450 ;
        RECT 66.350 59.350 66.900 61.500 ;
        RECT 68.150 61.150 68.650 61.500 ;
        RECT 70.850 60.950 71.350 65.400 ;
        RECT 79.450 64.700 80.150 65.400 ;
        RECT 97.100 65.200 98.500 66.300 ;
        RECT 79.550 64.450 80.100 64.700 ;
        RECT 79.550 63.850 135.900 64.450 ;
        RECT 81.850 62.050 83.050 63.350 ;
        RECT 84.350 62.300 95.100 62.850 ;
        RECT 75.050 59.800 75.900 60.650 ;
        RECT 79.750 59.650 80.450 60.350 ;
        RECT 63.900 58.850 66.900 59.350 ;
        RECT 84.350 59.100 84.950 62.300 ;
        RECT 87.300 60.400 90.000 60.950 ;
        RECT 94.600 60.300 95.100 62.300 ;
        RECT 94.600 59.750 95.550 60.300 ;
        RECT 96.050 59.700 96.850 60.400 ;
        RECT 63.900 58.700 64.700 58.850 ;
        RECT 54.400 55.350 54.950 55.900 ;
        RECT 38.150 53.050 39.150 54.000 ;
        RECT 47.400 53.150 56.950 54.150 ;
        RECT 58.250 51.650 60.200 52.950 ;
        RECT 66.350 51.000 66.900 58.850 ;
        RECT 73.750 58.550 84.950 59.100 ;
        RECT 86.000 58.150 87.200 58.700 ;
        RECT 88.150 57.750 88.750 58.300 ;
        RECT 90.850 57.900 91.400 58.450 ;
        RECT 68.200 55.450 71.700 56.450 ;
        RECT 74.750 55.900 75.300 56.600 ;
        RECT 87.300 55.600 90.000 56.300 ;
        RECT 95.100 55.350 96.650 56.350 ;
        RECT 77.200 51.250 78.100 52.000 ;
        RECT 66.350 50.500 68.650 51.000 ;
        RECT 68.150 50.150 68.650 50.500 ;
        RECT 43.000 47.600 46.700 48.350 ;
        RECT 49.500 47.000 50.200 47.700 ;
        RECT 51.500 47.000 52.200 47.700 ;
        RECT 70.850 46.500 71.350 50.950 ;
        RECT 80.500 50.350 81.000 50.850 ;
        RECT 70.850 46.000 80.950 46.500 ;
        RECT 81.900 46.150 83.100 47.450 ;
        RECT 80.250 43.750 80.950 46.000 ;
        RECT 68.250 42.700 71.650 43.500 ;
        RECT 80.250 43.050 84.000 43.750 ;
        RECT 44.500 38.700 45.200 39.400 ;
        RECT 50.000 38.700 50.700 39.400 ;
        RECT 55.400 38.700 56.100 39.400 ;
        RECT 61.000 38.700 61.700 39.400 ;
        RECT 77.100 38.750 80.700 39.450 ;
        RECT 50.550 36.450 56.700 37.900 ;
      LAYER met2 ;
        RECT 13.550 199.550 14.600 199.600 ;
        RECT 104.850 199.550 105.800 202.100 ;
        RECT 13.550 198.650 105.800 199.550 ;
        RECT 13.550 76.850 14.600 198.650 ;
        RECT 104.850 198.300 105.800 198.650 ;
        RECT 107.600 195.150 108.550 197.300 ;
        RECT 17.500 194.250 108.550 195.150 ;
        RECT 17.550 79.950 18.500 194.250 ;
        RECT 107.600 193.500 108.550 194.250 ;
        RECT 110.400 191.150 111.350 192.950 ;
        RECT 19.600 190.250 111.350 191.150 ;
        RECT 19.600 82.650 20.600 190.250 ;
        RECT 110.400 189.150 111.350 190.250 ;
        RECT 113.050 186.950 114.000 189.350 ;
        RECT 21.600 186.050 114.050 186.950 ;
        RECT 21.600 84.650 22.550 186.050 ;
        RECT 113.050 185.550 114.000 186.050 ;
        RECT 115.900 183.950 116.850 186.300 ;
        RECT 23.900 183.050 116.850 183.950 ;
        RECT 23.900 86.950 24.850 183.050 ;
        RECT 115.900 182.500 116.850 183.050 ;
        RECT 41.550 180.550 74.950 181.500 ;
        RECT 41.550 151.100 42.350 180.550 ;
        RECT 77.200 176.400 78.150 181.500 ;
        RECT 48.750 175.550 78.150 176.400 ;
        RECT 45.750 154.700 48.050 155.900 ;
        RECT 48.750 147.800 49.550 175.550 ;
        RECT 59.150 171.050 80.100 172.000 ;
        RECT 54.150 154.700 56.450 155.900 ;
        RECT 50.850 149.900 53.250 151.000 ;
        RECT 59.150 147.800 60.100 171.050 ;
        RECT 82.700 167.800 83.650 181.000 ;
        RECT 69.800 167.000 83.650 167.800 ;
        RECT 65.850 154.700 68.150 155.900 ;
        RECT 61.550 149.900 63.950 151.000 ;
        RECT 69.800 147.800 70.650 167.000 ;
        RECT 85.550 164.150 86.500 181.500 ;
        RECT 88.300 173.800 89.250 182.100 ;
        RECT 97.600 182.050 98.850 182.100 ;
        RECT 93.800 181.100 98.850 182.050 ;
        RECT 97.600 180.550 98.850 181.100 ;
        RECT 91.050 179.300 94.850 180.250 ;
        RECT 97.600 179.700 115.900 180.550 ;
        RECT 94.000 175.750 94.750 179.300 ;
        RECT 94.000 175.150 102.550 175.750 ;
        RECT 88.300 173.000 92.150 173.800 ;
        RECT 80.550 163.200 86.500 164.150 ;
        RECT 75.250 154.700 77.550 155.900 ;
        RECT 72.250 149.900 74.650 151.000 ;
        RECT 80.550 147.800 81.500 163.200 ;
        RECT 87.050 154.700 89.350 155.900 ;
        RECT 82.950 149.900 85.350 151.000 ;
        RECT 91.250 147.800 92.150 173.000 ;
        RECT 97.550 154.700 99.850 155.900 ;
        RECT 93.650 149.900 96.050 151.000 ;
        RECT 101.950 147.800 102.550 175.150 ;
        RECT 104.350 149.900 106.750 151.000 ;
        RECT 48.750 147.000 51.650 147.800 ;
        RECT 59.150 147.000 62.350 147.800 ;
        RECT 69.800 147.000 73.050 147.800 ;
        RECT 37.950 146.400 38.550 147.000 ;
        RECT 46.550 146.400 47.150 147.000 ;
        RECT 57.250 146.400 57.850 147.000 ;
        RECT 67.950 146.400 68.550 147.000 ;
        RECT 78.650 146.400 79.250 147.000 ;
        RECT 80.550 146.950 83.750 147.800 ;
        RECT 91.250 147.000 94.450 147.800 ;
        RECT 101.950 147.000 105.150 147.800 ;
        RECT 114.950 147.650 115.900 179.700 ;
        RECT 115.050 147.000 115.850 147.650 ;
        RECT 89.350 146.400 89.950 147.000 ;
        RECT 100.050 146.400 100.650 147.000 ;
        RECT 110.750 146.400 111.350 147.000 ;
        RECT 51.150 141.500 53.450 142.700 ;
        RECT 61.850 141.500 64.150 142.700 ;
        RECT 72.550 141.500 74.850 142.700 ;
        RECT 83.250 141.500 85.550 142.700 ;
        RECT 93.950 141.500 96.250 142.700 ;
        RECT 104.650 141.500 106.950 142.700 ;
        RECT 36.750 138.200 37.350 138.400 ;
        RECT 39.550 138.200 40.150 138.800 ;
        RECT 36.750 138.000 39.850 138.200 ;
        RECT 36.750 137.800 37.350 138.000 ;
        RECT 40.450 137.800 41.050 138.400 ;
        RECT 45.350 138.200 45.950 138.400 ;
        RECT 48.150 138.200 48.750 138.800 ;
        RECT 45.350 138.000 48.450 138.200 ;
        RECT 45.350 137.800 45.950 138.000 ;
        RECT 49.050 137.800 49.650 138.400 ;
        RECT 56.050 138.200 56.650 138.400 ;
        RECT 58.850 138.200 59.450 138.800 ;
        RECT 56.050 138.000 59.150 138.200 ;
        RECT 56.050 137.800 56.650 138.000 ;
        RECT 59.750 137.800 60.350 138.400 ;
        RECT 66.750 138.200 67.350 138.400 ;
        RECT 69.550 138.200 70.150 138.800 ;
        RECT 66.750 138.000 69.850 138.200 ;
        RECT 66.750 137.800 67.350 138.000 ;
        RECT 70.450 137.800 71.050 138.400 ;
        RECT 77.450 138.200 78.050 138.400 ;
        RECT 80.250 138.200 80.850 138.800 ;
        RECT 77.450 138.000 80.550 138.200 ;
        RECT 77.450 137.800 78.050 138.000 ;
        RECT 81.150 137.800 81.750 138.400 ;
        RECT 88.150 138.200 88.750 138.400 ;
        RECT 90.950 138.200 91.550 138.800 ;
        RECT 88.150 138.000 91.250 138.200 ;
        RECT 88.150 137.800 88.750 138.000 ;
        RECT 91.850 137.800 92.450 138.400 ;
        RECT 98.850 138.200 99.450 138.400 ;
        RECT 101.650 138.200 102.250 138.800 ;
        RECT 98.850 138.000 101.950 138.200 ;
        RECT 98.850 137.800 99.450 138.000 ;
        RECT 102.550 137.800 103.150 138.400 ;
        RECT 109.550 138.200 110.150 138.400 ;
        RECT 112.350 138.200 112.950 138.800 ;
        RECT 109.550 138.000 112.650 138.200 ;
        RECT 109.550 137.800 110.150 138.000 ;
        RECT 113.250 137.800 113.850 138.400 ;
        RECT 36.950 136.500 37.150 137.800 ;
        RECT 36.950 136.300 37.950 136.500 ;
        RECT 37.750 132.700 37.950 136.300 ;
        RECT 40.650 136.400 40.850 137.800 ;
        RECT 45.550 136.500 45.750 137.800 ;
        RECT 40.650 136.200 41.650 136.400 ;
        RECT 45.550 136.300 46.550 136.500 ;
        RECT 38.150 133.300 38.650 133.400 ;
        RECT 38.150 133.200 40.850 133.300 ;
        RECT 38.150 133.000 41.050 133.200 ;
        RECT 38.150 132.900 38.650 133.000 ;
        RECT 37.550 132.100 38.150 132.700 ;
        RECT 40.450 132.600 41.050 133.000 ;
        RECT 41.450 132.700 41.650 136.200 ;
        RECT 46.350 132.700 46.550 136.300 ;
        RECT 49.250 136.400 49.450 137.800 ;
        RECT 56.250 136.500 56.450 137.800 ;
        RECT 49.250 136.200 50.250 136.400 ;
        RECT 56.250 136.300 57.250 136.500 ;
        RECT 46.750 133.300 47.250 133.400 ;
        RECT 46.750 133.200 49.450 133.300 ;
        RECT 46.750 133.000 49.650 133.200 ;
        RECT 46.750 132.900 47.250 133.000 ;
        RECT 41.250 132.100 41.850 132.700 ;
        RECT 46.150 132.100 46.750 132.700 ;
        RECT 49.050 132.600 49.650 133.000 ;
        RECT 50.050 132.700 50.250 136.200 ;
        RECT 50.750 135.000 53.150 136.100 ;
        RECT 57.050 132.700 57.250 136.300 ;
        RECT 59.950 136.400 60.150 137.800 ;
        RECT 66.950 136.500 67.150 137.800 ;
        RECT 59.950 136.200 60.950 136.400 ;
        RECT 66.950 136.300 67.950 136.500 ;
        RECT 57.450 133.300 57.950 133.400 ;
        RECT 57.450 133.200 60.150 133.300 ;
        RECT 57.450 133.000 60.350 133.200 ;
        RECT 57.450 132.900 57.950 133.000 ;
        RECT 49.850 132.100 50.450 132.700 ;
        RECT 56.850 132.100 57.450 132.700 ;
        RECT 59.750 132.600 60.350 133.000 ;
        RECT 60.750 132.700 60.950 136.200 ;
        RECT 61.450 135.000 63.850 136.100 ;
        RECT 67.750 132.700 67.950 136.300 ;
        RECT 70.650 136.400 70.850 137.800 ;
        RECT 77.650 136.500 77.850 137.800 ;
        RECT 70.650 136.200 71.650 136.400 ;
        RECT 77.650 136.300 78.650 136.500 ;
        RECT 68.150 133.300 68.650 133.400 ;
        RECT 68.150 133.200 70.850 133.300 ;
        RECT 68.150 133.000 71.050 133.200 ;
        RECT 68.150 132.900 68.650 133.000 ;
        RECT 60.550 132.100 61.150 132.700 ;
        RECT 67.550 132.100 68.150 132.700 ;
        RECT 70.450 132.600 71.050 133.000 ;
        RECT 71.450 132.700 71.650 136.200 ;
        RECT 72.150 135.000 74.550 136.100 ;
        RECT 78.450 132.700 78.650 136.300 ;
        RECT 81.350 136.400 81.550 137.800 ;
        RECT 88.350 136.500 88.550 137.800 ;
        RECT 81.350 136.200 82.350 136.400 ;
        RECT 88.350 136.300 89.350 136.500 ;
        RECT 78.850 133.300 79.350 133.400 ;
        RECT 78.850 133.200 81.550 133.300 ;
        RECT 78.850 133.000 81.750 133.200 ;
        RECT 78.850 132.900 79.350 133.000 ;
        RECT 71.250 132.100 71.850 132.700 ;
        RECT 78.250 132.100 78.850 132.700 ;
        RECT 81.150 132.600 81.750 133.000 ;
        RECT 82.150 132.700 82.350 136.200 ;
        RECT 82.850 135.000 85.250 136.100 ;
        RECT 89.150 132.700 89.350 136.300 ;
        RECT 92.050 136.400 92.250 137.800 ;
        RECT 99.050 136.500 99.250 137.800 ;
        RECT 92.050 136.200 93.050 136.400 ;
        RECT 99.050 136.300 100.050 136.500 ;
        RECT 89.550 133.300 90.050 133.400 ;
        RECT 89.550 133.200 92.250 133.300 ;
        RECT 89.550 133.000 92.450 133.200 ;
        RECT 89.550 132.900 90.050 133.000 ;
        RECT 81.950 132.100 82.550 132.700 ;
        RECT 88.950 132.100 89.550 132.700 ;
        RECT 91.850 132.600 92.450 133.000 ;
        RECT 92.850 132.700 93.050 136.200 ;
        RECT 93.550 135.000 95.950 136.100 ;
        RECT 99.850 132.700 100.050 136.300 ;
        RECT 102.750 136.400 102.950 137.800 ;
        RECT 109.750 136.500 109.950 137.800 ;
        RECT 102.750 136.200 103.750 136.400 ;
        RECT 109.750 136.300 110.750 136.500 ;
        RECT 100.250 133.300 100.750 133.400 ;
        RECT 100.250 133.200 102.950 133.300 ;
        RECT 100.250 133.000 103.150 133.200 ;
        RECT 100.250 132.900 100.750 133.000 ;
        RECT 92.650 132.100 93.250 132.700 ;
        RECT 99.650 132.100 100.250 132.700 ;
        RECT 102.550 132.600 103.150 133.000 ;
        RECT 103.550 132.700 103.750 136.200 ;
        RECT 104.250 135.000 106.650 136.100 ;
        RECT 110.550 132.700 110.750 136.300 ;
        RECT 113.450 136.400 113.650 137.800 ;
        RECT 113.450 136.200 114.450 136.400 ;
        RECT 110.950 133.300 111.450 133.400 ;
        RECT 110.950 133.200 113.650 133.300 ;
        RECT 110.950 133.000 113.850 133.200 ;
        RECT 110.950 132.900 111.450 133.000 ;
        RECT 103.350 132.100 103.950 132.700 ;
        RECT 110.350 132.100 110.950 132.700 ;
        RECT 113.250 132.600 113.850 133.000 ;
        RECT 114.250 132.700 114.450 136.200 ;
        RECT 114.050 132.100 114.650 132.700 ;
        RECT 37.750 130.800 37.950 132.100 ;
        RECT 46.350 130.800 46.550 132.100 ;
        RECT 57.050 130.800 57.250 132.100 ;
        RECT 67.750 130.800 67.950 132.100 ;
        RECT 78.450 130.800 78.650 132.100 ;
        RECT 89.150 130.800 89.350 132.100 ;
        RECT 99.850 130.800 100.050 132.100 ;
        RECT 110.550 130.800 110.750 132.100 ;
        RECT 35.150 130.600 37.950 130.800 ;
        RECT 43.750 130.600 46.550 130.800 ;
        RECT 54.450 130.600 57.250 130.800 ;
        RECT 65.150 130.600 67.950 130.800 ;
        RECT 75.850 130.600 78.650 130.800 ;
        RECT 86.550 130.600 89.350 130.800 ;
        RECT 97.250 130.600 100.050 130.800 ;
        RECT 107.950 130.600 110.750 130.800 ;
        RECT 35.150 126.100 35.350 130.600 ;
        RECT 43.750 126.100 43.950 130.600 ;
        RECT 50.550 128.300 52.850 129.500 ;
        RECT 54.450 126.100 54.650 130.600 ;
        RECT 61.150 128.300 63.450 129.500 ;
        RECT 65.150 126.100 65.350 130.600 ;
        RECT 72.050 128.300 74.350 129.500 ;
        RECT 75.850 126.100 76.050 130.600 ;
        RECT 82.450 128.300 84.750 129.500 ;
        RECT 86.550 126.100 86.750 130.600 ;
        RECT 93.050 128.300 95.350 129.500 ;
        RECT 97.250 126.100 97.450 130.600 ;
        RECT 103.850 128.300 106.150 129.500 ;
        RECT 107.950 126.100 108.150 130.600 ;
        RECT 34.950 125.500 35.550 126.100 ;
        RECT 32.850 125.200 33.750 125.400 ;
        RECT 35.850 125.200 36.450 125.600 ;
        RECT 32.850 125.000 36.450 125.200 ;
        RECT 39.550 125.000 40.150 125.600 ;
        RECT 43.550 125.500 44.150 126.100 ;
        RECT 44.450 125.200 45.050 125.600 ;
        RECT 42.050 125.000 45.050 125.200 ;
        RECT 48.150 125.000 48.750 125.600 ;
        RECT 54.250 125.500 54.850 126.100 ;
        RECT 55.150 125.200 55.750 125.600 ;
        RECT 53.050 125.000 55.750 125.200 ;
        RECT 58.850 125.000 59.450 125.600 ;
        RECT 64.950 125.500 65.550 126.100 ;
        RECT 65.850 125.200 66.450 125.600 ;
        RECT 63.750 125.000 66.450 125.200 ;
        RECT 69.550 125.000 70.150 125.600 ;
        RECT 75.650 125.500 76.250 126.100 ;
        RECT 76.550 125.200 77.150 125.600 ;
        RECT 74.450 125.000 77.150 125.200 ;
        RECT 80.250 125.000 80.850 125.600 ;
        RECT 86.350 125.500 86.950 126.100 ;
        RECT 87.250 125.200 87.850 125.600 ;
        RECT 85.150 125.000 87.850 125.200 ;
        RECT 90.950 125.000 91.550 125.600 ;
        RECT 97.050 125.500 97.650 126.100 ;
        RECT 97.950 125.200 98.550 125.600 ;
        RECT 95.850 125.000 98.550 125.200 ;
        RECT 101.650 125.000 102.250 125.600 ;
        RECT 107.750 125.500 108.350 126.100 ;
        RECT 108.650 125.200 109.250 125.600 ;
        RECT 106.550 125.000 109.250 125.200 ;
        RECT 112.350 125.000 112.950 125.600 ;
        RECT 32.850 124.500 33.750 125.000 ;
        RECT 34.350 123.400 34.550 125.000 ;
        RECT 42.050 123.400 42.250 125.000 ;
        RECT 53.050 123.400 53.250 125.000 ;
        RECT 63.750 123.400 63.950 125.000 ;
        RECT 74.450 123.400 74.650 125.000 ;
        RECT 85.150 123.400 85.350 125.000 ;
        RECT 95.850 123.400 96.050 125.000 ;
        RECT 106.550 123.400 106.750 125.000 ;
        RECT 34.350 123.200 106.750 123.400 ;
        RECT 42.850 121.800 45.250 122.900 ;
        RECT 51.650 121.800 54.050 122.900 ;
        RECT 62.250 121.800 64.650 122.900 ;
        RECT 72.950 121.800 75.350 122.900 ;
        RECT 84.150 121.800 86.550 122.900 ;
        RECT 94.650 121.800 97.050 122.900 ;
        RECT 105.450 121.800 107.850 122.900 ;
        RECT 103.000 119.300 104.550 120.650 ;
        RECT 140.500 118.950 141.800 124.000 ;
        RECT 96.160 91.900 107.510 93.000 ;
        RECT 47.510 89.400 54.910 89.600 ;
        RECT 47.500 88.650 54.910 89.400 ;
        RECT 47.500 88.450 54.900 88.650 ;
        RECT 62.950 88.050 64.150 89.350 ;
        RECT 68.800 87.750 70.000 89.050 ;
        RECT 74.600 87.950 75.800 89.250 ;
        RECT 23.900 86.250 56.950 86.950 ;
        RECT 95.800 86.750 107.000 87.650 ;
        RECT 95.850 85.650 96.800 86.750 ;
        RECT 106.300 86.000 107.000 86.750 ;
        RECT 116.150 86.300 117.850 87.900 ;
        RECT 60.950 84.950 96.800 85.650 ;
        RECT 105.100 85.500 105.600 86.000 ;
        RECT 106.300 85.500 107.250 86.000 ;
        RECT 21.600 83.950 54.650 84.650 ;
        RECT 56.850 83.150 81.350 83.750 ;
        RECT 19.600 81.950 52.650 82.650 ;
        RECT 17.550 79.250 50.600 79.950 ;
        RECT 41.700 77.700 43.250 78.700 ;
        RECT 44.550 77.400 45.750 78.700 ;
        RECT 57.000 77.200 57.700 83.150 ;
        RECT 80.900 82.350 81.350 83.150 ;
        RECT 68.000 81.100 71.900 82.000 ;
        RECT 76.100 80.900 77.300 82.200 ;
        RECT 79.000 81.650 81.350 82.350 ;
        RECT 84.600 82.050 86.200 84.100 ;
        RECT 75.250 78.850 76.200 79.950 ;
        RECT 74.700 77.250 75.300 77.950 ;
        RECT 13.550 76.150 46.700 76.850 ;
        RECT 78.900 76.450 79.500 77.150 ;
        RECT 42.400 74.250 43.050 74.350 ;
        RECT 42.400 73.750 44.150 74.250 ;
        RECT 42.400 73.650 43.050 73.750 ;
        RECT 35.750 72.000 36.950 73.300 ;
        RECT 57.000 72.800 57.700 73.500 ;
        RECT 35.800 68.100 37.000 69.400 ;
        RECT 39.850 69.150 41.150 72.300 ;
        RECT 44.500 71.100 45.700 72.400 ;
        RECT 52.050 71.050 56.800 71.900 ;
        RECT 60.350 70.950 63.750 72.450 ;
        RECT 77.200 72.350 79.400 73.600 ;
        RECT 47.810 68.200 56.810 69.200 ;
        RECT 68.450 68.200 71.450 69.100 ;
        RECT 76.550 68.000 79.950 68.850 ;
        RECT 37.050 64.800 38.200 66.050 ;
        RECT 79.450 64.700 80.150 65.400 ;
        RECT 35.100 61.450 36.300 62.750 ;
        RECT 48.700 62.150 63.450 62.550 ;
        RECT 62.850 59.650 63.450 62.150 ;
        RECT 75.050 59.800 75.900 60.650 ;
        RECT 80.900 60.350 81.350 81.650 ;
        RECT 82.050 65.600 82.950 81.500 ;
        RECT 86.350 77.800 87.550 79.100 ;
        RECT 86.350 75.350 87.550 76.650 ;
        RECT 87.100 68.650 91.900 69.650 ;
        RECT 95.850 69.300 96.800 84.950 ;
        RECT 99.600 84.300 100.100 84.400 ;
        RECT 105.200 84.300 105.500 85.500 ;
        RECT 106.300 85.400 107.000 85.500 ;
        RECT 99.600 84.000 105.500 84.300 ;
        RECT 99.600 83.900 100.100 84.000 ;
        RECT 116.150 83.500 117.850 85.100 ;
        RECT 116.150 80.950 117.850 82.550 ;
        RECT 116.150 77.900 117.850 79.500 ;
        RECT 101.250 73.700 102.250 74.400 ;
        RECT 103.400 73.700 104.400 74.400 ;
        RECT 97.950 72.450 102.310 73.400 ;
        RECT 113.600 71.550 114.150 73.350 ;
        RECT 116.150 72.900 117.850 74.500 ;
        RECT 81.850 62.050 83.050 63.350 ;
        RECT 87.300 60.400 90.050 68.650 ;
        RECT 93.400 68.600 96.800 69.300 ;
        RECT 79.750 59.650 81.350 60.350 ;
        RECT 93.400 59.900 94.100 68.600 ;
        RECT 97.100 65.200 98.500 66.300 ;
        RECT 35.250 58.350 36.450 59.650 ;
        RECT 35.500 55.000 36.700 56.300 ;
        RECT 42.800 55.750 48.950 55.900 ;
        RECT 51.400 55.750 51.950 55.900 ;
        RECT 54.400 55.750 54.950 55.900 ;
        RECT 42.800 55.500 54.950 55.750 ;
        RECT 42.800 55.350 48.950 55.500 ;
        RECT 51.400 55.350 51.950 55.500 ;
        RECT 54.400 55.350 54.950 55.500 ;
        RECT 68.200 55.450 71.700 56.450 ;
        RECT 74.750 55.900 75.300 56.600 ;
        RECT 38.150 53.050 39.150 54.000 ;
        RECT 42.800 50.500 43.350 55.350 ;
        RECT 48.160 53.150 56.260 54.100 ;
        RECT 58.250 51.650 60.200 52.950 ;
        RECT 77.200 51.250 78.100 52.000 ;
        RECT 80.900 51.500 81.350 59.650 ;
        RECT 88.200 59.350 94.100 59.900 ;
        RECT 96.050 59.700 96.850 60.400 ;
        RECT 86.000 58.150 87.200 58.700 ;
        RECT 88.200 58.300 88.750 59.350 ;
        RECT 88.150 57.750 88.750 58.300 ;
        RECT 90.850 57.900 91.400 58.450 ;
        RECT 88.200 57.550 88.750 57.750 ;
        RECT 84.600 57.000 88.750 57.550 ;
        RECT 87.300 55.600 90.000 56.300 ;
        RECT 95.100 55.350 96.650 56.350 ;
        RECT 80.500 51.050 81.350 51.500 ;
        RECT 45.450 50.500 46.000 50.600 ;
        RECT 49.500 50.500 50.200 50.550 ;
        RECT 42.800 49.900 50.200 50.500 ;
        RECT 80.500 50.350 81.000 51.050 ;
        RECT 43.000 47.600 46.700 48.350 ;
        RECT 49.500 47.000 50.200 49.900 ;
        RECT 51.500 47.000 52.200 47.700 ;
        RECT 81.900 46.150 83.100 47.450 ;
        RECT 68.250 42.700 71.650 43.500 ;
        RECT 80.250 43.050 80.950 43.750 ;
        RECT 81.950 43.050 84.000 43.750 ;
        RECT 44.500 39.350 45.200 39.400 ;
        RECT 50.000 39.350 50.700 39.400 ;
        RECT 44.450 39.200 45.200 39.350 ;
        RECT 47.150 39.200 50.700 39.350 ;
        RECT 55.400 39.300 56.100 39.400 ;
        RECT 61.000 39.300 61.700 39.400 ;
        RECT 44.450 38.900 45.900 39.200 ;
        RECT 47.150 38.900 51.400 39.200 ;
        RECT 44.450 30.100 45.200 38.900 ;
        RECT 47.150 38.700 50.700 38.900 ;
        RECT 55.400 38.700 59.150 39.300 ;
        RECT 61.000 38.700 62.400 39.300 ;
        RECT 77.100 38.750 80.700 39.450 ;
        RECT 47.150 31.650 47.950 38.700 ;
        RECT 50.500 36.450 56.700 37.900 ;
        RECT 58.500 33.100 59.150 38.700 ;
        RECT 61.750 34.950 62.400 38.700 ;
        RECT 121.450 34.950 122.400 106.950 ;
        RECT 61.750 34.200 122.400 34.950 ;
        RECT 124.350 33.100 125.300 107.000 ;
        RECT 58.500 32.400 125.300 33.100 ;
        RECT 127.050 31.650 128.000 107.050 ;
        RECT 47.150 31.000 128.000 31.650 ;
        RECT 129.500 30.100 130.450 107.100 ;
        RECT 131.300 76.450 133.700 77.250 ;
        RECT 132.750 63.850 135.900 64.450 ;
        RECT 44.450 29.400 130.450 30.100 ;
      LAYER met3 ;
        RECT 104.850 198.300 105.800 202.100 ;
        RECT 107.600 193.500 108.550 197.300 ;
        RECT 110.400 189.150 111.350 192.950 ;
        RECT 113.050 185.550 114.000 189.350 ;
        RECT 115.900 182.500 116.850 186.300 ;
        RECT 71.150 180.550 74.950 181.500 ;
        RECT 77.200 177.700 78.150 181.500 ;
        RECT 82.700 177.200 83.650 181.000 ;
        RECT 85.550 177.700 86.500 181.500 ;
        RECT 88.300 178.300 89.250 182.100 ;
        RECT 93.800 181.100 97.600 182.050 ;
        RECT 91.050 179.300 94.850 180.250 ;
        RECT 76.300 171.050 80.100 172.000 ;
        RECT 1.150 155.900 2.900 156.400 ;
        RECT 1.150 154.650 48.050 155.900 ;
        RECT 54.150 154.700 56.450 155.900 ;
        RECT 65.850 154.700 68.150 155.900 ;
        RECT 75.250 154.700 77.550 155.900 ;
        RECT 87.050 154.700 89.350 155.900 ;
        RECT 97.550 154.700 99.850 155.900 ;
        RECT 1.150 154.100 2.900 154.650 ;
        RECT 43.800 154.600 48.050 154.650 ;
        RECT 50.850 149.900 53.250 151.000 ;
        RECT 61.550 149.900 63.950 151.000 ;
        RECT 72.250 149.900 74.650 151.000 ;
        RECT 82.950 149.900 85.350 151.000 ;
        RECT 93.650 149.900 96.050 151.000 ;
        RECT 104.350 149.900 106.750 151.000 ;
        RECT 37.950 146.400 38.550 147.000 ;
        RECT 46.550 146.400 47.150 147.000 ;
        RECT 57.250 146.400 57.850 147.000 ;
        RECT 67.950 146.400 68.550 147.000 ;
        RECT 78.650 146.400 79.250 147.000 ;
        RECT 89.350 146.400 89.950 147.000 ;
        RECT 100.050 146.400 100.650 147.000 ;
        RECT 110.750 146.400 111.350 147.000 ;
        RECT 1.150 142.700 2.900 143.450 ;
        RECT 1.150 141.500 33.750 142.700 ;
        RECT 1.150 140.750 2.900 141.500 ;
        RECT 1.100 129.500 2.900 130.550 ;
        RECT 1.100 128.300 33.950 129.500 ;
        RECT 1.100 127.050 2.900 128.300 ;
        RECT 38.150 125.400 38.450 146.400 ;
        RECT 39.550 125.400 40.150 125.600 ;
        RECT 32.850 102.700 33.750 125.400 ;
        RECT 38.150 125.100 40.150 125.400 ;
        RECT 46.750 125.400 47.050 146.400 ;
        RECT 51.150 141.500 53.450 142.700 ;
        RECT 50.750 136.100 53.050 136.200 ;
        RECT 50.750 135.000 53.150 136.100 ;
        RECT 50.550 128.300 52.850 129.500 ;
        RECT 48.150 125.400 48.750 125.600 ;
        RECT 46.750 125.100 48.750 125.400 ;
        RECT 57.450 125.400 57.750 146.400 ;
        RECT 61.850 141.500 64.150 142.700 ;
        RECT 61.450 135.000 63.850 136.100 ;
        RECT 61.150 128.300 63.450 129.500 ;
        RECT 58.850 125.400 59.450 125.600 ;
        RECT 57.450 125.100 59.450 125.400 ;
        RECT 68.150 125.400 68.450 146.400 ;
        RECT 72.550 141.500 74.850 142.700 ;
        RECT 72.150 135.000 74.550 136.100 ;
        RECT 72.050 128.300 74.350 129.500 ;
        RECT 69.550 125.400 70.150 125.600 ;
        RECT 68.150 125.100 70.150 125.400 ;
        RECT 78.850 125.400 79.150 146.400 ;
        RECT 83.250 141.500 85.550 142.700 ;
        RECT 82.850 135.000 85.250 136.100 ;
        RECT 82.450 128.300 84.750 129.500 ;
        RECT 80.250 125.400 80.850 125.600 ;
        RECT 78.850 125.100 80.850 125.400 ;
        RECT 89.550 125.400 89.850 146.400 ;
        RECT 93.950 141.500 96.250 142.700 ;
        RECT 93.550 135.000 95.950 136.100 ;
        RECT 93.050 128.300 95.350 129.500 ;
        RECT 90.950 125.400 91.550 125.600 ;
        RECT 89.550 125.100 91.550 125.400 ;
        RECT 100.250 125.400 100.550 146.400 ;
        RECT 104.650 141.500 106.950 142.700 ;
        RECT 104.250 136.100 106.550 136.200 ;
        RECT 104.250 135.000 106.650 136.100 ;
        RECT 103.850 128.300 106.150 129.500 ;
        RECT 101.650 125.400 102.250 125.600 ;
        RECT 100.250 125.100 102.250 125.400 ;
        RECT 110.950 125.400 111.250 146.400 ;
        RECT 112.350 125.400 112.950 125.600 ;
        RECT 110.950 125.100 112.950 125.400 ;
        RECT 39.550 125.000 40.150 125.100 ;
        RECT 48.150 125.000 48.750 125.100 ;
        RECT 58.850 125.000 59.450 125.100 ;
        RECT 69.550 125.000 70.150 125.100 ;
        RECT 80.250 125.000 80.850 125.100 ;
        RECT 90.950 125.000 91.550 125.100 ;
        RECT 101.650 125.000 102.250 125.100 ;
        RECT 112.350 125.000 112.950 125.100 ;
        RECT 51.650 122.900 53.950 123.000 ;
        RECT 105.450 122.900 107.750 123.000 ;
        RECT 42.850 121.800 45.250 122.900 ;
        RECT 51.650 121.800 54.050 122.900 ;
        RECT 62.250 121.800 64.650 122.900 ;
        RECT 72.950 121.800 75.350 122.900 ;
        RECT 84.150 121.800 86.550 122.900 ;
        RECT 94.650 121.800 97.050 122.900 ;
        RECT 105.450 121.800 107.850 122.900 ;
        RECT 103.000 118.950 120.200 120.800 ;
        RECT 140.500 118.950 141.800 124.000 ;
        RECT 32.850 101.850 82.950 102.700 ;
        RECT 30.200 73.050 31.300 95.600 ;
        RECT 47.500 88.450 54.900 89.400 ;
        RECT 62.950 88.050 64.150 89.350 ;
        RECT 68.800 87.750 70.000 89.050 ;
        RECT 74.600 87.950 75.800 89.250 ;
        RECT 43.650 84.950 63.150 85.650 ;
        RECT 41.700 77.700 43.250 78.700 ;
        RECT 43.650 73.750 44.150 84.950 ;
        RECT 68.000 81.100 71.900 82.000 ;
        RECT 76.100 80.900 77.300 82.200 ;
        RECT 82.050 81.000 82.950 101.850 ;
        RECT 96.160 91.900 117.900 93.000 ;
        RECT 106.300 85.400 107.000 86.100 ;
        RECT 84.250 82.300 86.550 84.100 ;
        RECT 84.250 82.050 86.200 82.300 ;
        RECT 75.250 78.850 76.200 79.950 ;
        RECT 44.550 77.400 45.750 78.700 ;
        RECT 1.150 71.200 2.950 72.100 ;
        RECT 30.200 71.850 31.250 73.050 ;
        RECT 35.750 72.000 36.950 73.300 ;
        RECT 39.850 71.200 41.150 72.300 ;
        RECT 1.150 70.200 41.150 71.200 ;
        RECT 44.500 71.100 45.700 72.400 ;
        RECT 60.350 72.200 65.850 72.450 ;
        RECT 59.050 72.000 65.850 72.200 ;
        RECT 54.600 71.900 65.850 72.000 ;
        RECT 52.050 71.100 65.850 71.900 ;
        RECT 1.150 69.250 2.950 70.200 ;
        RECT 30.200 66.050 31.250 68.850 ;
        RECT 35.800 68.100 37.000 69.400 ;
        RECT 39.850 69.150 41.150 70.200 ;
        RECT 51.150 70.950 65.850 71.100 ;
        RECT 51.150 69.200 55.950 70.950 ;
        RECT 64.750 69.200 65.850 70.950 ;
        RECT 77.200 69.650 79.400 73.600 ;
        RECT 84.250 73.400 85.450 82.050 ;
        RECT 86.350 77.800 87.550 79.100 ;
        RECT 86.350 75.350 87.550 76.650 ;
        RECT 101.250 73.700 102.250 74.400 ;
        RECT 103.400 73.700 104.400 74.400 ;
        RECT 84.250 72.450 103.500 73.400 ;
        RECT 97.100 69.650 98.150 72.450 ;
        RECT 113.600 72.200 114.150 73.350 ;
        RECT 116.150 72.900 117.850 91.900 ;
        RECT 118.650 72.200 120.200 118.950 ;
        RECT 121.450 102.800 122.400 106.950 ;
        RECT 124.350 102.850 125.300 107.000 ;
        RECT 127.050 102.900 128.000 107.050 ;
        RECT 129.500 102.950 130.450 107.100 ;
        RECT 132.350 77.250 133.300 107.050 ;
        RECT 131.250 76.450 133.700 77.250 ;
        RECT 113.600 71.550 120.200 72.200 ;
        RECT 77.200 69.600 98.150 69.650 ;
        RECT 73.000 69.200 98.150 69.600 ;
        RECT 47.810 69.150 56.810 69.200 ;
        RECT 39.850 68.250 56.810 69.150 ;
        RECT 47.810 68.200 56.810 68.250 ;
        RECT 64.750 68.650 98.150 69.200 ;
        RECT 64.750 68.550 80.000 68.650 ;
        RECT 64.750 68.100 74.350 68.550 ;
        RECT 69.400 68.050 74.350 68.100 ;
        RECT 76.550 68.000 80.000 68.550 ;
        RECT 97.100 66.300 98.150 68.650 ;
        RECT 30.200 64.800 38.200 66.050 ;
        RECT 82.050 65.600 91.950 66.300 ;
        RECT 35.100 61.450 36.300 62.750 ;
        RECT 35.250 58.350 36.450 59.650 ;
        RECT 37.150 58.850 38.200 64.800 ;
        RECT 81.850 62.050 83.050 63.350 ;
        RECT 75.050 59.800 75.900 60.650 ;
        RECT 87.300 60.400 90.000 60.950 ;
        RECT 37.150 58.050 87.200 58.850 ;
        RECT 91.300 58.450 91.950 65.600 ;
        RECT 97.100 65.200 98.500 66.300 ;
        RECT 118.650 60.650 120.200 71.550 ;
        RECT 135.100 64.450 136.050 107.100 ;
        RECT 132.750 63.850 136.050 64.450 ;
        RECT 96.750 60.600 120.200 60.650 ;
        RECT 96.050 59.500 120.200 60.600 ;
        RECT 118.650 59.450 120.200 59.500 ;
        RECT 90.850 57.900 91.950 58.450 ;
        RECT 35.500 55.000 36.700 56.300 ;
        RECT 68.200 55.450 71.700 56.450 ;
        RECT 74.750 55.900 75.300 56.600 ;
        RECT 38.150 51.600 39.150 54.000 ;
        RECT 48.160 53.150 56.260 54.100 ;
        RECT 58.250 51.650 60.200 52.950 ;
        RECT 38.150 50.900 53.350 51.600 ;
        RECT 77.200 51.250 78.100 52.000 ;
        RECT 43.000 47.600 46.700 48.350 ;
        RECT 49.500 47.000 50.200 47.700 ;
        RECT 51.500 47.000 52.200 50.900 ;
        RECT 52.750 48.750 53.350 50.900 ;
        RECT 84.600 48.750 85.200 57.550 ;
        RECT 87.300 55.600 90.000 56.300 ;
        RECT 95.100 55.350 96.650 56.350 ;
        RECT 52.750 48.300 85.200 48.750 ;
        RECT 81.900 46.150 83.100 47.450 ;
        RECT 68.250 39.450 71.700 44.250 ;
        RECT 137.850 43.800 138.800 107.100 ;
        RECT 83.850 43.750 138.800 43.800 ;
        RECT 81.950 43.050 138.800 43.750 ;
        RECT 68.250 38.750 80.700 39.450 ;
        RECT 1.100 38.000 2.850 38.650 ;
        RECT 68.250 38.000 71.700 38.750 ;
        RECT 1.100 35.950 71.700 38.000 ;
        RECT 1.100 35.700 2.850 35.950 ;
      LAYER met4 ;
        RECT 74.550 224.760 74.830 225.750 ;
        RECT 75.130 224.760 75.500 225.750 ;
        RECT 74.550 181.500 75.500 224.760 ;
        RECT 71.150 180.550 75.500 181.500 ;
        RECT 77.200 224.760 77.590 225.750 ;
        RECT 77.890 224.760 78.150 225.750 ;
        RECT 77.200 177.700 78.150 224.760 ;
        RECT 79.950 224.760 80.350 225.750 ;
        RECT 80.650 224.760 80.950 225.750 ;
        RECT 79.950 172.000 80.950 224.760 ;
        RECT 82.700 224.760 83.110 225.750 ;
        RECT 83.410 224.760 83.650 225.750 ;
        RECT 82.700 177.200 83.650 224.760 ;
        RECT 85.550 224.760 85.870 225.750 ;
        RECT 86.170 224.760 86.500 225.750 ;
        RECT 85.550 177.700 86.500 224.760 ;
        RECT 88.300 224.760 88.630 225.750 ;
        RECT 88.930 224.760 89.250 225.750 ;
        RECT 88.300 178.300 89.250 224.760 ;
        RECT 91.050 224.760 91.390 225.750 ;
        RECT 91.690 224.760 92.000 225.750 ;
        RECT 91.050 180.250 92.000 224.760 ;
        RECT 93.800 224.760 94.150 225.750 ;
        RECT 94.450 224.760 94.750 225.750 ;
        RECT 93.800 182.050 94.750 224.760 ;
        RECT 104.800 224.760 105.190 225.750 ;
        RECT 105.490 224.760 105.800 225.750 ;
        RECT 104.800 198.300 105.800 224.760 ;
        RECT 107.600 224.760 107.950 225.750 ;
        RECT 108.250 224.760 108.550 225.750 ;
        RECT 107.600 193.500 108.550 224.760 ;
        RECT 110.400 224.760 110.710 225.750 ;
        RECT 111.010 224.760 111.350 225.750 ;
        RECT 110.400 189.150 111.350 224.760 ;
        RECT 113.050 224.760 113.470 225.750 ;
        RECT 113.770 224.760 114.000 225.750 ;
        RECT 113.050 185.550 114.000 224.760 ;
        RECT 115.900 224.760 116.230 225.750 ;
        RECT 116.530 224.760 116.850 225.750 ;
        RECT 115.900 182.500 116.850 224.760 ;
        RECT 121.450 224.760 121.750 225.750 ;
        RECT 122.050 224.760 122.400 225.750 ;
        RECT 93.800 181.100 97.600 182.050 ;
        RECT 91.050 179.300 94.850 180.250 ;
        RECT 76.300 171.050 80.950 172.000 ;
        RECT 42.700 154.700 99.850 155.900 ;
        RECT 42.700 154.600 48.050 154.700 ;
        RECT 6.000 149.900 106.750 151.000 ;
        RECT 31.050 141.500 106.950 142.700 ;
        RECT 31.200 136.100 35.250 136.200 ;
        RECT 31.200 136.000 106.650 136.100 ;
        RECT 6.000 134.900 106.650 136.000 ;
        RECT 31.200 134.800 106.650 134.900 ;
        RECT 31.250 128.300 106.150 129.500 ;
        RECT 31.650 122.950 35.250 123.000 ;
        RECT 6.000 122.900 35.250 122.950 ;
        RECT 6.000 121.800 107.850 122.900 ;
        RECT 121.450 102.800 122.400 224.760 ;
        RECT 124.350 224.760 124.510 225.750 ;
        RECT 124.810 224.760 125.300 225.750 ;
        RECT 124.350 102.850 125.300 224.760 ;
        RECT 127.050 224.760 127.270 225.750 ;
        RECT 127.570 224.760 128.000 225.750 ;
        RECT 127.050 102.900 128.000 224.760 ;
        RECT 129.500 224.760 130.030 225.750 ;
        RECT 130.330 224.760 130.450 225.750 ;
        RECT 129.500 102.950 130.450 224.760 ;
        RECT 132.350 224.760 132.790 225.750 ;
        RECT 133.090 224.760 133.300 225.750 ;
        RECT 132.350 102.950 133.300 224.760 ;
        RECT 135.100 224.760 135.550 225.750 ;
        RECT 135.850 224.760 136.050 225.750 ;
        RECT 135.100 103.000 136.050 224.760 ;
        RECT 137.850 224.760 138.310 225.750 ;
        RECT 138.610 224.760 138.800 225.750 ;
        RECT 137.850 103.200 138.800 224.760 ;
        RECT 140.600 224.760 141.070 225.750 ;
        RECT 141.370 224.760 141.600 225.750 ;
        RECT 140.600 124.000 141.600 224.760 ;
        RECT 143.100 224.760 143.830 225.750 ;
        RECT 144.130 224.760 144.500 225.750 ;
        RECT 140.500 118.950 141.800 124.000 ;
        RECT 143.100 101.100 144.500 224.760 ;
        RECT 30.150 99.700 144.500 101.100 ;
        RECT 30.150 92.500 31.300 99.700 ;
        RECT 96.150 91.900 107.550 93.000 ;
        RECT 6.000 89.300 62.300 89.750 ;
        RECT 62.950 89.300 64.150 89.350 ;
        RECT 96.400 89.300 98.950 91.900 ;
        RECT 6.000 88.400 98.950 89.300 ;
        RECT 6.000 88.350 47.800 88.400 ;
        RECT 41.700 78.700 43.250 88.350 ;
        RECT 61.400 87.950 98.950 88.400 ;
        RECT 67.900 82.200 72.050 87.950 ;
        RECT 67.900 80.950 79.700 82.200 ;
        RECT 67.900 80.900 87.550 80.950 ;
        RECT 41.700 77.700 45.750 78.700 ;
        RECT 6.000 74.150 37.000 76.350 ;
        RECT 30.200 67.700 31.250 73.250 ;
        RECT 35.400 68.100 37.000 74.150 ;
        RECT 44.500 71.100 45.750 77.700 ;
        RECT 74.750 68.450 76.200 79.950 ;
        RECT 78.850 79.600 87.550 80.900 ;
        RECT 86.350 75.350 87.550 79.600 ;
        RECT 101.000 76.050 108.050 77.250 ;
        RECT 101.000 73.550 102.450 76.050 ;
        RECT 103.250 71.000 104.550 74.400 ;
        RECT 92.600 69.350 104.550 71.000 ;
        RECT 92.600 68.450 94.150 69.350 ;
        RECT 74.750 66.800 94.150 68.450 ;
        RECT 35.100 58.550 36.700 62.750 ;
        RECT 6.000 56.150 36.700 58.550 ;
        RECT 74.750 57.150 76.200 66.800 ;
        RECT 35.100 55.000 36.700 56.150 ;
        RECT 64.900 55.450 72.200 56.500 ;
        RECT 74.750 55.900 78.200 57.150 ;
        RECT 47.200 53.250 57.100 54.150 ;
        RECT 64.900 53.250 66.550 55.450 ;
        RECT 47.200 53.100 66.550 53.250 ;
        RECT 47.200 49.300 48.900 53.100 ;
        RECT 55.650 51.650 66.550 53.100 ;
        RECT 55.650 51.600 60.250 51.650 ;
        RECT 6.000 47.500 48.900 49.300 ;
        RECT 58.350 49.400 60.150 51.600 ;
        RECT 77.100 51.250 78.200 55.900 ;
        RECT 81.800 56.300 83.050 63.350 ;
        RECT 95.100 56.300 96.650 56.350 ;
        RECT 81.800 55.450 96.650 56.300 ;
        RECT 81.800 55.350 89.950 55.450 ;
        RECT 95.100 55.350 96.650 55.450 ;
        RECT 87.300 49.400 89.950 55.350 ;
        RECT 95.150 55.200 96.600 55.350 ;
        RECT 58.350 47.850 89.950 49.400 ;
        RECT 58.350 47.750 89.750 47.850 ;
        RECT 81.900 46.150 83.100 47.750 ;
        RECT 100.800 34.050 102.400 69.350 ;
        RECT 106.850 41.700 108.050 76.050 ;
        RECT 106.850 40.550 152.800 41.700 ;
        RECT 100.800 32.300 133.900 34.050 ;
        RECT 132.100 1.000 133.900 32.300 ;
        RECT 132.100 0.000 132.490 1.000 ;
        RECT 133.390 0.000 133.900 1.000 ;
        RECT 151.700 1.000 152.800 40.550 ;
        RECT 151.700 0.000 151.810 1.000 ;
        RECT 152.710 0.000 152.800 1.000 ;
  END
END tt_um_irfantekin_analog
END LIBRARY

